VERSION 5.8 ;
BUSBITCHARS "[]" ;
DIVIDERCHAR "/" ;
UNITS
    DATABASE MICRONS 1000 ;
END UNITS

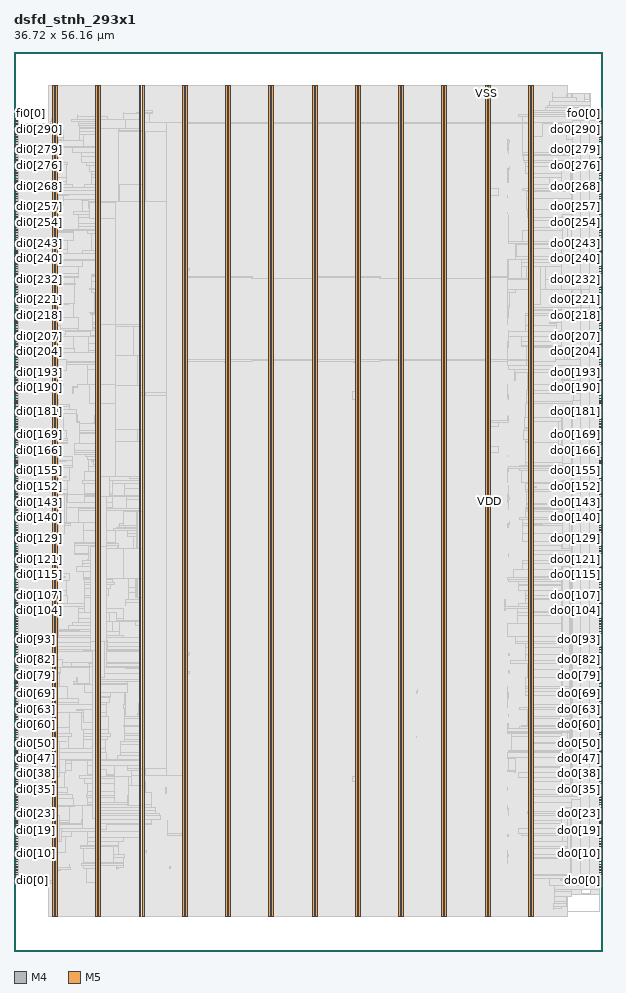
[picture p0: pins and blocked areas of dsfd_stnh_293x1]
MACRO dsfd_stnh_293x1
  FOREIGN dsfd_stnh_293x1 0 0 ;
  CLASS BLOCK ;
  SIZE 36.72 BY 56.16 ;
  PIN di0[0]
    DIRECTION INPUT ;
    USE SIGNAL ;
    PORT
      LAYER M4 ;
        RECT  0 4.416 0.192 4.44 ;
    END
  END di0[0]
  PIN di0[100]
    DIRECTION INPUT ;
    USE SIGNAL ;
    PORT
      LAYER M4 ;
        RECT  0 20.592 0.192 20.616 ;
    END
  END di0[100]
  PIN di0[101]
    DIRECTION INPUT ;
    USE SIGNAL ;
    PORT
      LAYER M4 ;
        RECT  0 20.736 0.192 20.76 ;
    END
  END di0[101]
  PIN di0[102]
    DIRECTION INPUT ;
    USE SIGNAL ;
    PORT
      LAYER M4 ;
        RECT  0 20.88 0.192 20.904 ;
    END
  END di0[102]
  PIN di0[103]
    DIRECTION INPUT ;
    USE SIGNAL ;
    PORT
      LAYER M4 ;
        RECT  0 21.072 0.192 21.096 ;
    END
  END di0[103]
  PIN di0[104]
    DIRECTION INPUT ;
    USE SIGNAL ;
    PORT
      LAYER M4 ;
        RECT  0 21.216 0.192 21.24 ;
    END
  END di0[104]
  PIN di0[105]
    DIRECTION INPUT ;
    USE SIGNAL ;
    PORT
      LAYER M4 ;
        RECT  0 21.408 0.192 21.432 ;
    END
  END di0[105]
  PIN di0[106]
    DIRECTION INPUT ;
    USE SIGNAL ;
    PORT
      LAYER M4 ;
        RECT  0 21.552 0.192 21.576 ;
    END
  END di0[106]
  PIN di0[107]
    DIRECTION INPUT ;
    USE SIGNAL ;
    PORT
      LAYER M4 ;
        RECT  0 21.696 0.192 21.72 ;
    END
  END di0[107]
  PIN di0[108]
    DIRECTION INPUT ;
    USE SIGNAL ;
    PORT
      LAYER M4 ;
        RECT  0 21.888 0.192 21.912 ;
    END
  END di0[108]
  PIN di0[109]
    DIRECTION INPUT ;
    USE SIGNAL ;
    PORT
      LAYER M4 ;
        RECT  0 22.032 0.192 22.056 ;
    END
  END di0[109]
  PIN di0[10]
    DIRECTION INPUT ;
    USE SIGNAL ;
    PORT
      LAYER M4 ;
        RECT  0 6.048 0.192 6.072 ;
    END
  END di0[10]
  PIN di0[110]
    DIRECTION INPUT ;
    USE SIGNAL ;
    PORT
      LAYER M4 ;
        RECT  0 22.176 0.192 22.2 ;
    END
  END di0[110]
  PIN di0[111]
    DIRECTION INPUT ;
    USE SIGNAL ;
    PORT
      LAYER M4 ;
        RECT  0 22.368 0.192 22.392 ;
    END
  END di0[111]
  PIN di0[112]
    DIRECTION INPUT ;
    USE SIGNAL ;
    PORT
      LAYER M4 ;
        RECT  0 22.512 0.192 22.536 ;
    END
  END di0[112]
  PIN di0[113]
    DIRECTION INPUT ;
    USE SIGNAL ;
    PORT
      LAYER M4 ;
        RECT  0 22.656 0.192 22.68 ;
    END
  END di0[113]
  PIN di0[114]
    DIRECTION INPUT ;
    USE SIGNAL ;
    PORT
      LAYER M4 ;
        RECT  0 22.848 0.192 22.872 ;
    END
  END di0[114]
  PIN di0[115]
    DIRECTION INPUT ;
    USE SIGNAL ;
    PORT
      LAYER M4 ;
        RECT  0 22.992 0.192 23.016 ;
    END
  END di0[115]
  PIN di0[116]
    DIRECTION INPUT ;
    USE SIGNAL ;
    PORT
      LAYER M4 ;
        RECT  0 23.184 0.192 23.208 ;
    END
  END di0[116]
  PIN di0[117]
    DIRECTION INPUT ;
    USE SIGNAL ;
    PORT
      LAYER M4 ;
        RECT  0 23.328 0.192 23.352 ;
    END
  END di0[117]
  PIN di0[118]
    DIRECTION INPUT ;
    USE SIGNAL ;
    PORT
      LAYER M4 ;
        RECT  0 23.472 0.192 23.496 ;
    END
  END di0[118]
  PIN di0[119]
    DIRECTION INPUT ;
    USE SIGNAL ;
    PORT
      LAYER M4 ;
        RECT  0 23.664 0.192 23.688 ;
    END
  END di0[119]
  PIN di0[11]
    DIRECTION INPUT ;
    USE SIGNAL ;
    PORT
      LAYER M4 ;
        RECT  0 6.192 0.192 6.216 ;
    END
  END di0[11]
  PIN di0[120]
    DIRECTION INPUT ;
    USE SIGNAL ;
    PORT
      LAYER M4 ;
        RECT  0 23.808 0.192 23.832 ;
    END
  END di0[120]
  PIN di0[121]
    DIRECTION INPUT ;
    USE SIGNAL ;
    PORT
      LAYER M4 ;
        RECT  0 23.952 0.192 23.976 ;
    END
  END di0[121]
  PIN di0[122]
    DIRECTION INPUT ;
    USE SIGNAL ;
    PORT
      LAYER M4 ;
        RECT  0 24.144 0.192 24.168 ;
    END
  END di0[122]
  PIN di0[123]
    DIRECTION INPUT ;
    USE SIGNAL ;
    PORT
      LAYER M4 ;
        RECT  0 24.288 0.192 24.312 ;
    END
  END di0[123]
  PIN di0[124]
    DIRECTION INPUT ;
    USE SIGNAL ;
    PORT
      LAYER M4 ;
        RECT  0 24.432 0.192 24.456 ;
    END
  END di0[124]
  PIN di0[125]
    DIRECTION INPUT ;
    USE SIGNAL ;
    PORT
      LAYER M4 ;
        RECT  0 24.624 0.192 24.648 ;
    END
  END di0[125]
  PIN di0[126]
    DIRECTION INPUT ;
    USE SIGNAL ;
    PORT
      LAYER M4 ;
        RECT  0 24.768 0.192 24.792 ;
    END
  END di0[126]
  PIN di0[127]
    DIRECTION INPUT ;
    USE SIGNAL ;
    PORT
      LAYER M4 ;
        RECT  0 24.96 0.192 24.984 ;
    END
  END di0[127]
  PIN di0[128]
    DIRECTION INPUT ;
    USE SIGNAL ;
    PORT
      LAYER M4 ;
        RECT  0 25.104 0.192 25.128 ;
    END
  END di0[128]
  PIN di0[129]
    DIRECTION INPUT ;
    USE SIGNAL ;
    PORT
      LAYER M4 ;
        RECT  0 25.248 0.192 25.272 ;
    END
  END di0[129]
  PIN di0[12]
    DIRECTION INPUT ;
    USE SIGNAL ;
    PORT
      LAYER M4 ;
        RECT  0 6.336 0.192 6.36 ;
    END
  END di0[12]
  PIN di0[130]
    DIRECTION INPUT ;
    USE SIGNAL ;
    PORT
      LAYER M4 ;
        RECT  0 25.44 0.192 25.464 ;
    END
  END di0[130]
  PIN di0[131]
    DIRECTION INPUT ;
    USE SIGNAL ;
    PORT
      LAYER M4 ;
        RECT  0 25.584 0.192 25.608 ;
    END
  END di0[131]
  PIN di0[132]
    DIRECTION INPUT ;
    USE SIGNAL ;
    PORT
      LAYER M4 ;
        RECT  0 25.728 0.192 25.752 ;
    END
  END di0[132]
  PIN di0[133]
    DIRECTION INPUT ;
    USE SIGNAL ;
    PORT
      LAYER M4 ;
        RECT  0 25.92 0.192 25.944 ;
    END
  END di0[133]
  PIN di0[134]
    DIRECTION INPUT ;
    USE SIGNAL ;
    PORT
      LAYER M4 ;
        RECT  0 26.064 0.192 26.088 ;
    END
  END di0[134]
  PIN di0[135]
    DIRECTION INPUT ;
    USE SIGNAL ;
    PORT
      LAYER M4 ;
        RECT  0 26.256 0.192 26.28 ;
    END
  END di0[135]
  PIN di0[136]
    DIRECTION INPUT ;
    USE SIGNAL ;
    PORT
      LAYER M4 ;
        RECT  0 26.4 0.192 26.424 ;
    END
  END di0[136]
  PIN di0[137]
    DIRECTION INPUT ;
    USE SIGNAL ;
    PORT
      LAYER M4 ;
        RECT  0 26.544 0.192 26.568 ;
    END
  END di0[137]
  PIN di0[138]
    DIRECTION INPUT ;
    USE SIGNAL ;
    PORT
      LAYER M4 ;
        RECT  0 26.736 0.192 26.76 ;
    END
  END di0[138]
  PIN di0[139]
    DIRECTION INPUT ;
    USE SIGNAL ;
    PORT
      LAYER M4 ;
        RECT  0 26.88 0.192 26.904 ;
    END
  END di0[139]
  PIN di0[13]
    DIRECTION INPUT ;
    USE SIGNAL ;
    PORT
      LAYER M4 ;
        RECT  0 6.528 0.192 6.552 ;
    END
  END di0[13]
  PIN di0[140]
    DIRECTION INPUT ;
    USE SIGNAL ;
    PORT
      LAYER M4 ;
        RECT  0 27.024 0.192 27.048 ;
    END
  END di0[140]
  PIN di0[141]
    DIRECTION INPUT ;
    USE SIGNAL ;
    PORT
      LAYER M4 ;
        RECT  0 27.216 0.192 27.24 ;
    END
  END di0[141]
  PIN di0[142]
    DIRECTION INPUT ;
    USE SIGNAL ;
    PORT
      LAYER M4 ;
        RECT  0 27.36 0.192 27.384 ;
    END
  END di0[142]
  PIN di0[143]
    DIRECTION INPUT ;
    USE SIGNAL ;
    PORT
      LAYER M4 ;
        RECT  0 27.504 0.192 27.528 ;
    END
  END di0[143]
  PIN di0[144]
    DIRECTION INPUT ;
    USE SIGNAL ;
    PORT
      LAYER M4 ;
        RECT  0 27.696 0.192 27.72 ;
    END
  END di0[144]
  PIN di0[145]
    DIRECTION INPUT ;
    USE SIGNAL ;
    PORT
      LAYER M4 ;
        RECT  0 27.84 0.192 27.864 ;
    END
  END di0[145]
  PIN di0[146]
    DIRECTION INPUT ;
    USE SIGNAL ;
    PORT
      LAYER M4 ;
        RECT  0 28.032 0.192 28.056 ;
    END
  END di0[146]
  PIN di0[147]
    DIRECTION INPUT ;
    USE SIGNAL ;
    PORT
      LAYER M4 ;
        RECT  0 28.176 0.192 28.2 ;
    END
  END di0[147]
  PIN di0[148]
    DIRECTION INPUT ;
    USE SIGNAL ;
    PORT
      LAYER M4 ;
        RECT  0 28.32 0.192 28.344 ;
    END
  END di0[148]
  PIN di0[149]
    DIRECTION INPUT ;
    USE SIGNAL ;
    PORT
      LAYER M4 ;
        RECT  0 28.512 0.192 28.536 ;
    END
  END di0[149]
  PIN di0[14]
    DIRECTION INPUT ;
    USE SIGNAL ;
    PORT
      LAYER M4 ;
        RECT  0 6.672 0.192 6.696 ;
    END
  END di0[14]
  PIN di0[150]
    DIRECTION INPUT ;
    USE SIGNAL ;
    PORT
      LAYER M4 ;
        RECT  0 28.656 0.192 28.68 ;
    END
  END di0[150]
  PIN di0[151]
    DIRECTION INPUT ;
    USE SIGNAL ;
    PORT
      LAYER M4 ;
        RECT  0 28.8 0.192 28.824 ;
    END
  END di0[151]
  PIN di0[152]
    DIRECTION INPUT ;
    USE SIGNAL ;
    PORT
      LAYER M4 ;
        RECT  0 28.992 0.192 29.016 ;
    END
  END di0[152]
  PIN di0[153]
    DIRECTION INPUT ;
    USE SIGNAL ;
    PORT
      LAYER M4 ;
        RECT  0 29.136 0.192 29.16 ;
    END
  END di0[153]
  PIN di0[154]
    DIRECTION INPUT ;
    USE SIGNAL ;
    PORT
      LAYER M4 ;
        RECT  0 29.328 0.192 29.352 ;
    END
  END di0[154]
  PIN di0[155]
    DIRECTION INPUT ;
    USE SIGNAL ;
    PORT
      LAYER M4 ;
        RECT  0 29.472 0.192 29.496 ;
    END
  END di0[155]
  PIN di0[156]
    DIRECTION INPUT ;
    USE SIGNAL ;
    PORT
      LAYER M4 ;
        RECT  0 29.616 0.192 29.64 ;
    END
  END di0[156]
  PIN di0[157]
    DIRECTION INPUT ;
    USE SIGNAL ;
    PORT
      LAYER M4 ;
        RECT  0 29.808 0.192 29.832 ;
    END
  END di0[157]
  PIN di0[158]
    DIRECTION INPUT ;
    USE SIGNAL ;
    PORT
      LAYER M4 ;
        RECT  0 29.952 0.192 29.976 ;
    END
  END di0[158]
  PIN di0[159]
    DIRECTION INPUT ;
    USE SIGNAL ;
    PORT
      LAYER M4 ;
        RECT  0 30.096 0.192 30.12 ;
    END
  END di0[159]
  PIN di0[15]
    DIRECTION INPUT ;
    USE SIGNAL ;
    PORT
      LAYER M4 ;
        RECT  0 6.816 0.192 6.84 ;
    END
  END di0[15]
  PIN di0[160]
    DIRECTION INPUT ;
    USE SIGNAL ;
    PORT
      LAYER M4 ;
        RECT  0 30.288 0.192 30.312 ;
    END
  END di0[160]
  PIN di0[161]
    DIRECTION INPUT ;
    USE SIGNAL ;
    PORT
      LAYER M4 ;
        RECT  0 30.432 0.192 30.456 ;
    END
  END di0[161]
  PIN di0[162]
    DIRECTION INPUT ;
    USE SIGNAL ;
    PORT
      LAYER M4 ;
        RECT  0 30.576 0.192 30.6 ;
    END
  END di0[162]
  PIN di0[163]
    DIRECTION INPUT ;
    USE SIGNAL ;
    PORT
      LAYER M4 ;
        RECT  0 30.768 0.192 30.792 ;
    END
  END di0[163]
  PIN di0[164]
    DIRECTION INPUT ;
    USE SIGNAL ;
    PORT
      LAYER M4 ;
        RECT  0 30.912 0.192 30.936 ;
    END
  END di0[164]
  PIN di0[165]
    DIRECTION INPUT ;
    USE SIGNAL ;
    PORT
      LAYER M4 ;
        RECT  0 31.104 0.192 31.128 ;
    END
  END di0[165]
  PIN di0[166]
    DIRECTION INPUT ;
    USE SIGNAL ;
    PORT
      LAYER M4 ;
        RECT  0 31.248 0.192 31.272 ;
    END
  END di0[166]
  PIN di0[167]
    DIRECTION INPUT ;
    USE SIGNAL ;
    PORT
      LAYER M4 ;
        RECT  0 31.392 0.192 31.416 ;
    END
  END di0[167]
  PIN di0[168]
    DIRECTION INPUT ;
    USE SIGNAL ;
    PORT
      LAYER M4 ;
        RECT  0 31.584 0.192 31.608 ;
    END
  END di0[168]
  PIN di0[169]
    DIRECTION INPUT ;
    USE SIGNAL ;
    PORT
      LAYER M4 ;
        RECT  0 31.728 0.192 31.752 ;
    END
  END di0[169]
  PIN di0[16]
    DIRECTION INPUT ;
    USE SIGNAL ;
    PORT
      LAYER M4 ;
        RECT  0 7.008 0.192 7.032 ;
    END
  END di0[16]
  PIN di0[170]
    DIRECTION INPUT ;
    USE SIGNAL ;
    PORT
      LAYER M4 ;
        RECT  0 31.872 0.192 31.896 ;
    END
  END di0[170]
  PIN di0[171]
    DIRECTION INPUT ;
    USE SIGNAL ;
    PORT
      LAYER M4 ;
        RECT  0 32.064 0.192 32.088 ;
    END
  END di0[171]
  PIN di0[172]
    DIRECTION INPUT ;
    USE SIGNAL ;
    PORT
      LAYER M4 ;
        RECT  0 32.208 0.192 32.232 ;
    END
  END di0[172]
  PIN di0[173]
    DIRECTION INPUT ;
    USE SIGNAL ;
    PORT
      LAYER M4 ;
        RECT  0 32.352 0.192 32.376 ;
    END
  END di0[173]
  PIN di0[174]
    DIRECTION INPUT ;
    USE SIGNAL ;
    PORT
      LAYER M4 ;
        RECT  0 32.544 0.192 32.568 ;
    END
  END di0[174]
  PIN di0[175]
    DIRECTION INPUT ;
    USE SIGNAL ;
    PORT
      LAYER M4 ;
        RECT  0 32.688 0.192 32.712 ;
    END
  END di0[175]
  PIN di0[176]
    DIRECTION INPUT ;
    USE SIGNAL ;
    PORT
      LAYER M4 ;
        RECT  0 32.88 0.192 32.904 ;
    END
  END di0[176]
  PIN di0[177]
    DIRECTION INPUT ;
    USE SIGNAL ;
    PORT
      LAYER M4 ;
        RECT  0 33.024 0.192 33.048 ;
    END
  END di0[177]
  PIN di0[178]
    DIRECTION INPUT ;
    USE SIGNAL ;
    PORT
      LAYER M4 ;
        RECT  0 33.168 0.192 33.192 ;
    END
  END di0[178]
  PIN di0[179]
    DIRECTION INPUT ;
    USE SIGNAL ;
    PORT
      LAYER M4 ;
        RECT  0 33.36 0.192 33.384 ;
    END
  END di0[179]
  PIN di0[17]
    DIRECTION INPUT ;
    USE SIGNAL ;
    PORT
      LAYER M4 ;
        RECT  0 7.152 0.192 7.176 ;
    END
  END di0[17]
  PIN di0[180]
    DIRECTION INPUT ;
    USE SIGNAL ;
    PORT
      LAYER M4 ;
        RECT  0 33.504 0.192 33.528 ;
    END
  END di0[180]
  PIN di0[181]
    DIRECTION INPUT ;
    USE SIGNAL ;
    PORT
      LAYER M4 ;
        RECT  0 33.648 0.192 33.672 ;
    END
  END di0[181]
  PIN di0[182]
    DIRECTION INPUT ;
    USE SIGNAL ;
    PORT
      LAYER M4 ;
        RECT  0 33.84 0.192 33.864 ;
    END
  END di0[182]
  PIN di0[183]
    DIRECTION INPUT ;
    USE SIGNAL ;
    PORT
      LAYER M4 ;
        RECT  0 33.984 0.192 34.008 ;
    END
  END di0[183]
  PIN di0[184]
    DIRECTION INPUT ;
    USE SIGNAL ;
    PORT
      LAYER M4 ;
        RECT  0 34.176 0.192 34.2 ;
    END
  END di0[184]
  PIN di0[185]
    DIRECTION INPUT ;
    USE SIGNAL ;
    PORT
      LAYER M4 ;
        RECT  0 34.32 0.192 34.344 ;
    END
  END di0[185]
  PIN di0[186]
    DIRECTION INPUT ;
    USE SIGNAL ;
    PORT
      LAYER M4 ;
        RECT  0 34.464 0.192 34.488 ;
    END
  END di0[186]
  PIN di0[187]
    DIRECTION INPUT ;
    USE SIGNAL ;
    PORT
      LAYER M4 ;
        RECT  0 34.656 0.192 34.68 ;
    END
  END di0[187]
  PIN di0[188]
    DIRECTION INPUT ;
    USE SIGNAL ;
    PORT
      LAYER M4 ;
        RECT  0 34.8 0.192 34.824 ;
    END
  END di0[188]
  PIN di0[189]
    DIRECTION INPUT ;
    USE SIGNAL ;
    PORT
      LAYER M4 ;
        RECT  0 34.944 0.192 34.968 ;
    END
  END di0[189]
  PIN di0[18]
    DIRECTION INPUT ;
    USE SIGNAL ;
    PORT
      LAYER M4 ;
        RECT  0 7.344 0.192 7.368 ;
    END
  END di0[18]
  PIN di0[190]
    DIRECTION INPUT ;
    USE SIGNAL ;
    PORT
      LAYER M4 ;
        RECT  0 35.136 0.192 35.16 ;
    END
  END di0[190]
  PIN di0[191]
    DIRECTION INPUT ;
    USE SIGNAL ;
    PORT
      LAYER M4 ;
        RECT  0 35.28 0.192 35.304 ;
    END
  END di0[191]
  PIN di0[192]
    DIRECTION INPUT ;
    USE SIGNAL ;
    PORT
      LAYER M4 ;
        RECT  0 35.424 0.192 35.448 ;
    END
  END di0[192]
  PIN di0[193]
    DIRECTION INPUT ;
    USE SIGNAL ;
    PORT
      LAYER M4 ;
        RECT  0 35.616 0.192 35.64 ;
    END
  END di0[193]
  PIN di0[194]
    DIRECTION INPUT ;
    USE SIGNAL ;
    PORT
      LAYER M4 ;
        RECT  0 35.76 0.192 35.784 ;
    END
  END di0[194]
  PIN di0[195]
    DIRECTION INPUT ;
    USE SIGNAL ;
    PORT
      LAYER M4 ;
        RECT  0 35.952 0.192 35.976 ;
    END
  END di0[195]
  PIN di0[196]
    DIRECTION INPUT ;
    USE SIGNAL ;
    PORT
      LAYER M4 ;
        RECT  0 36.096 0.192 36.12 ;
    END
  END di0[196]
  PIN di0[197]
    DIRECTION INPUT ;
    USE SIGNAL ;
    PORT
      LAYER M4 ;
        RECT  0 36.24 0.192 36.264 ;
    END
  END di0[197]
  PIN di0[198]
    DIRECTION INPUT ;
    USE SIGNAL ;
    PORT
      LAYER M4 ;
        RECT  0 36.432 0.192 36.456 ;
    END
  END di0[198]
  PIN di0[199]
    DIRECTION INPUT ;
    USE SIGNAL ;
    PORT
      LAYER M4 ;
        RECT  0 36.576 0.192 36.6 ;
    END
  END di0[199]
  PIN di0[19]
    DIRECTION INPUT ;
    USE SIGNAL ;
    PORT
      LAYER M4 ;
        RECT  0 7.488 0.192 7.512 ;
    END
  END di0[19]
  PIN di0[1]
    DIRECTION INPUT ;
    USE SIGNAL ;
    PORT
      LAYER M4 ;
        RECT  0 4.56 0.192 4.584 ;
    END
  END di0[1]
  PIN di0[200]
    DIRECTION INPUT ;
    USE SIGNAL ;
    PORT
      LAYER M4 ;
        RECT  0 36.72 0.192 36.744 ;
    END
  END di0[200]
  PIN di0[201]
    DIRECTION INPUT ;
    USE SIGNAL ;
    PORT
      LAYER M4 ;
        RECT  0 36.912 0.192 36.936 ;
    END
  END di0[201]
  PIN di0[202]
    DIRECTION INPUT ;
    USE SIGNAL ;
    PORT
      LAYER M4 ;
        RECT  0 37.056 0.192 37.08 ;
    END
  END di0[202]
  PIN di0[203]
    DIRECTION INPUT ;
    USE SIGNAL ;
    PORT
      LAYER M4 ;
        RECT  0 37.248 0.192 37.272 ;
    END
  END di0[203]
  PIN di0[204]
    DIRECTION INPUT ;
    USE SIGNAL ;
    PORT
      LAYER M4 ;
        RECT  0 37.392 0.192 37.416 ;
    END
  END di0[204]
  PIN di0[205]
    DIRECTION INPUT ;
    USE SIGNAL ;
    PORT
      LAYER M4 ;
        RECT  0 37.536 0.192 37.56 ;
    END
  END di0[205]
  PIN di0[206]
    DIRECTION INPUT ;
    USE SIGNAL ;
    PORT
      LAYER M4 ;
        RECT  0 37.728 0.192 37.752 ;
    END
  END di0[206]
  PIN di0[207]
    DIRECTION INPUT ;
    USE SIGNAL ;
    PORT
      LAYER M4 ;
        RECT  0 37.872 0.192 37.896 ;
    END
  END di0[207]
  PIN di0[208]
    DIRECTION INPUT ;
    USE SIGNAL ;
    PORT
      LAYER M4 ;
        RECT  0 38.016 0.192 38.04 ;
    END
  END di0[208]
  PIN di0[209]
    DIRECTION INPUT ;
    USE SIGNAL ;
    PORT
      LAYER M4 ;
        RECT  0 38.208 0.192 38.232 ;
    END
  END di0[209]
  PIN di0[20]
    DIRECTION INPUT ;
    USE SIGNAL ;
    PORT
      LAYER M4 ;
        RECT  0 7.632 0.192 7.656 ;
    END
  END di0[20]
  PIN di0[210]
    DIRECTION INPUT ;
    USE SIGNAL ;
    PORT
      LAYER M4 ;
        RECT  0 38.352 0.192 38.376 ;
    END
  END di0[210]
  PIN di0[211]
    DIRECTION INPUT ;
    USE SIGNAL ;
    PORT
      LAYER M4 ;
        RECT  0 38.496 0.192 38.52 ;
    END
  END di0[211]
  PIN di0[212]
    DIRECTION INPUT ;
    USE SIGNAL ;
    PORT
      LAYER M4 ;
        RECT  0 38.688 0.192 38.712 ;
    END
  END di0[212]
  PIN di0[213]
    DIRECTION INPUT ;
    USE SIGNAL ;
    PORT
      LAYER M4 ;
        RECT  0 38.832 0.192 38.856 ;
    END
  END di0[213]
  PIN di0[214]
    DIRECTION INPUT ;
    USE SIGNAL ;
    PORT
      LAYER M4 ;
        RECT  0 39.024 0.192 39.048 ;
    END
  END di0[214]
  PIN di0[215]
    DIRECTION INPUT ;
    USE SIGNAL ;
    PORT
      LAYER M4 ;
        RECT  0 39.168 0.192 39.192 ;
    END
  END di0[215]
  PIN di0[216]
    DIRECTION INPUT ;
    USE SIGNAL ;
    PORT
      LAYER M4 ;
        RECT  0 39.312 0.192 39.336 ;
    END
  END di0[216]
  PIN di0[217]
    DIRECTION INPUT ;
    USE SIGNAL ;
    PORT
      LAYER M4 ;
        RECT  0 39.504 0.192 39.528 ;
    END
  END di0[217]
  PIN di0[218]
    DIRECTION INPUT ;
    USE SIGNAL ;
    PORT
      LAYER M4 ;
        RECT  0 39.648 0.192 39.672 ;
    END
  END di0[218]
  PIN di0[219]
    DIRECTION INPUT ;
    USE SIGNAL ;
    PORT
      LAYER M4 ;
        RECT  0 39.792 0.192 39.816 ;
    END
  END di0[219]
  PIN di0[21]
    DIRECTION INPUT ;
    USE SIGNAL ;
    PORT
      LAYER M4 ;
        RECT  0 7.824 0.192 7.848 ;
    END
  END di0[21]
  PIN di0[220]
    DIRECTION INPUT ;
    USE SIGNAL ;
    PORT
      LAYER M4 ;
        RECT  0 39.984 0.192 40.008 ;
    END
  END di0[220]
  PIN di0[221]
    DIRECTION INPUT ;
    USE SIGNAL ;
    PORT
      LAYER M4 ;
        RECT  0 40.128 0.192 40.152 ;
    END
  END di0[221]
  PIN di0[222]
    DIRECTION INPUT ;
    USE SIGNAL ;
    PORT
      LAYER M4 ;
        RECT  0 40.272 0.192 40.296 ;
    END
  END di0[222]
  PIN di0[223]
    DIRECTION INPUT ;
    USE SIGNAL ;
    PORT
      LAYER M4 ;
        RECT  0 40.464 0.192 40.488 ;
    END
  END di0[223]
  PIN di0[224]
    DIRECTION INPUT ;
    USE SIGNAL ;
    PORT
      LAYER M4 ;
        RECT  0 40.608 0.192 40.632 ;
    END
  END di0[224]
  PIN di0[225]
    DIRECTION INPUT ;
    USE SIGNAL ;
    PORT
      LAYER M4 ;
        RECT  0 40.8 0.192 40.824 ;
    END
  END di0[225]
  PIN di0[226]
    DIRECTION INPUT ;
    USE SIGNAL ;
    PORT
      LAYER M4 ;
        RECT  0 40.944 0.192 40.968 ;
    END
  END di0[226]
  PIN di0[227]
    DIRECTION INPUT ;
    USE SIGNAL ;
    PORT
      LAYER M4 ;
        RECT  0 41.088 0.192 41.112 ;
    END
  END di0[227]
  PIN di0[228]
    DIRECTION INPUT ;
    USE SIGNAL ;
    PORT
      LAYER M4 ;
        RECT  0 41.28 0.192 41.304 ;
    END
  END di0[228]
  PIN di0[229]
    DIRECTION INPUT ;
    USE SIGNAL ;
    PORT
      LAYER M4 ;
        RECT  0 41.424 0.192 41.448 ;
    END
  END di0[229]
  PIN di0[22]
    DIRECTION INPUT ;
    USE SIGNAL ;
    PORT
      LAYER M4 ;
        RECT  0 7.968 0.192 7.992 ;
    END
  END di0[22]
  PIN di0[230]
    DIRECTION INPUT ;
    USE SIGNAL ;
    PORT
      LAYER M4 ;
        RECT  0 41.568 0.192 41.592 ;
    END
  END di0[230]
  PIN di0[231]
    DIRECTION INPUT ;
    USE SIGNAL ;
    PORT
      LAYER M4 ;
        RECT  0 41.76 0.192 41.784 ;
    END
  END di0[231]
  PIN di0[232]
    DIRECTION INPUT ;
    USE SIGNAL ;
    PORT
      LAYER M4 ;
        RECT  0 41.904 0.192 41.928 ;
    END
  END di0[232]
  PIN di0[233]
    DIRECTION INPUT ;
    USE SIGNAL ;
    PORT
      LAYER M4 ;
        RECT  0 42.096 0.192 42.12 ;
    END
  END di0[233]
  PIN di0[234]
    DIRECTION INPUT ;
    USE SIGNAL ;
    PORT
      LAYER M4 ;
        RECT  0 42.24 0.192 42.264 ;
    END
  END di0[234]
  PIN di0[235]
    DIRECTION INPUT ;
    USE SIGNAL ;
    PORT
      LAYER M4 ;
        RECT  0 42.384 0.192 42.408 ;
    END
  END di0[235]
  PIN di0[236]
    DIRECTION INPUT ;
    USE SIGNAL ;
    PORT
      LAYER M4 ;
        RECT  0 42.576 0.192 42.6 ;
    END
  END di0[236]
  PIN di0[237]
    DIRECTION INPUT ;
    USE SIGNAL ;
    PORT
      LAYER M4 ;
        RECT  0 42.72 0.192 42.744 ;
    END
  END di0[237]
  PIN di0[238]
    DIRECTION INPUT ;
    USE SIGNAL ;
    PORT
      LAYER M4 ;
        RECT  0 42.864 0.192 42.888 ;
    END
  END di0[238]
  PIN di0[239]
    DIRECTION INPUT ;
    USE SIGNAL ;
    PORT
      LAYER M4 ;
        RECT  0 43.056 0.192 43.08 ;
    END
  END di0[239]
  PIN di0[23]
    DIRECTION INPUT ;
    USE SIGNAL ;
    PORT
      LAYER M4 ;
        RECT  0 8.112 0.192 8.136 ;
    END
  END di0[23]
  PIN di0[240]
    DIRECTION INPUT ;
    USE SIGNAL ;
    PORT
      LAYER M4 ;
        RECT  0 43.2 0.192 43.224 ;
    END
  END di0[240]
  PIN di0[241]
    DIRECTION INPUT ;
    USE SIGNAL ;
    PORT
      LAYER M4 ;
        RECT  0 43.344 0.192 43.368 ;
    END
  END di0[241]
  PIN di0[242]
    DIRECTION INPUT ;
    USE SIGNAL ;
    PORT
      LAYER M4 ;
        RECT  0 43.536 0.192 43.56 ;
    END
  END di0[242]
  PIN di0[243]
    DIRECTION INPUT ;
    USE SIGNAL ;
    PORT
      LAYER M4 ;
        RECT  0 43.68 0.192 43.704 ;
    END
  END di0[243]
  PIN di0[244]
    DIRECTION INPUT ;
    USE SIGNAL ;
    PORT
      LAYER M4 ;
        RECT  0 43.872 0.192 43.896 ;
    END
  END di0[244]
  PIN di0[245]
    DIRECTION INPUT ;
    USE SIGNAL ;
    PORT
      LAYER M4 ;
        RECT  0 44.016 0.192 44.04 ;
    END
  END di0[245]
  PIN di0[246]
    DIRECTION INPUT ;
    USE SIGNAL ;
    PORT
      LAYER M4 ;
        RECT  0 44.16 0.192 44.184 ;
    END
  END di0[246]
  PIN di0[247]
    DIRECTION INPUT ;
    USE SIGNAL ;
    PORT
      LAYER M4 ;
        RECT  0 44.352 0.192 44.376 ;
    END
  END di0[247]
  PIN di0[248]
    DIRECTION INPUT ;
    USE SIGNAL ;
    PORT
      LAYER M4 ;
        RECT  0 44.496 0.192 44.52 ;
    END
  END di0[248]
  PIN di0[249]
    DIRECTION INPUT ;
    USE SIGNAL ;
    PORT
      LAYER M4 ;
        RECT  0 44.64 0.192 44.664 ;
    END
  END di0[249]
  PIN di0[24]
    DIRECTION INPUT ;
    USE SIGNAL ;
    PORT
      LAYER M4 ;
        RECT  0 8.304 0.192 8.328 ;
    END
  END di0[24]
  PIN di0[250]
    DIRECTION INPUT ;
    USE SIGNAL ;
    PORT
      LAYER M4 ;
        RECT  0 44.832 0.192 44.856 ;
    END
  END di0[250]
  PIN di0[251]
    DIRECTION INPUT ;
    USE SIGNAL ;
    PORT
      LAYER M4 ;
        RECT  0 44.976 0.192 45 ;
    END
  END di0[251]
  PIN di0[252]
    DIRECTION INPUT ;
    USE SIGNAL ;
    PORT
      LAYER M4 ;
        RECT  0 45.168 0.192 45.192 ;
    END
  END di0[252]
  PIN di0[253]
    DIRECTION INPUT ;
    USE SIGNAL ;
    PORT
      LAYER M4 ;
        RECT  0 45.312 0.192 45.336 ;
    END
  END di0[253]
  PIN di0[254]
    DIRECTION INPUT ;
    USE SIGNAL ;
    PORT
      LAYER M4 ;
        RECT  0 45.456 0.192 45.48 ;
    END
  END di0[254]
  PIN di0[255]
    DIRECTION INPUT ;
    USE SIGNAL ;
    PORT
      LAYER M4 ;
        RECT  0 45.648 0.192 45.672 ;
    END
  END di0[255]
  PIN di0[256]
    DIRECTION INPUT ;
    USE SIGNAL ;
    PORT
      LAYER M4 ;
        RECT  0 45.792 0.192 45.816 ;
    END
  END di0[256]
  PIN di0[257]
    DIRECTION INPUT ;
    USE SIGNAL ;
    PORT
      LAYER M4 ;
        RECT  0 45.936 0.192 45.96 ;
    END
  END di0[257]
  PIN di0[258]
    DIRECTION INPUT ;
    USE SIGNAL ;
    PORT
      LAYER M4 ;
        RECT  0 46.128 0.192 46.152 ;
    END
  END di0[258]
  PIN di0[259]
    DIRECTION INPUT ;
    USE SIGNAL ;
    PORT
      LAYER M4 ;
        RECT  0 46.272 0.192 46.296 ;
    END
  END di0[259]
  PIN di0[25]
    DIRECTION INPUT ;
    USE SIGNAL ;
    PORT
      LAYER M4 ;
        RECT  0 8.448 0.192 8.472 ;
    END
  END di0[25]
  PIN di0[260]
    DIRECTION INPUT ;
    USE SIGNAL ;
    PORT
      LAYER M4 ;
        RECT  0 46.416 0.192 46.44 ;
    END
  END di0[260]
  PIN di0[261]
    DIRECTION INPUT ;
    USE SIGNAL ;
    PORT
      LAYER M4 ;
        RECT  0 46.608 0.192 46.632 ;
    END
  END di0[261]
  PIN di0[262]
    DIRECTION INPUT ;
    USE SIGNAL ;
    PORT
      LAYER M4 ;
        RECT  0 46.752 0.192 46.776 ;
    END
  END di0[262]
  PIN di0[263]
    DIRECTION INPUT ;
    USE SIGNAL ;
    PORT
      LAYER M4 ;
        RECT  0 46.944 0.192 46.968 ;
    END
  END di0[263]
  PIN di0[264]
    DIRECTION INPUT ;
    USE SIGNAL ;
    PORT
      LAYER M4 ;
        RECT  0 47.088 0.192 47.112 ;
    END
  END di0[264]
  PIN di0[265]
    DIRECTION INPUT ;
    USE SIGNAL ;
    PORT
      LAYER M4 ;
        RECT  0 47.232 0.192 47.256 ;
    END
  END di0[265]
  PIN di0[266]
    DIRECTION INPUT ;
    USE SIGNAL ;
    PORT
      LAYER M4 ;
        RECT  0 47.424 0.192 47.448 ;
    END
  END di0[266]
  PIN di0[267]
    DIRECTION INPUT ;
    USE SIGNAL ;
    PORT
      LAYER M4 ;
        RECT  0 47.568 0.192 47.592 ;
    END
  END di0[267]
  PIN di0[268]
    DIRECTION INPUT ;
    USE SIGNAL ;
    PORT
      LAYER M4 ;
        RECT  0 47.712 0.192 47.736 ;
    END
  END di0[268]
  PIN di0[269]
    DIRECTION INPUT ;
    USE SIGNAL ;
    PORT
      LAYER M4 ;
        RECT  0 47.904 0.192 47.928 ;
    END
  END di0[269]
  PIN di0[26]
    DIRECTION INPUT ;
    USE SIGNAL ;
    PORT
      LAYER M4 ;
        RECT  0 8.592 0.192 8.616 ;
    END
  END di0[26]
  PIN di0[270]
    DIRECTION INPUT ;
    USE SIGNAL ;
    PORT
      LAYER M4 ;
        RECT  0 48.048 0.192 48.072 ;
    END
  END di0[270]
  PIN di0[271]
    DIRECTION INPUT ;
    USE SIGNAL ;
    PORT
      LAYER M4 ;
        RECT  0 48.192 0.192 48.216 ;
    END
  END di0[271]
  PIN di0[272]
    DIRECTION INPUT ;
    USE SIGNAL ;
    PORT
      LAYER M4 ;
        RECT  0 48.384 0.192 48.408 ;
    END
  END di0[272]
  PIN di0[273]
    DIRECTION INPUT ;
    USE SIGNAL ;
    PORT
      LAYER M4 ;
        RECT  0 48.528 0.192 48.552 ;
    END
  END di0[273]
  PIN di0[274]
    DIRECTION INPUT ;
    USE SIGNAL ;
    PORT
      LAYER M4 ;
        RECT  0 48.72 0.192 48.744 ;
    END
  END di0[274]
  PIN di0[275]
    DIRECTION INPUT ;
    USE SIGNAL ;
    PORT
      LAYER M4 ;
        RECT  0 48.864 0.192 48.888 ;
    END
  END di0[275]
  PIN di0[276]
    DIRECTION INPUT ;
    USE SIGNAL ;
    PORT
      LAYER M4 ;
        RECT  0 49.008 0.192 49.032 ;
    END
  END di0[276]
  PIN di0[277]
    DIRECTION INPUT ;
    USE SIGNAL ;
    PORT
      LAYER M4 ;
        RECT  0 49.2 0.192 49.224 ;
    END
  END di0[277]
  PIN di0[278]
    DIRECTION INPUT ;
    USE SIGNAL ;
    PORT
      LAYER M4 ;
        RECT  0 49.344 0.192 49.368 ;
    END
  END di0[278]
  PIN di0[279]
    DIRECTION INPUT ;
    USE SIGNAL ;
    PORT
      LAYER M4 ;
        RECT  0 49.488 0.192 49.512 ;
    END
  END di0[279]
  PIN di0[27]
    DIRECTION INPUT ;
    USE SIGNAL ;
    PORT
      LAYER M4 ;
        RECT  0 8.784 0.192 8.808 ;
    END
  END di0[27]
  PIN di0[280]
    DIRECTION INPUT ;
    USE SIGNAL ;
    PORT
      LAYER M4 ;
        RECT  0 49.68 0.192 49.704 ;
    END
  END di0[280]
  PIN di0[281]
    DIRECTION INPUT ;
    USE SIGNAL ;
    PORT
      LAYER M4 ;
        RECT  0 49.824 0.192 49.848 ;
    END
  END di0[281]
  PIN di0[282]
    DIRECTION INPUT ;
    USE SIGNAL ;
    PORT
      LAYER M4 ;
        RECT  0 50.016 0.192 50.04 ;
    END
  END di0[282]
  PIN di0[283]
    DIRECTION INPUT ;
    USE SIGNAL ;
    PORT
      LAYER M4 ;
        RECT  0 50.16 0.192 50.184 ;
    END
  END di0[283]
  PIN di0[284]
    DIRECTION INPUT ;
    USE SIGNAL ;
    PORT
      LAYER M4 ;
        RECT  0 50.304 0.192 50.328 ;
    END
  END di0[284]
  PIN di0[285]
    DIRECTION INPUT ;
    USE SIGNAL ;
    PORT
      LAYER M4 ;
        RECT  0 50.496 0.192 50.52 ;
    END
  END di0[285]
  PIN di0[286]
    DIRECTION INPUT ;
    USE SIGNAL ;
    PORT
      LAYER M4 ;
        RECT  0 50.64 0.192 50.664 ;
    END
  END di0[286]
  PIN di0[287]
    DIRECTION INPUT ;
    USE SIGNAL ;
    PORT
      LAYER M4 ;
        RECT  0 50.784 0.192 50.808 ;
    END
  END di0[287]
  PIN di0[288]
    DIRECTION INPUT ;
    USE SIGNAL ;
    PORT
      LAYER M4 ;
        RECT  0 50.976 0.192 51 ;
    END
  END di0[288]
  PIN di0[289]
    DIRECTION INPUT ;
    USE SIGNAL ;
    PORT
      LAYER M4 ;
        RECT  0 51.12 0.192 51.144 ;
    END
  END di0[289]
  PIN di0[28]
    DIRECTION INPUT ;
    USE SIGNAL ;
    PORT
      LAYER M4 ;
        RECT  0 8.928 0.192 8.952 ;
    END
  END di0[28]
  PIN di0[290]
    DIRECTION INPUT ;
    USE SIGNAL ;
    PORT
      LAYER M4 ;
        RECT  0 51.264 0.192 51.288 ;
    END
  END di0[290]
  PIN di0[291]
    DIRECTION INPUT ;
    USE SIGNAL ;
    PORT
      LAYER M4 ;
        RECT  0 51.456 0.192 51.48 ;
    END
  END di0[291]
  PIN di0[292]
    DIRECTION INPUT ;
    USE SIGNAL ;
    PORT
      LAYER M4 ;
        RECT  0 51.6 0.192 51.624 ;
    END
  END di0[292]
  PIN di0[29]
    DIRECTION INPUT ;
    USE SIGNAL ;
    PORT
      LAYER M4 ;
        RECT  0 9.12 0.192 9.144 ;
    END
  END di0[29]
  PIN di0[2]
    DIRECTION INPUT ;
    USE SIGNAL ;
    PORT
      LAYER M4 ;
        RECT  0 4.752 0.192 4.776 ;
    END
  END di0[2]
  PIN di0[30]
    DIRECTION INPUT ;
    USE SIGNAL ;
    PORT
      LAYER M4 ;
        RECT  0 9.264 0.192 9.288 ;
    END
  END di0[30]
  PIN di0[31]
    DIRECTION INPUT ;
    USE SIGNAL ;
    PORT
      LAYER M4 ;
        RECT  0 9.408 0.192 9.432 ;
    END
  END di0[31]
  PIN di0[32]
    DIRECTION INPUT ;
    USE SIGNAL ;
    PORT
      LAYER M4 ;
        RECT  0 9.6 0.192 9.624 ;
    END
  END di0[32]
  PIN di0[33]
    DIRECTION INPUT ;
    USE SIGNAL ;
    PORT
      LAYER M4 ;
        RECT  0 9.744 0.192 9.768 ;
    END
  END di0[33]
  PIN di0[34]
    DIRECTION INPUT ;
    USE SIGNAL ;
    PORT
      LAYER M4 ;
        RECT  0 9.888 0.192 9.912 ;
    END
  END di0[34]
  PIN di0[35]
    DIRECTION INPUT ;
    USE SIGNAL ;
    PORT
      LAYER M4 ;
        RECT  0 10.08 0.192 10.104 ;
    END
  END di0[35]
  PIN di0[36]
    DIRECTION INPUT ;
    USE SIGNAL ;
    PORT
      LAYER M4 ;
        RECT  0 10.224 0.192 10.248 ;
    END
  END di0[36]
  PIN di0[37]
    DIRECTION INPUT ;
    USE SIGNAL ;
    PORT
      LAYER M4 ;
        RECT  0 10.416 0.192 10.44 ;
    END
  END di0[37]
  PIN di0[38]
    DIRECTION INPUT ;
    USE SIGNAL ;
    PORT
      LAYER M4 ;
        RECT  0 10.56 0.192 10.584 ;
    END
  END di0[38]
  PIN di0[39]
    DIRECTION INPUT ;
    USE SIGNAL ;
    PORT
      LAYER M4 ;
        RECT  0 10.704 0.192 10.728 ;
    END
  END di0[39]
  PIN di0[3]
    DIRECTION INPUT ;
    USE SIGNAL ;
    PORT
      LAYER M4 ;
        RECT  0 4.896 0.192 4.92 ;
    END
  END di0[3]
  PIN di0[40]
    DIRECTION INPUT ;
    USE SIGNAL ;
    PORT
      LAYER M4 ;
        RECT  0 10.896 0.192 10.92 ;
    END
  END di0[40]
  PIN di0[41]
    DIRECTION INPUT ;
    USE SIGNAL ;
    PORT
      LAYER M4 ;
        RECT  0 11.04 0.192 11.064 ;
    END
  END di0[41]
  PIN di0[42]
    DIRECTION INPUT ;
    USE SIGNAL ;
    PORT
      LAYER M4 ;
        RECT  0 11.184 0.192 11.208 ;
    END
  END di0[42]
  PIN di0[43]
    DIRECTION INPUT ;
    USE SIGNAL ;
    PORT
      LAYER M4 ;
        RECT  0 11.376 0.192 11.4 ;
    END
  END di0[43]
  PIN di0[44]
    DIRECTION INPUT ;
    USE SIGNAL ;
    PORT
      LAYER M4 ;
        RECT  0 11.52 0.192 11.544 ;
    END
  END di0[44]
  PIN di0[45]
    DIRECTION INPUT ;
    USE SIGNAL ;
    PORT
      LAYER M4 ;
        RECT  0 11.664 0.192 11.688 ;
    END
  END di0[45]
  PIN di0[46]
    DIRECTION INPUT ;
    USE SIGNAL ;
    PORT
      LAYER M4 ;
        RECT  0 11.856 0.192 11.88 ;
    END
  END di0[46]
  PIN di0[47]
    DIRECTION INPUT ;
    USE SIGNAL ;
    PORT
      LAYER M4 ;
        RECT  0 12 0.192 12.024 ;
    END
  END di0[47]
  PIN di0[48]
    DIRECTION INPUT ;
    USE SIGNAL ;
    PORT
      LAYER M4 ;
        RECT  0 12.192 0.192 12.216 ;
    END
  END di0[48]
  PIN di0[49]
    DIRECTION INPUT ;
    USE SIGNAL ;
    PORT
      LAYER M4 ;
        RECT  0 12.336 0.192 12.36 ;
    END
  END di0[49]
  PIN di0[4]
    DIRECTION INPUT ;
    USE SIGNAL ;
    PORT
      LAYER M4 ;
        RECT  0 5.04 0.192 5.064 ;
    END
  END di0[4]
  PIN di0[50]
    DIRECTION INPUT ;
    USE SIGNAL ;
    PORT
      LAYER M4 ;
        RECT  0 12.48 0.192 12.504 ;
    END
  END di0[50]
  PIN di0[51]
    DIRECTION INPUT ;
    USE SIGNAL ;
    PORT
      LAYER M4 ;
        RECT  0 12.672 0.192 12.696 ;
    END
  END di0[51]
  PIN di0[52]
    DIRECTION INPUT ;
    USE SIGNAL ;
    PORT
      LAYER M4 ;
        RECT  0 12.816 0.192 12.84 ;
    END
  END di0[52]
  PIN di0[53]
    DIRECTION INPUT ;
    USE SIGNAL ;
    PORT
      LAYER M4 ;
        RECT  0 12.96 0.192 12.984 ;
    END
  END di0[53]
  PIN di0[54]
    DIRECTION INPUT ;
    USE SIGNAL ;
    PORT
      LAYER M4 ;
        RECT  0 13.152 0.192 13.176 ;
    END
  END di0[54]
  PIN di0[55]
    DIRECTION INPUT ;
    USE SIGNAL ;
    PORT
      LAYER M4 ;
        RECT  0 13.296 0.192 13.32 ;
    END
  END di0[55]
  PIN di0[56]
    DIRECTION INPUT ;
    USE SIGNAL ;
    PORT
      LAYER M4 ;
        RECT  0 13.488 0.192 13.512 ;
    END
  END di0[56]
  PIN di0[57]
    DIRECTION INPUT ;
    USE SIGNAL ;
    PORT
      LAYER M4 ;
        RECT  0 13.632 0.192 13.656 ;
    END
  END di0[57]
  PIN di0[58]
    DIRECTION INPUT ;
    USE SIGNAL ;
    PORT
      LAYER M4 ;
        RECT  0 13.776 0.192 13.8 ;
    END
  END di0[58]
  PIN di0[59]
    DIRECTION INPUT ;
    USE SIGNAL ;
    PORT
      LAYER M4 ;
        RECT  0 13.968 0.192 13.992 ;
    END
  END di0[59]
  PIN di0[5]
    DIRECTION INPUT ;
    USE SIGNAL ;
    PORT
      LAYER M4 ;
        RECT  0 5.232 0.192 5.256 ;
    END
  END di0[5]
  PIN di0[60]
    DIRECTION INPUT ;
    USE SIGNAL ;
    PORT
      LAYER M4 ;
        RECT  0 14.112 0.192 14.136 ;
    END
  END di0[60]
  PIN di0[61]
    DIRECTION INPUT ;
    USE SIGNAL ;
    PORT
      LAYER M4 ;
        RECT  0 14.256 0.192 14.28 ;
    END
  END di0[61]
  PIN di0[62]
    DIRECTION INPUT ;
    USE SIGNAL ;
    PORT
      LAYER M4 ;
        RECT  0 14.448 0.192 14.472 ;
    END
  END di0[62]
  PIN di0[63]
    DIRECTION INPUT ;
    USE SIGNAL ;
    PORT
      LAYER M4 ;
        RECT  0 14.592 0.192 14.616 ;
    END
  END di0[63]
  PIN di0[64]
    DIRECTION INPUT ;
    USE SIGNAL ;
    PORT
      LAYER M4 ;
        RECT  0 14.736 0.192 14.76 ;
    END
  END di0[64]
  PIN di0[65]
    DIRECTION INPUT ;
    USE SIGNAL ;
    PORT
      LAYER M4 ;
        RECT  0 14.928 0.192 14.952 ;
    END
  END di0[65]
  PIN di0[66]
    DIRECTION INPUT ;
    USE SIGNAL ;
    PORT
      LAYER M4 ;
        RECT  0 15.072 0.192 15.096 ;
    END
  END di0[66]
  PIN di0[67]
    DIRECTION INPUT ;
    USE SIGNAL ;
    PORT
      LAYER M4 ;
        RECT  0 15.264 0.192 15.288 ;
    END
  END di0[67]
  PIN di0[68]
    DIRECTION INPUT ;
    USE SIGNAL ;
    PORT
      LAYER M4 ;
        RECT  0 15.408 0.192 15.432 ;
    END
  END di0[68]
  PIN di0[69]
    DIRECTION INPUT ;
    USE SIGNAL ;
    PORT
      LAYER M4 ;
        RECT  0 15.552 0.192 15.576 ;
    END
  END di0[69]
  PIN di0[6]
    DIRECTION INPUT ;
    USE SIGNAL ;
    PORT
      LAYER M4 ;
        RECT  0 5.376 0.192 5.4 ;
    END
  END di0[6]
  PIN di0[70]
    DIRECTION INPUT ;
    USE SIGNAL ;
    PORT
      LAYER M4 ;
        RECT  0 15.744 0.192 15.768 ;
    END
  END di0[70]
  PIN di0[71]
    DIRECTION INPUT ;
    USE SIGNAL ;
    PORT
      LAYER M4 ;
        RECT  0 15.888 0.192 15.912 ;
    END
  END di0[71]
  PIN di0[72]
    DIRECTION INPUT ;
    USE SIGNAL ;
    PORT
      LAYER M4 ;
        RECT  0 16.032 0.192 16.056 ;
    END
  END di0[72]
  PIN di0[73]
    DIRECTION INPUT ;
    USE SIGNAL ;
    PORT
      LAYER M4 ;
        RECT  0 16.224 0.192 16.248 ;
    END
  END di0[73]
  PIN di0[74]
    DIRECTION INPUT ;
    USE SIGNAL ;
    PORT
      LAYER M4 ;
        RECT  0 16.368 0.192 16.392 ;
    END
  END di0[74]
  PIN di0[75]
    DIRECTION INPUT ;
    USE SIGNAL ;
    PORT
      LAYER M4 ;
        RECT  0 16.512 0.192 16.536 ;
    END
  END di0[75]
  PIN di0[76]
    DIRECTION INPUT ;
    USE SIGNAL ;
    PORT
      LAYER M4 ;
        RECT  0 16.704 0.192 16.728 ;
    END
  END di0[76]
  PIN di0[77]
    DIRECTION INPUT ;
    USE SIGNAL ;
    PORT
      LAYER M4 ;
        RECT  0 16.848 0.192 16.872 ;
    END
  END di0[77]
  PIN di0[78]
    DIRECTION INPUT ;
    USE SIGNAL ;
    PORT
      LAYER M4 ;
        RECT  0 17.04 0.192 17.064 ;
    END
  END di0[78]
  PIN di0[79]
    DIRECTION INPUT ;
    USE SIGNAL ;
    PORT
      LAYER M4 ;
        RECT  0 17.184 0.192 17.208 ;
    END
  END di0[79]
  PIN di0[7]
    DIRECTION INPUT ;
    USE SIGNAL ;
    PORT
      LAYER M4 ;
        RECT  0 5.568 0.192 5.592 ;
    END
  END di0[7]
  PIN di0[80]
    DIRECTION INPUT ;
    USE SIGNAL ;
    PORT
      LAYER M4 ;
        RECT  0 17.328 0.192 17.352 ;
    END
  END di0[80]
  PIN di0[81]
    DIRECTION INPUT ;
    USE SIGNAL ;
    PORT
      LAYER M4 ;
        RECT  0 17.52 0.192 17.544 ;
    END
  END di0[81]
  PIN di0[82]
    DIRECTION INPUT ;
    USE SIGNAL ;
    PORT
      LAYER M4 ;
        RECT  0 17.664 0.192 17.688 ;
    END
  END di0[82]
  PIN di0[83]
    DIRECTION INPUT ;
    USE SIGNAL ;
    PORT
      LAYER M4 ;
        RECT  0 17.808 0.192 17.832 ;
    END
  END di0[83]
  PIN di0[84]
    DIRECTION INPUT ;
    USE SIGNAL ;
    PORT
      LAYER M4 ;
        RECT  0 18 0.192 18.024 ;
    END
  END di0[84]
  PIN di0[85]
    DIRECTION INPUT ;
    USE SIGNAL ;
    PORT
      LAYER M4 ;
        RECT  0 18.144 0.192 18.168 ;
    END
  END di0[85]
  PIN di0[86]
    DIRECTION INPUT ;
    USE SIGNAL ;
    PORT
      LAYER M4 ;
        RECT  0 18.336 0.192 18.36 ;
    END
  END di0[86]
  PIN di0[87]
    DIRECTION INPUT ;
    USE SIGNAL ;
    PORT
      LAYER M4 ;
        RECT  0 18.48 0.192 18.504 ;
    END
  END di0[87]
  PIN di0[88]
    DIRECTION INPUT ;
    USE SIGNAL ;
    PORT
      LAYER M4 ;
        RECT  0 18.624 0.192 18.648 ;
    END
  END di0[88]
  PIN di0[89]
    DIRECTION INPUT ;
    USE SIGNAL ;
    PORT
      LAYER M4 ;
        RECT  0 18.816 0.192 18.84 ;
    END
  END di0[89]
  PIN di0[8]
    DIRECTION INPUT ;
    USE SIGNAL ;
    PORT
      LAYER M4 ;
        RECT  0 5.712 0.192 5.736 ;
    END
  END di0[8]
  PIN di0[90]
    DIRECTION INPUT ;
    USE SIGNAL ;
    PORT
      LAYER M4 ;
        RECT  0 18.96 0.192 18.984 ;
    END
  END di0[90]
  PIN di0[91]
    DIRECTION INPUT ;
    USE SIGNAL ;
    PORT
      LAYER M4 ;
        RECT  0 19.104 0.192 19.128 ;
    END
  END di0[91]
  PIN di0[92]
    DIRECTION INPUT ;
    USE SIGNAL ;
    PORT
      LAYER M4 ;
        RECT  0 19.296 0.192 19.32 ;
    END
  END di0[92]
  PIN di0[93]
    DIRECTION INPUT ;
    USE SIGNAL ;
    PORT
      LAYER M4 ;
        RECT  0 19.44 0.192 19.464 ;
    END
  END di0[93]
  PIN di0[94]
    DIRECTION INPUT ;
    USE SIGNAL ;
    PORT
      LAYER M4 ;
        RECT  0 19.584 0.192 19.608 ;
    END
  END di0[94]
  PIN di0[95]
    DIRECTION INPUT ;
    USE SIGNAL ;
    PORT
      LAYER M4 ;
        RECT  0 19.776 0.192 19.8 ;
    END
  END di0[95]
  PIN di0[96]
    DIRECTION INPUT ;
    USE SIGNAL ;
    PORT
      LAYER M4 ;
        RECT  0 19.92 0.192 19.944 ;
    END
  END di0[96]
  PIN di0[97]
    DIRECTION INPUT ;
    USE SIGNAL ;
    PORT
      LAYER M4 ;
        RECT  0 20.112 0.192 20.136 ;
    END
  END di0[97]
  PIN di0[98]
    DIRECTION INPUT ;
    USE SIGNAL ;
    PORT
      LAYER M4 ;
        RECT  0 20.256 0.192 20.28 ;
    END
  END di0[98]
  PIN di0[99]
    DIRECTION INPUT ;
    USE SIGNAL ;
    PORT
      LAYER M4 ;
        RECT  0 20.4 0.192 20.424 ;
    END
  END di0[99]
  PIN di0[9]
    DIRECTION INPUT ;
    USE SIGNAL ;
    PORT
      LAYER M4 ;
        RECT  0 5.856 0.192 5.88 ;
    END
  END di0[9]
  PIN do0[0]
    DIRECTION OUTPUT ;
    USE SIGNAL ;
    PORT
      LAYER M4 ;
        RECT  36.528 4.416 36.72 4.44 ;
    END
  END do0[0]
  PIN do0[100]
    DIRECTION OUTPUT ;
    USE SIGNAL ;
    PORT
      LAYER M4 ;
        RECT  36.528 20.592 36.72 20.616 ;
    END
  END do0[100]
  PIN do0[101]
    DIRECTION OUTPUT ;
    USE SIGNAL ;
    PORT
      LAYER M4 ;
        RECT  36.528 20.736 36.72 20.76 ;
    END
  END do0[101]
  PIN do0[102]
    DIRECTION OUTPUT ;
    USE SIGNAL ;
    PORT
      LAYER M4 ;
        RECT  36.528 20.88 36.72 20.904 ;
    END
  END do0[102]
  PIN do0[103]
    DIRECTION OUTPUT ;
    USE SIGNAL ;
    PORT
      LAYER M4 ;
        RECT  36.528 21.072 36.72 21.096 ;
    END
  END do0[103]
  PIN do0[104]
    DIRECTION OUTPUT ;
    USE SIGNAL ;
    PORT
      LAYER M4 ;
        RECT  36.528 21.216 36.72 21.24 ;
    END
  END do0[104]
  PIN do0[105]
    DIRECTION OUTPUT ;
    USE SIGNAL ;
    PORT
      LAYER M4 ;
        RECT  36.528 21.408 36.72 21.432 ;
    END
  END do0[105]
  PIN do0[106]
    DIRECTION OUTPUT ;
    USE SIGNAL ;
    PORT
      LAYER M4 ;
        RECT  36.528 21.552 36.72 21.576 ;
    END
  END do0[106]
  PIN do0[107]
    DIRECTION OUTPUT ;
    USE SIGNAL ;
    PORT
      LAYER M4 ;
        RECT  36.528 21.696 36.72 21.72 ;
    END
  END do0[107]
  PIN do0[108]
    DIRECTION OUTPUT ;
    USE SIGNAL ;
    PORT
      LAYER M4 ;
        RECT  36.528 21.888 36.72 21.912 ;
    END
  END do0[108]
  PIN do0[109]
    DIRECTION OUTPUT ;
    USE SIGNAL ;
    PORT
      LAYER M4 ;
        RECT  36.528 22.032 36.72 22.056 ;
    END
  END do0[109]
  PIN do0[10]
    DIRECTION OUTPUT ;
    USE SIGNAL ;
    PORT
      LAYER M4 ;
        RECT  36.528 6.048 36.72 6.072 ;
    END
  END do0[10]
  PIN do0[110]
    DIRECTION OUTPUT ;
    USE SIGNAL ;
    PORT
      LAYER M4 ;
        RECT  36.528 22.176 36.72 22.2 ;
    END
  END do0[110]
  PIN do0[111]
    DIRECTION OUTPUT ;
    USE SIGNAL ;
    PORT
      LAYER M4 ;
        RECT  36.528 22.368 36.72 22.392 ;
    END
  END do0[111]
  PIN do0[112]
    DIRECTION OUTPUT ;
    USE SIGNAL ;
    PORT
      LAYER M4 ;
        RECT  36.528 22.512 36.72 22.536 ;
    END
  END do0[112]
  PIN do0[113]
    DIRECTION OUTPUT ;
    USE SIGNAL ;
    PORT
      LAYER M4 ;
        RECT  36.528 22.656 36.72 22.68 ;
    END
  END do0[113]
  PIN do0[114]
    DIRECTION OUTPUT ;
    USE SIGNAL ;
    PORT
      LAYER M4 ;
        RECT  36.528 22.848 36.72 22.872 ;
    END
  END do0[114]
  PIN do0[115]
    DIRECTION OUTPUT ;
    USE SIGNAL ;
    PORT
      LAYER M4 ;
        RECT  36.528 22.992 36.72 23.016 ;
    END
  END do0[115]
  PIN do0[116]
    DIRECTION OUTPUT ;
    USE SIGNAL ;
    PORT
      LAYER M4 ;
        RECT  36.528 23.184 36.72 23.208 ;
    END
  END do0[116]
  PIN do0[117]
    DIRECTION OUTPUT ;
    USE SIGNAL ;
    PORT
      LAYER M4 ;
        RECT  36.528 23.328 36.72 23.352 ;
    END
  END do0[117]
  PIN do0[118]
    DIRECTION OUTPUT ;
    USE SIGNAL ;
    PORT
      LAYER M4 ;
        RECT  36.528 23.472 36.72 23.496 ;
    END
  END do0[118]
  PIN do0[119]
    DIRECTION OUTPUT ;
    USE SIGNAL ;
    PORT
      LAYER M4 ;
        RECT  36.528 23.664 36.72 23.688 ;
    END
  END do0[119]
  PIN do0[11]
    DIRECTION OUTPUT ;
    USE SIGNAL ;
    PORT
      LAYER M4 ;
        RECT  36.528 6.192 36.72 6.216 ;
    END
  END do0[11]
  PIN do0[120]
    DIRECTION OUTPUT ;
    USE SIGNAL ;
    PORT
      LAYER M4 ;
        RECT  36.528 23.808 36.72 23.832 ;
    END
  END do0[120]
  PIN do0[121]
    DIRECTION OUTPUT ;
    USE SIGNAL ;
    PORT
      LAYER M4 ;
        RECT  36.528 23.952 36.72 23.976 ;
    END
  END do0[121]
  PIN do0[122]
    DIRECTION OUTPUT ;
    USE SIGNAL ;
    PORT
      LAYER M4 ;
        RECT  36.528 24.144 36.72 24.168 ;
    END
  END do0[122]
  PIN do0[123]
    DIRECTION OUTPUT ;
    USE SIGNAL ;
    PORT
      LAYER M4 ;
        RECT  36.528 24.288 36.72 24.312 ;
    END
  END do0[123]
  PIN do0[124]
    DIRECTION OUTPUT ;
    USE SIGNAL ;
    PORT
      LAYER M4 ;
        RECT  36.528 24.432 36.72 24.456 ;
    END
  END do0[124]
  PIN do0[125]
    DIRECTION OUTPUT ;
    USE SIGNAL ;
    PORT
      LAYER M4 ;
        RECT  36.528 24.624 36.72 24.648 ;
    END
  END do0[125]
  PIN do0[126]
    DIRECTION OUTPUT ;
    USE SIGNAL ;
    PORT
      LAYER M4 ;
        RECT  36.528 24.768 36.72 24.792 ;
    END
  END do0[126]
  PIN do0[127]
    DIRECTION OUTPUT ;
    USE SIGNAL ;
    PORT
      LAYER M4 ;
        RECT  36.528 24.96 36.72 24.984 ;
    END
  END do0[127]
  PIN do0[128]
    DIRECTION OUTPUT ;
    USE SIGNAL ;
    PORT
      LAYER M4 ;
        RECT  36.528 25.104 36.72 25.128 ;
    END
  END do0[128]
  PIN do0[129]
    DIRECTION OUTPUT ;
    USE SIGNAL ;
    PORT
      LAYER M4 ;
        RECT  36.528 25.248 36.72 25.272 ;
    END
  END do0[129]
  PIN do0[12]
    DIRECTION OUTPUT ;
    USE SIGNAL ;
    PORT
      LAYER M4 ;
        RECT  36.528 6.336 36.72 6.36 ;
    END
  END do0[12]
  PIN do0[130]
    DIRECTION OUTPUT ;
    USE SIGNAL ;
    PORT
      LAYER M4 ;
        RECT  36.528 25.44 36.72 25.464 ;
    END
  END do0[130]
  PIN do0[131]
    DIRECTION OUTPUT ;
    USE SIGNAL ;
    PORT
      LAYER M4 ;
        RECT  36.528 25.584 36.72 25.608 ;
    END
  END do0[131]
  PIN do0[132]
    DIRECTION OUTPUT ;
    USE SIGNAL ;
    PORT
      LAYER M4 ;
        RECT  36.528 25.728 36.72 25.752 ;
    END
  END do0[132]
  PIN do0[133]
    DIRECTION OUTPUT ;
    USE SIGNAL ;
    PORT
      LAYER M4 ;
        RECT  36.528 25.92 36.72 25.944 ;
    END
  END do0[133]
  PIN do0[134]
    DIRECTION OUTPUT ;
    USE SIGNAL ;
    PORT
      LAYER M4 ;
        RECT  36.528 26.064 36.72 26.088 ;
    END
  END do0[134]
  PIN do0[135]
    DIRECTION OUTPUT ;
    USE SIGNAL ;
    PORT
      LAYER M4 ;
        RECT  36.528 26.256 36.72 26.28 ;
    END
  END do0[135]
  PIN do0[136]
    DIRECTION OUTPUT ;
    USE SIGNAL ;
    PORT
      LAYER M4 ;
        RECT  36.528 26.4 36.72 26.424 ;
    END
  END do0[136]
  PIN do0[137]
    DIRECTION OUTPUT ;
    USE SIGNAL ;
    PORT
      LAYER M4 ;
        RECT  36.528 26.544 36.72 26.568 ;
    END
  END do0[137]
  PIN do0[138]
    DIRECTION OUTPUT ;
    USE SIGNAL ;
    PORT
      LAYER M4 ;
        RECT  36.528 26.736 36.72 26.76 ;
    END
  END do0[138]
  PIN do0[139]
    DIRECTION OUTPUT ;
    USE SIGNAL ;
    PORT
      LAYER M4 ;
        RECT  36.528 26.88 36.72 26.904 ;
    END
  END do0[139]
  PIN do0[13]
    DIRECTION OUTPUT ;
    USE SIGNAL ;
    PORT
      LAYER M4 ;
        RECT  36.528 6.528 36.72 6.552 ;
    END
  END do0[13]
  PIN do0[140]
    DIRECTION OUTPUT ;
    USE SIGNAL ;
    PORT
      LAYER M4 ;
        RECT  36.528 27.024 36.72 27.048 ;
    END
  END do0[140]
  PIN do0[141]
    DIRECTION OUTPUT ;
    USE SIGNAL ;
    PORT
      LAYER M4 ;
        RECT  36.528 27.216 36.72 27.24 ;
    END
  END do0[141]
  PIN do0[142]
    DIRECTION OUTPUT ;
    USE SIGNAL ;
    PORT
      LAYER M4 ;
        RECT  36.528 27.36 36.72 27.384 ;
    END
  END do0[142]
  PIN do0[143]
    DIRECTION OUTPUT ;
    USE SIGNAL ;
    PORT
      LAYER M4 ;
        RECT  36.528 27.504 36.72 27.528 ;
    END
  END do0[143]
  PIN do0[144]
    DIRECTION OUTPUT ;
    USE SIGNAL ;
    PORT
      LAYER M4 ;
        RECT  36.528 27.696 36.72 27.72 ;
    END
  END do0[144]
  PIN do0[145]
    DIRECTION OUTPUT ;
    USE SIGNAL ;
    PORT
      LAYER M4 ;
        RECT  36.528 27.84 36.72 27.864 ;
    END
  END do0[145]
  PIN do0[146]
    DIRECTION OUTPUT ;
    USE SIGNAL ;
    PORT
      LAYER M4 ;
        RECT  36.528 28.032 36.72 28.056 ;
    END
  END do0[146]
  PIN do0[147]
    DIRECTION OUTPUT ;
    USE SIGNAL ;
    PORT
      LAYER M4 ;
        RECT  36.528 28.176 36.72 28.2 ;
    END
  END do0[147]
  PIN do0[148]
    DIRECTION OUTPUT ;
    USE SIGNAL ;
    PORT
      LAYER M4 ;
        RECT  36.528 28.32 36.72 28.344 ;
    END
  END do0[148]
  PIN do0[149]
    DIRECTION OUTPUT ;
    USE SIGNAL ;
    PORT
      LAYER M4 ;
        RECT  36.528 28.512 36.72 28.536 ;
    END
  END do0[149]
  PIN do0[14]
    DIRECTION OUTPUT ;
    USE SIGNAL ;
    PORT
      LAYER M4 ;
        RECT  36.528 6.672 36.72 6.696 ;
    END
  END do0[14]
  PIN do0[150]
    DIRECTION OUTPUT ;
    USE SIGNAL ;
    PORT
      LAYER M4 ;
        RECT  36.528 28.656 36.72 28.68 ;
    END
  END do0[150]
  PIN do0[151]
    DIRECTION OUTPUT ;
    USE SIGNAL ;
    PORT
      LAYER M4 ;
        RECT  36.528 28.8 36.72 28.824 ;
    END
  END do0[151]
  PIN do0[152]
    DIRECTION OUTPUT ;
    USE SIGNAL ;
    PORT
      LAYER M4 ;
        RECT  36.528 28.992 36.72 29.016 ;
    END
  END do0[152]
  PIN do0[153]
    DIRECTION OUTPUT ;
    USE SIGNAL ;
    PORT
      LAYER M4 ;
        RECT  36.528 29.136 36.72 29.16 ;
    END
  END do0[153]
  PIN do0[154]
    DIRECTION OUTPUT ;
    USE SIGNAL ;
    PORT
      LAYER M4 ;
        RECT  36.528 29.328 36.72 29.352 ;
    END
  END do0[154]
  PIN do0[155]
    DIRECTION OUTPUT ;
    USE SIGNAL ;
    PORT
      LAYER M4 ;
        RECT  36.528 29.472 36.72 29.496 ;
    END
  END do0[155]
  PIN do0[156]
    DIRECTION OUTPUT ;
    USE SIGNAL ;
    PORT
      LAYER M4 ;
        RECT  36.528 29.616 36.72 29.64 ;
    END
  END do0[156]
  PIN do0[157]
    DIRECTION OUTPUT ;
    USE SIGNAL ;
    PORT
      LAYER M4 ;
        RECT  36.528 29.808 36.72 29.832 ;
    END
  END do0[157]
  PIN do0[158]
    DIRECTION OUTPUT ;
    USE SIGNAL ;
    PORT
      LAYER M4 ;
        RECT  36.528 29.952 36.72 29.976 ;
    END
  END do0[158]
  PIN do0[159]
    DIRECTION OUTPUT ;
    USE SIGNAL ;
    PORT
      LAYER M4 ;
        RECT  36.528 30.096 36.72 30.12 ;
    END
  END do0[159]
  PIN do0[15]
    DIRECTION OUTPUT ;
    USE SIGNAL ;
    PORT
      LAYER M4 ;
        RECT  36.528 6.816 36.72 6.84 ;
    END
  END do0[15]
  PIN do0[160]
    DIRECTION OUTPUT ;
    USE SIGNAL ;
    PORT
      LAYER M4 ;
        RECT  36.528 30.288 36.72 30.312 ;
    END
  END do0[160]
  PIN do0[161]
    DIRECTION OUTPUT ;
    USE SIGNAL ;
    PORT
      LAYER M4 ;
        RECT  36.528 30.432 36.72 30.456 ;
    END
  END do0[161]
  PIN do0[162]
    DIRECTION OUTPUT ;
    USE SIGNAL ;
    PORT
      LAYER M4 ;
        RECT  36.528 30.576 36.72 30.6 ;
    END
  END do0[162]
  PIN do0[163]
    DIRECTION OUTPUT ;
    USE SIGNAL ;
    PORT
      LAYER M4 ;
        RECT  36.528 30.768 36.72 30.792 ;
    END
  END do0[163]
  PIN do0[164]
    DIRECTION OUTPUT ;
    USE SIGNAL ;
    PORT
      LAYER M4 ;
        RECT  36.528 30.912 36.72 30.936 ;
    END
  END do0[164]
  PIN do0[165]
    DIRECTION OUTPUT ;
    USE SIGNAL ;
    PORT
      LAYER M4 ;
        RECT  36.528 31.104 36.72 31.128 ;
    END
  END do0[165]
  PIN do0[166]
    DIRECTION OUTPUT ;
    USE SIGNAL ;
    PORT
      LAYER M4 ;
        RECT  36.528 31.248 36.72 31.272 ;
    END
  END do0[166]
  PIN do0[167]
    DIRECTION OUTPUT ;
    USE SIGNAL ;
    PORT
      LAYER M4 ;
        RECT  36.528 31.392 36.72 31.416 ;
    END
  END do0[167]
  PIN do0[168]
    DIRECTION OUTPUT ;
    USE SIGNAL ;
    PORT
      LAYER M4 ;
        RECT  36.528 31.584 36.72 31.608 ;
    END
  END do0[168]
  PIN do0[169]
    DIRECTION OUTPUT ;
    USE SIGNAL ;
    PORT
      LAYER M4 ;
        RECT  36.528 31.728 36.72 31.752 ;
    END
  END do0[169]
  PIN do0[16]
    DIRECTION OUTPUT ;
    USE SIGNAL ;
    PORT
      LAYER M4 ;
        RECT  36.528 7.008 36.72 7.032 ;
    END
  END do0[16]
  PIN do0[170]
    DIRECTION OUTPUT ;
    USE SIGNAL ;
    PORT
      LAYER M4 ;
        RECT  36.528 31.872 36.72 31.896 ;
    END
  END do0[170]
  PIN do0[171]
    DIRECTION OUTPUT ;
    USE SIGNAL ;
    PORT
      LAYER M4 ;
        RECT  36.528 32.064 36.72 32.088 ;
    END
  END do0[171]
  PIN do0[172]
    DIRECTION OUTPUT ;
    USE SIGNAL ;
    PORT
      LAYER M4 ;
        RECT  36.528 32.208 36.72 32.232 ;
    END
  END do0[172]
  PIN do0[173]
    DIRECTION OUTPUT ;
    USE SIGNAL ;
    PORT
      LAYER M4 ;
        RECT  36.528 32.352 36.72 32.376 ;
    END
  END do0[173]
  PIN do0[174]
    DIRECTION OUTPUT ;
    USE SIGNAL ;
    PORT
      LAYER M4 ;
        RECT  36.528 32.544 36.72 32.568 ;
    END
  END do0[174]
  PIN do0[175]
    DIRECTION OUTPUT ;
    USE SIGNAL ;
    PORT
      LAYER M4 ;
        RECT  36.528 32.688 36.72 32.712 ;
    END
  END do0[175]
  PIN do0[176]
    DIRECTION OUTPUT ;
    USE SIGNAL ;
    PORT
      LAYER M4 ;
        RECT  36.528 32.88 36.72 32.904 ;
    END
  END do0[176]
  PIN do0[177]
    DIRECTION OUTPUT ;
    USE SIGNAL ;
    PORT
      LAYER M4 ;
        RECT  36.528 33.024 36.72 33.048 ;
    END
  END do0[177]
  PIN do0[178]
    DIRECTION OUTPUT ;
    USE SIGNAL ;
    PORT
      LAYER M4 ;
        RECT  36.528 33.168 36.72 33.192 ;
    END
  END do0[178]
  PIN do0[179]
    DIRECTION OUTPUT ;
    USE SIGNAL ;
    PORT
      LAYER M4 ;
        RECT  36.528 33.36 36.72 33.384 ;
    END
  END do0[179]
  PIN do0[17]
    DIRECTION OUTPUT ;
    USE SIGNAL ;
    PORT
      LAYER M4 ;
        RECT  36.528 7.152 36.72 7.176 ;
    END
  END do0[17]
  PIN do0[180]
    DIRECTION OUTPUT ;
    USE SIGNAL ;
    PORT
      LAYER M4 ;
        RECT  36.528 33.504 36.72 33.528 ;
    END
  END do0[180]
  PIN do0[181]
    DIRECTION OUTPUT ;
    USE SIGNAL ;
    PORT
      LAYER M4 ;
        RECT  36.528 33.648 36.72 33.672 ;
    END
  END do0[181]
  PIN do0[182]
    DIRECTION OUTPUT ;
    USE SIGNAL ;
    PORT
      LAYER M4 ;
        RECT  36.528 33.84 36.72 33.864 ;
    END
  END do0[182]
  PIN do0[183]
    DIRECTION OUTPUT ;
    USE SIGNAL ;
    PORT
      LAYER M4 ;
        RECT  36.528 33.984 36.72 34.008 ;
    END
  END do0[183]
  PIN do0[184]
    DIRECTION OUTPUT ;
    USE SIGNAL ;
    PORT
      LAYER M4 ;
        RECT  36.528 34.176 36.72 34.2 ;
    END
  END do0[184]
  PIN do0[185]
    DIRECTION OUTPUT ;
    USE SIGNAL ;
    PORT
      LAYER M4 ;
        RECT  36.528 34.32 36.72 34.344 ;
    END
  END do0[185]
  PIN do0[186]
    DIRECTION OUTPUT ;
    USE SIGNAL ;
    PORT
      LAYER M4 ;
        RECT  36.528 34.464 36.72 34.488 ;
    END
  END do0[186]
  PIN do0[187]
    DIRECTION OUTPUT ;
    USE SIGNAL ;
    PORT
      LAYER M4 ;
        RECT  36.528 34.656 36.72 34.68 ;
    END
  END do0[187]
  PIN do0[188]
    DIRECTION OUTPUT ;
    USE SIGNAL ;
    PORT
      LAYER M4 ;
        RECT  36.528 34.8 36.72 34.824 ;
    END
  END do0[188]
  PIN do0[189]
    DIRECTION OUTPUT ;
    USE SIGNAL ;
    PORT
      LAYER M4 ;
        RECT  36.528 34.944 36.72 34.968 ;
    END
  END do0[189]
  PIN do0[18]
    DIRECTION OUTPUT ;
    USE SIGNAL ;
    PORT
      LAYER M4 ;
        RECT  36.528 7.344 36.72 7.368 ;
    END
  END do0[18]
  PIN do0[190]
    DIRECTION OUTPUT ;
    USE SIGNAL ;
    PORT
      LAYER M4 ;
        RECT  36.528 35.136 36.72 35.16 ;
    END
  END do0[190]
  PIN do0[191]
    DIRECTION OUTPUT ;
    USE SIGNAL ;
    PORT
      LAYER M4 ;
        RECT  36.528 35.28 36.72 35.304 ;
    END
  END do0[191]
  PIN do0[192]
    DIRECTION OUTPUT ;
    USE SIGNAL ;
    PORT
      LAYER M4 ;
        RECT  36.528 35.424 36.72 35.448 ;
    END
  END do0[192]
  PIN do0[193]
    DIRECTION OUTPUT ;
    USE SIGNAL ;
    PORT
      LAYER M4 ;
        RECT  36.528 35.616 36.72 35.64 ;
    END
  END do0[193]
  PIN do0[194]
    DIRECTION OUTPUT ;
    USE SIGNAL ;
    PORT
      LAYER M4 ;
        RECT  36.528 35.76 36.72 35.784 ;
    END
  END do0[194]
  PIN do0[195]
    DIRECTION OUTPUT ;
    USE SIGNAL ;
    PORT
      LAYER M4 ;
        RECT  36.528 35.952 36.72 35.976 ;
    END
  END do0[195]
  PIN do0[196]
    DIRECTION OUTPUT ;
    USE SIGNAL ;
    PORT
      LAYER M4 ;
        RECT  36.528 36.096 36.72 36.12 ;
    END
  END do0[196]
  PIN do0[197]
    DIRECTION OUTPUT ;
    USE SIGNAL ;
    PORT
      LAYER M4 ;
        RECT  36.528 36.24 36.72 36.264 ;
    END
  END do0[197]
  PIN do0[198]
    DIRECTION OUTPUT ;
    USE SIGNAL ;
    PORT
      LAYER M4 ;
        RECT  36.528 36.432 36.72 36.456 ;
    END
  END do0[198]
  PIN do0[199]
    DIRECTION OUTPUT ;
    USE SIGNAL ;
    PORT
      LAYER M4 ;
        RECT  36.528 36.576 36.72 36.6 ;
    END
  END do0[199]
  PIN do0[19]
    DIRECTION OUTPUT ;
    USE SIGNAL ;
    PORT
      LAYER M4 ;
        RECT  36.528 7.488 36.72 7.512 ;
    END
  END do0[19]
  PIN do0[1]
    DIRECTION OUTPUT ;
    USE SIGNAL ;
    PORT
      LAYER M4 ;
        RECT  36.528 4.56 36.72 4.584 ;
    END
  END do0[1]
  PIN do0[200]
    DIRECTION OUTPUT ;
    USE SIGNAL ;
    PORT
      LAYER M4 ;
        RECT  36.528 36.72 36.72 36.744 ;
    END
  END do0[200]
  PIN do0[201]
    DIRECTION OUTPUT ;
    USE SIGNAL ;
    PORT
      LAYER M4 ;
        RECT  36.528 36.912 36.72 36.936 ;
    END
  END do0[201]
  PIN do0[202]
    DIRECTION OUTPUT ;
    USE SIGNAL ;
    PORT
      LAYER M4 ;
        RECT  36.528 37.056 36.72 37.08 ;
    END
  END do0[202]
  PIN do0[203]
    DIRECTION OUTPUT ;
    USE SIGNAL ;
    PORT
      LAYER M4 ;
        RECT  36.528 37.248 36.72 37.272 ;
    END
  END do0[203]
  PIN do0[204]
    DIRECTION OUTPUT ;
    USE SIGNAL ;
    PORT
      LAYER M4 ;
        RECT  36.528 37.392 36.72 37.416 ;
    END
  END do0[204]
  PIN do0[205]
    DIRECTION OUTPUT ;
    USE SIGNAL ;
    PORT
      LAYER M4 ;
        RECT  36.528 37.536 36.72 37.56 ;
    END
  END do0[205]
  PIN do0[206]
    DIRECTION OUTPUT ;
    USE SIGNAL ;
    PORT
      LAYER M4 ;
        RECT  36.528 37.728 36.72 37.752 ;
    END
  END do0[206]
  PIN do0[207]
    DIRECTION OUTPUT ;
    USE SIGNAL ;
    PORT
      LAYER M4 ;
        RECT  36.528 37.872 36.72 37.896 ;
    END
  END do0[207]
  PIN do0[208]
    DIRECTION OUTPUT ;
    USE SIGNAL ;
    PORT
      LAYER M4 ;
        RECT  36.528 38.016 36.72 38.04 ;
    END
  END do0[208]
  PIN do0[209]
    DIRECTION OUTPUT ;
    USE SIGNAL ;
    PORT
      LAYER M4 ;
        RECT  36.528 38.208 36.72 38.232 ;
    END
  END do0[209]
  PIN do0[20]
    DIRECTION OUTPUT ;
    USE SIGNAL ;
    PORT
      LAYER M4 ;
        RECT  36.528 7.632 36.72 7.656 ;
    END
  END do0[20]
  PIN do0[210]
    DIRECTION OUTPUT ;
    USE SIGNAL ;
    PORT
      LAYER M4 ;
        RECT  36.528 38.352 36.72 38.376 ;
    END
  END do0[210]
  PIN do0[211]
    DIRECTION OUTPUT ;
    USE SIGNAL ;
    PORT
      LAYER M4 ;
        RECT  36.528 38.496 36.72 38.52 ;
    END
  END do0[211]
  PIN do0[212]
    DIRECTION OUTPUT ;
    USE SIGNAL ;
    PORT
      LAYER M4 ;
        RECT  36.528 38.688 36.72 38.712 ;
    END
  END do0[212]
  PIN do0[213]
    DIRECTION OUTPUT ;
    USE SIGNAL ;
    PORT
      LAYER M4 ;
        RECT  36.528 38.832 36.72 38.856 ;
    END
  END do0[213]
  PIN do0[214]
    DIRECTION OUTPUT ;
    USE SIGNAL ;
    PORT
      LAYER M4 ;
        RECT  36.528 39.024 36.72 39.048 ;
    END
  END do0[214]
  PIN do0[215]
    DIRECTION OUTPUT ;
    USE SIGNAL ;
    PORT
      LAYER M4 ;
        RECT  36.528 39.168 36.72 39.192 ;
    END
  END do0[215]
  PIN do0[216]
    DIRECTION OUTPUT ;
    USE SIGNAL ;
    PORT
      LAYER M4 ;
        RECT  36.528 39.312 36.72 39.336 ;
    END
  END do0[216]
  PIN do0[217]
    DIRECTION OUTPUT ;
    USE SIGNAL ;
    PORT
      LAYER M4 ;
        RECT  36.528 39.504 36.72 39.528 ;
    END
  END do0[217]
  PIN do0[218]
    DIRECTION OUTPUT ;
    USE SIGNAL ;
    PORT
      LAYER M4 ;
        RECT  36.528 39.648 36.72 39.672 ;
    END
  END do0[218]
  PIN do0[219]
    DIRECTION OUTPUT ;
    USE SIGNAL ;
    PORT
      LAYER M4 ;
        RECT  36.528 39.792 36.72 39.816 ;
    END
  END do0[219]
  PIN do0[21]
    DIRECTION OUTPUT ;
    USE SIGNAL ;
    PORT
      LAYER M4 ;
        RECT  36.528 7.824 36.72 7.848 ;
    END
  END do0[21]
  PIN do0[220]
    DIRECTION OUTPUT ;
    USE SIGNAL ;
    PORT
      LAYER M4 ;
        RECT  36.528 39.984 36.72 40.008 ;
    END
  END do0[220]
  PIN do0[221]
    DIRECTION OUTPUT ;
    USE SIGNAL ;
    PORT
      LAYER M4 ;
        RECT  36.528 40.128 36.72 40.152 ;
    END
  END do0[221]
  PIN do0[222]
    DIRECTION OUTPUT ;
    USE SIGNAL ;
    PORT
      LAYER M4 ;
        RECT  36.528 40.272 36.72 40.296 ;
    END
  END do0[222]
  PIN do0[223]
    DIRECTION OUTPUT ;
    USE SIGNAL ;
    PORT
      LAYER M4 ;
        RECT  36.528 40.464 36.72 40.488 ;
    END
  END do0[223]
  PIN do0[224]
    DIRECTION OUTPUT ;
    USE SIGNAL ;
    PORT
      LAYER M4 ;
        RECT  36.528 40.608 36.72 40.632 ;
    END
  END do0[224]
  PIN do0[225]
    DIRECTION OUTPUT ;
    USE SIGNAL ;
    PORT
      LAYER M4 ;
        RECT  36.528 40.8 36.72 40.824 ;
    END
  END do0[225]
  PIN do0[226]
    DIRECTION OUTPUT ;
    USE SIGNAL ;
    PORT
      LAYER M4 ;
        RECT  36.528 40.944 36.72 40.968 ;
    END
  END do0[226]
  PIN do0[227]
    DIRECTION OUTPUT ;
    USE SIGNAL ;
    PORT
      LAYER M4 ;
        RECT  36.528 41.088 36.72 41.112 ;
    END
  END do0[227]
  PIN do0[228]
    DIRECTION OUTPUT ;
    USE SIGNAL ;
    PORT
      LAYER M4 ;
        RECT  36.528 41.28 36.72 41.304 ;
    END
  END do0[228]
  PIN do0[229]
    DIRECTION OUTPUT ;
    USE SIGNAL ;
    PORT
      LAYER M4 ;
        RECT  36.528 41.424 36.72 41.448 ;
    END
  END do0[229]
  PIN do0[22]
    DIRECTION OUTPUT ;
    USE SIGNAL ;
    PORT
      LAYER M4 ;
        RECT  36.528 7.968 36.72 7.992 ;
    END
  END do0[22]
  PIN do0[230]
    DIRECTION OUTPUT ;
    USE SIGNAL ;
    PORT
      LAYER M4 ;
        RECT  36.528 41.568 36.72 41.592 ;
    END
  END do0[230]
  PIN do0[231]
    DIRECTION OUTPUT ;
    USE SIGNAL ;
    PORT
      LAYER M4 ;
        RECT  36.528 41.76 36.72 41.784 ;
    END
  END do0[231]
  PIN do0[232]
    DIRECTION OUTPUT ;
    USE SIGNAL ;
    PORT
      LAYER M4 ;
        RECT  36.528 41.904 36.72 41.928 ;
    END
  END do0[232]
  PIN do0[233]
    DIRECTION OUTPUT ;
    USE SIGNAL ;
    PORT
      LAYER M4 ;
        RECT  36.528 42.096 36.72 42.12 ;
    END
  END do0[233]
  PIN do0[234]
    DIRECTION OUTPUT ;
    USE SIGNAL ;
    PORT
      LAYER M4 ;
        RECT  36.528 42.24 36.72 42.264 ;
    END
  END do0[234]
  PIN do0[235]
    DIRECTION OUTPUT ;
    USE SIGNAL ;
    PORT
      LAYER M4 ;
        RECT  36.528 42.384 36.72 42.408 ;
    END
  END do0[235]
  PIN do0[236]
    DIRECTION OUTPUT ;
    USE SIGNAL ;
    PORT
      LAYER M4 ;
        RECT  36.528 42.576 36.72 42.6 ;
    END
  END do0[236]
  PIN do0[237]
    DIRECTION OUTPUT ;
    USE SIGNAL ;
    PORT
      LAYER M4 ;
        RECT  36.528 42.72 36.72 42.744 ;
    END
  END do0[237]
  PIN do0[238]
    DIRECTION OUTPUT ;
    USE SIGNAL ;
    PORT
      LAYER M4 ;
        RECT  36.528 42.864 36.72 42.888 ;
    END
  END do0[238]
  PIN do0[239]
    DIRECTION OUTPUT ;
    USE SIGNAL ;
    PORT
      LAYER M4 ;
        RECT  36.528 43.056 36.72 43.08 ;
    END
  END do0[239]
  PIN do0[23]
    DIRECTION OUTPUT ;
    USE SIGNAL ;
    PORT
      LAYER M4 ;
        RECT  36.528 8.112 36.72 8.136 ;
    END
  END do0[23]
  PIN do0[240]
    DIRECTION OUTPUT ;
    USE SIGNAL ;
    PORT
      LAYER M4 ;
        RECT  36.528 43.2 36.72 43.224 ;
    END
  END do0[240]
  PIN do0[241]
    DIRECTION OUTPUT ;
    USE SIGNAL ;
    PORT
      LAYER M4 ;
        RECT  36.528 43.344 36.72 43.368 ;
    END
  END do0[241]
  PIN do0[242]
    DIRECTION OUTPUT ;
    USE SIGNAL ;
    PORT
      LAYER M4 ;
        RECT  36.528 43.536 36.72 43.56 ;
    END
  END do0[242]
  PIN do0[243]
    DIRECTION OUTPUT ;
    USE SIGNAL ;
    PORT
      LAYER M4 ;
        RECT  36.528 43.68 36.72 43.704 ;
    END
  END do0[243]
  PIN do0[244]
    DIRECTION OUTPUT ;
    USE SIGNAL ;
    PORT
      LAYER M4 ;
        RECT  36.528 43.872 36.72 43.896 ;
    END
  END do0[244]
  PIN do0[245]
    DIRECTION OUTPUT ;
    USE SIGNAL ;
    PORT
      LAYER M4 ;
        RECT  36.528 44.016 36.72 44.04 ;
    END
  END do0[245]
  PIN do0[246]
    DIRECTION OUTPUT ;
    USE SIGNAL ;
    PORT
      LAYER M4 ;
        RECT  36.528 44.16 36.72 44.184 ;
    END
  END do0[246]
  PIN do0[247]
    DIRECTION OUTPUT ;
    USE SIGNAL ;
    PORT
      LAYER M4 ;
        RECT  36.528 44.352 36.72 44.376 ;
    END
  END do0[247]
  PIN do0[248]
    DIRECTION OUTPUT ;
    USE SIGNAL ;
    PORT
      LAYER M4 ;
        RECT  36.528 44.496 36.72 44.52 ;
    END
  END do0[248]
  PIN do0[249]
    DIRECTION OUTPUT ;
    USE SIGNAL ;
    PORT
      LAYER M4 ;
        RECT  36.528 44.64 36.72 44.664 ;
    END
  END do0[249]
  PIN do0[24]
    DIRECTION OUTPUT ;
    USE SIGNAL ;
    PORT
      LAYER M4 ;
        RECT  36.528 8.304 36.72 8.328 ;
    END
  END do0[24]
  PIN do0[250]
    DIRECTION OUTPUT ;
    USE SIGNAL ;
    PORT
      LAYER M4 ;
        RECT  36.528 44.832 36.72 44.856 ;
    END
  END do0[250]
  PIN do0[251]
    DIRECTION OUTPUT ;
    USE SIGNAL ;
    PORT
      LAYER M4 ;
        RECT  36.528 44.976 36.72 45 ;
    END
  END do0[251]
  PIN do0[252]
    DIRECTION OUTPUT ;
    USE SIGNAL ;
    PORT
      LAYER M4 ;
        RECT  36.528 45.168 36.72 45.192 ;
    END
  END do0[252]
  PIN do0[253]
    DIRECTION OUTPUT ;
    USE SIGNAL ;
    PORT
      LAYER M4 ;
        RECT  36.528 45.312 36.72 45.336 ;
    END
  END do0[253]
  PIN do0[254]
    DIRECTION OUTPUT ;
    USE SIGNAL ;
    PORT
      LAYER M4 ;
        RECT  36.528 45.456 36.72 45.48 ;
    END
  END do0[254]
  PIN do0[255]
    DIRECTION OUTPUT ;
    USE SIGNAL ;
    PORT
      LAYER M4 ;
        RECT  36.528 45.648 36.72 45.672 ;
    END
  END do0[255]
  PIN do0[256]
    DIRECTION OUTPUT ;
    USE SIGNAL ;
    PORT
      LAYER M4 ;
        RECT  36.528 45.792 36.72 45.816 ;
    END
  END do0[256]
  PIN do0[257]
    DIRECTION OUTPUT ;
    USE SIGNAL ;
    PORT
      LAYER M4 ;
        RECT  36.528 45.936 36.72 45.96 ;
    END
  END do0[257]
  PIN do0[258]
    DIRECTION OUTPUT ;
    USE SIGNAL ;
    PORT
      LAYER M4 ;
        RECT  36.528 46.128 36.72 46.152 ;
    END
  END do0[258]
  PIN do0[259]
    DIRECTION OUTPUT ;
    USE SIGNAL ;
    PORT
      LAYER M4 ;
        RECT  36.528 46.272 36.72 46.296 ;
    END
  END do0[259]
  PIN do0[25]
    DIRECTION OUTPUT ;
    USE SIGNAL ;
    PORT
      LAYER M4 ;
        RECT  36.528 8.448 36.72 8.472 ;
    END
  END do0[25]
  PIN do0[260]
    DIRECTION OUTPUT ;
    USE SIGNAL ;
    PORT
      LAYER M4 ;
        RECT  36.528 46.416 36.72 46.44 ;
    END
  END do0[260]
  PIN do0[261]
    DIRECTION OUTPUT ;
    USE SIGNAL ;
    PORT
      LAYER M4 ;
        RECT  36.528 46.608 36.72 46.632 ;
    END
  END do0[261]
  PIN do0[262]
    DIRECTION OUTPUT ;
    USE SIGNAL ;
    PORT
      LAYER M4 ;
        RECT  36.528 46.752 36.72 46.776 ;
    END
  END do0[262]
  PIN do0[263]
    DIRECTION OUTPUT ;
    USE SIGNAL ;
    PORT
      LAYER M4 ;
        RECT  36.528 46.944 36.72 46.968 ;
    END
  END do0[263]
  PIN do0[264]
    DIRECTION OUTPUT ;
    USE SIGNAL ;
    PORT
      LAYER M4 ;
        RECT  36.528 47.088 36.72 47.112 ;
    END
  END do0[264]
  PIN do0[265]
    DIRECTION OUTPUT ;
    USE SIGNAL ;
    PORT
      LAYER M4 ;
        RECT  36.528 47.232 36.72 47.256 ;
    END
  END do0[265]
  PIN do0[266]
    DIRECTION OUTPUT ;
    USE SIGNAL ;
    PORT
      LAYER M4 ;
        RECT  36.528 47.424 36.72 47.448 ;
    END
  END do0[266]
  PIN do0[267]
    DIRECTION OUTPUT ;
    USE SIGNAL ;
    PORT
      LAYER M4 ;
        RECT  36.528 47.568 36.72 47.592 ;
    END
  END do0[267]
  PIN do0[268]
    DIRECTION OUTPUT ;
    USE SIGNAL ;
    PORT
      LAYER M4 ;
        RECT  36.528 47.712 36.72 47.736 ;
    END
  END do0[268]
  PIN do0[269]
    DIRECTION OUTPUT ;
    USE SIGNAL ;
    PORT
      LAYER M4 ;
        RECT  36.528 47.904 36.72 47.928 ;
    END
  END do0[269]
  PIN do0[26]
    DIRECTION OUTPUT ;
    USE SIGNAL ;
    PORT
      LAYER M4 ;
        RECT  36.528 8.592 36.72 8.616 ;
    END
  END do0[26]
  PIN do0[270]
    DIRECTION OUTPUT ;
    USE SIGNAL ;
    PORT
      LAYER M4 ;
        RECT  36.528 48.048 36.72 48.072 ;
    END
  END do0[270]
  PIN do0[271]
    DIRECTION OUTPUT ;
    USE SIGNAL ;
    PORT
      LAYER M4 ;
        RECT  36.528 48.192 36.72 48.216 ;
    END
  END do0[271]
  PIN do0[272]
    DIRECTION OUTPUT ;
    USE SIGNAL ;
    PORT
      LAYER M4 ;
        RECT  36.528 48.384 36.72 48.408 ;
    END
  END do0[272]
  PIN do0[273]
    DIRECTION OUTPUT ;
    USE SIGNAL ;
    PORT
      LAYER M4 ;
        RECT  36.528 48.528 36.72 48.552 ;
    END
  END do0[273]
  PIN do0[274]
    DIRECTION OUTPUT ;
    USE SIGNAL ;
    PORT
      LAYER M4 ;
        RECT  36.528 48.72 36.72 48.744 ;
    END
  END do0[274]
  PIN do0[275]
    DIRECTION OUTPUT ;
    USE SIGNAL ;
    PORT
      LAYER M4 ;
        RECT  36.528 48.864 36.72 48.888 ;
    END
  END do0[275]
  PIN do0[276]
    DIRECTION OUTPUT ;
    USE SIGNAL ;
    PORT
      LAYER M4 ;
        RECT  36.528 49.008 36.72 49.032 ;
    END
  END do0[276]
  PIN do0[277]
    DIRECTION OUTPUT ;
    USE SIGNAL ;
    PORT
      LAYER M4 ;
        RECT  36.528 49.2 36.72 49.224 ;
    END
  END do0[277]
  PIN do0[278]
    DIRECTION OUTPUT ;
    USE SIGNAL ;
    PORT
      LAYER M4 ;
        RECT  36.528 49.344 36.72 49.368 ;
    END
  END do0[278]
  PIN do0[279]
    DIRECTION OUTPUT ;
    USE SIGNAL ;
    PORT
      LAYER M4 ;
        RECT  36.528 49.488 36.72 49.512 ;
    END
  END do0[279]
  PIN do0[27]
    DIRECTION OUTPUT ;
    USE SIGNAL ;
    PORT
      LAYER M4 ;
        RECT  36.528 8.784 36.72 8.808 ;
    END
  END do0[27]
  PIN do0[280]
    DIRECTION OUTPUT ;
    USE SIGNAL ;
    PORT
      LAYER M4 ;
        RECT  36.528 49.68 36.72 49.704 ;
    END
  END do0[280]
  PIN do0[281]
    DIRECTION OUTPUT ;
    USE SIGNAL ;
    PORT
      LAYER M4 ;
        RECT  36.528 49.824 36.72 49.848 ;
    END
  END do0[281]
  PIN do0[282]
    DIRECTION OUTPUT ;
    USE SIGNAL ;
    PORT
      LAYER M4 ;
        RECT  36.528 50.016 36.72 50.04 ;
    END
  END do0[282]
  PIN do0[283]
    DIRECTION OUTPUT ;
    USE SIGNAL ;
    PORT
      LAYER M4 ;
        RECT  36.528 50.16 36.72 50.184 ;
    END
  END do0[283]
  PIN do0[284]
    DIRECTION OUTPUT ;
    USE SIGNAL ;
    PORT
      LAYER M4 ;
        RECT  36.528 50.304 36.72 50.328 ;
    END
  END do0[284]
  PIN do0[285]
    DIRECTION OUTPUT ;
    USE SIGNAL ;
    PORT
      LAYER M4 ;
        RECT  36.528 50.496 36.72 50.52 ;
    END
  END do0[285]
  PIN do0[286]
    DIRECTION OUTPUT ;
    USE SIGNAL ;
    PORT
      LAYER M4 ;
        RECT  36.528 50.64 36.72 50.664 ;
    END
  END do0[286]
  PIN do0[287]
    DIRECTION OUTPUT ;
    USE SIGNAL ;
    PORT
      LAYER M4 ;
        RECT  36.528 50.784 36.72 50.808 ;
    END
  END do0[287]
  PIN do0[288]
    DIRECTION OUTPUT ;
    USE SIGNAL ;
    PORT
      LAYER M4 ;
        RECT  36.528 50.976 36.72 51 ;
    END
  END do0[288]
  PIN do0[289]
    DIRECTION OUTPUT ;
    USE SIGNAL ;
    PORT
      LAYER M4 ;
        RECT  36.528 51.12 36.72 51.144 ;
    END
  END do0[289]
  PIN do0[28]
    DIRECTION OUTPUT ;
    USE SIGNAL ;
    PORT
      LAYER M4 ;
        RECT  36.528 8.928 36.72 8.952 ;
    END
  END do0[28]
  PIN do0[290]
    DIRECTION OUTPUT ;
    USE SIGNAL ;
    PORT
      LAYER M4 ;
        RECT  36.528 51.264 36.72 51.288 ;
    END
  END do0[290]
  PIN do0[291]
    DIRECTION OUTPUT ;
    USE SIGNAL ;
    PORT
      LAYER M4 ;
        RECT  36.528 51.456 36.72 51.48 ;
    END
  END do0[291]
  PIN do0[292]
    DIRECTION OUTPUT ;
    USE SIGNAL ;
    PORT
      LAYER M4 ;
        RECT  36.528 51.6 36.72 51.624 ;
    END
  END do0[292]
  PIN do0[29]
    DIRECTION OUTPUT ;
    USE SIGNAL ;
    PORT
      LAYER M4 ;
        RECT  36.528 9.12 36.72 9.144 ;
    END
  END do0[29]
  PIN do0[2]
    DIRECTION OUTPUT ;
    USE SIGNAL ;
    PORT
      LAYER M4 ;
        RECT  36.528 4.752 36.72 4.776 ;
    END
  END do0[2]
  PIN do0[30]
    DIRECTION OUTPUT ;
    USE SIGNAL ;
    PORT
      LAYER M4 ;
        RECT  36.528 9.264 36.72 9.288 ;
    END
  END do0[30]
  PIN do0[31]
    DIRECTION OUTPUT ;
    USE SIGNAL ;
    PORT
      LAYER M4 ;
        RECT  36.528 9.408 36.72 9.432 ;
    END
  END do0[31]
  PIN do0[32]
    DIRECTION OUTPUT ;
    USE SIGNAL ;
    PORT
      LAYER M4 ;
        RECT  36.528 9.6 36.72 9.624 ;
    END
  END do0[32]
  PIN do0[33]
    DIRECTION OUTPUT ;
    USE SIGNAL ;
    PORT
      LAYER M4 ;
        RECT  36.528 9.744 36.72 9.768 ;
    END
  END do0[33]
  PIN do0[34]
    DIRECTION OUTPUT ;
    USE SIGNAL ;
    PORT
      LAYER M4 ;
        RECT  36.528 9.888 36.72 9.912 ;
    END
  END do0[34]
  PIN do0[35]
    DIRECTION OUTPUT ;
    USE SIGNAL ;
    PORT
      LAYER M4 ;
        RECT  36.528 10.08 36.72 10.104 ;
    END
  END do0[35]
  PIN do0[36]
    DIRECTION OUTPUT ;
    USE SIGNAL ;
    PORT
      LAYER M4 ;
        RECT  36.528 10.224 36.72 10.248 ;
    END
  END do0[36]
  PIN do0[37]
    DIRECTION OUTPUT ;
    USE SIGNAL ;
    PORT
      LAYER M4 ;
        RECT  36.528 10.416 36.72 10.44 ;
    END
  END do0[37]
  PIN do0[38]
    DIRECTION OUTPUT ;
    USE SIGNAL ;
    PORT
      LAYER M4 ;
        RECT  36.528 10.56 36.72 10.584 ;
    END
  END do0[38]
  PIN do0[39]
    DIRECTION OUTPUT ;
    USE SIGNAL ;
    PORT
      LAYER M4 ;
        RECT  36.528 10.704 36.72 10.728 ;
    END
  END do0[39]
  PIN do0[3]
    DIRECTION OUTPUT ;
    USE SIGNAL ;
    PORT
      LAYER M4 ;
        RECT  36.528 4.896 36.72 4.92 ;
    END
  END do0[3]
  PIN do0[40]
    DIRECTION OUTPUT ;
    USE SIGNAL ;
    PORT
      LAYER M4 ;
        RECT  36.528 10.896 36.72 10.92 ;
    END
  END do0[40]
  PIN do0[41]
    DIRECTION OUTPUT ;
    USE SIGNAL ;
    PORT
      LAYER M4 ;
        RECT  36.528 11.04 36.72 11.064 ;
    END
  END do0[41]
  PIN do0[42]
    DIRECTION OUTPUT ;
    USE SIGNAL ;
    PORT
      LAYER M4 ;
        RECT  36.528 11.184 36.72 11.208 ;
    END
  END do0[42]
  PIN do0[43]
    DIRECTION OUTPUT ;
    USE SIGNAL ;
    PORT
      LAYER M4 ;
        RECT  36.528 11.376 36.72 11.4 ;
    END
  END do0[43]
  PIN do0[44]
    DIRECTION OUTPUT ;
    USE SIGNAL ;
    PORT
      LAYER M4 ;
        RECT  36.528 11.52 36.72 11.544 ;
    END
  END do0[44]
  PIN do0[45]
    DIRECTION OUTPUT ;
    USE SIGNAL ;
    PORT
      LAYER M4 ;
        RECT  36.528 11.664 36.72 11.688 ;
    END
  END do0[45]
  PIN do0[46]
    DIRECTION OUTPUT ;
    USE SIGNAL ;
    PORT
      LAYER M4 ;
        RECT  36.528 11.856 36.72 11.88 ;
    END
  END do0[46]
  PIN do0[47]
    DIRECTION OUTPUT ;
    USE SIGNAL ;
    PORT
      LAYER M4 ;
        RECT  36.528 12 36.72 12.024 ;
    END
  END do0[47]
  PIN do0[48]
    DIRECTION OUTPUT ;
    USE SIGNAL ;
    PORT
      LAYER M4 ;
        RECT  36.528 12.192 36.72 12.216 ;
    END
  END do0[48]
  PIN do0[49]
    DIRECTION OUTPUT ;
    USE SIGNAL ;
    PORT
      LAYER M4 ;
        RECT  36.528 12.336 36.72 12.36 ;
    END
  END do0[49]
  PIN do0[4]
    DIRECTION OUTPUT ;
    USE SIGNAL ;
    PORT
      LAYER M4 ;
        RECT  36.528 5.04 36.72 5.064 ;
    END
  END do0[4]
  PIN do0[50]
    DIRECTION OUTPUT ;
    USE SIGNAL ;
    PORT
      LAYER M4 ;
        RECT  36.528 12.48 36.72 12.504 ;
    END
  END do0[50]
  PIN do0[51]
    DIRECTION OUTPUT ;
    USE SIGNAL ;
    PORT
      LAYER M4 ;
        RECT  36.528 12.672 36.72 12.696 ;
    END
  END do0[51]
  PIN do0[52]
    DIRECTION OUTPUT ;
    USE SIGNAL ;
    PORT
      LAYER M4 ;
        RECT  36.528 12.816 36.72 12.84 ;
    END
  END do0[52]
  PIN do0[53]
    DIRECTION OUTPUT ;
    USE SIGNAL ;
    PORT
      LAYER M4 ;
        RECT  36.528 12.96 36.72 12.984 ;
    END
  END do0[53]
  PIN do0[54]
    DIRECTION OUTPUT ;
    USE SIGNAL ;
    PORT
      LAYER M4 ;
        RECT  36.528 13.152 36.72 13.176 ;
    END
  END do0[54]
  PIN do0[55]
    DIRECTION OUTPUT ;
    USE SIGNAL ;
    PORT
      LAYER M4 ;
        RECT  36.528 13.296 36.72 13.32 ;
    END
  END do0[55]
  PIN do0[56]
    DIRECTION OUTPUT ;
    USE SIGNAL ;
    PORT
      LAYER M4 ;
        RECT  36.528 13.488 36.72 13.512 ;
    END
  END do0[56]
  PIN do0[57]
    DIRECTION OUTPUT ;
    USE SIGNAL ;
    PORT
      LAYER M4 ;
        RECT  36.528 13.632 36.72 13.656 ;
    END
  END do0[57]
  PIN do0[58]
    DIRECTION OUTPUT ;
    USE SIGNAL ;
    PORT
      LAYER M4 ;
        RECT  36.528 13.776 36.72 13.8 ;
    END
  END do0[58]
  PIN do0[59]
    DIRECTION OUTPUT ;
    USE SIGNAL ;
    PORT
      LAYER M4 ;
        RECT  36.528 13.968 36.72 13.992 ;
    END
  END do0[59]
  PIN do0[5]
    DIRECTION OUTPUT ;
    USE SIGNAL ;
    PORT
      LAYER M4 ;
        RECT  36.528 5.232 36.72 5.256 ;
    END
  END do0[5]
  PIN do0[60]
    DIRECTION OUTPUT ;
    USE SIGNAL ;
    PORT
      LAYER M4 ;
        RECT  36.528 14.112 36.72 14.136 ;
    END
  END do0[60]
  PIN do0[61]
    DIRECTION OUTPUT ;
    USE SIGNAL ;
    PORT
      LAYER M4 ;
        RECT  36.528 14.256 36.72 14.28 ;
    END
  END do0[61]
  PIN do0[62]
    DIRECTION OUTPUT ;
    USE SIGNAL ;
    PORT
      LAYER M4 ;
        RECT  36.528 14.448 36.72 14.472 ;
    END
  END do0[62]
  PIN do0[63]
    DIRECTION OUTPUT ;
    USE SIGNAL ;
    PORT
      LAYER M4 ;
        RECT  36.528 14.592 36.72 14.616 ;
    END
  END do0[63]
  PIN do0[64]
    DIRECTION OUTPUT ;
    USE SIGNAL ;
    PORT
      LAYER M4 ;
        RECT  36.528 14.736 36.72 14.76 ;
    END
  END do0[64]
  PIN do0[65]
    DIRECTION OUTPUT ;
    USE SIGNAL ;
    PORT
      LAYER M4 ;
        RECT  36.528 14.928 36.72 14.952 ;
    END
  END do0[65]
  PIN do0[66]
    DIRECTION OUTPUT ;
    USE SIGNAL ;
    PORT
      LAYER M4 ;
        RECT  36.528 15.072 36.72 15.096 ;
    END
  END do0[66]
  PIN do0[67]
    DIRECTION OUTPUT ;
    USE SIGNAL ;
    PORT
      LAYER M4 ;
        RECT  36.528 15.264 36.72 15.288 ;
    END
  END do0[67]
  PIN do0[68]
    DIRECTION OUTPUT ;
    USE SIGNAL ;
    PORT
      LAYER M4 ;
        RECT  36.528 15.408 36.72 15.432 ;
    END
  END do0[68]
  PIN do0[69]
    DIRECTION OUTPUT ;
    USE SIGNAL ;
    PORT
      LAYER M4 ;
        RECT  36.528 15.552 36.72 15.576 ;
    END
  END do0[69]
  PIN do0[6]
    DIRECTION OUTPUT ;
    USE SIGNAL ;
    PORT
      LAYER M4 ;
        RECT  36.528 5.376 36.72 5.4 ;
    END
  END do0[6]
  PIN do0[70]
    DIRECTION OUTPUT ;
    USE SIGNAL ;
    PORT
      LAYER M4 ;
        RECT  36.528 15.744 36.72 15.768 ;
    END
  END do0[70]
  PIN do0[71]
    DIRECTION OUTPUT ;
    USE SIGNAL ;
    PORT
      LAYER M4 ;
        RECT  36.528 15.888 36.72 15.912 ;
    END
  END do0[71]
  PIN do0[72]
    DIRECTION OUTPUT ;
    USE SIGNAL ;
    PORT
      LAYER M4 ;
        RECT  36.528 16.032 36.72 16.056 ;
    END
  END do0[72]
  PIN do0[73]
    DIRECTION OUTPUT ;
    USE SIGNAL ;
    PORT
      LAYER M4 ;
        RECT  36.528 16.224 36.72 16.248 ;
    END
  END do0[73]
  PIN do0[74]
    DIRECTION OUTPUT ;
    USE SIGNAL ;
    PORT
      LAYER M4 ;
        RECT  36.528 16.368 36.72 16.392 ;
    END
  END do0[74]
  PIN do0[75]
    DIRECTION OUTPUT ;
    USE SIGNAL ;
    PORT
      LAYER M4 ;
        RECT  36.528 16.512 36.72 16.536 ;
    END
  END do0[75]
  PIN do0[76]
    DIRECTION OUTPUT ;
    USE SIGNAL ;
    PORT
      LAYER M4 ;
        RECT  36.528 16.704 36.72 16.728 ;
    END
  END do0[76]
  PIN do0[77]
    DIRECTION OUTPUT ;
    USE SIGNAL ;
    PORT
      LAYER M4 ;
        RECT  36.528 16.848 36.72 16.872 ;
    END
  END do0[77]
  PIN do0[78]
    DIRECTION OUTPUT ;
    USE SIGNAL ;
    PORT
      LAYER M4 ;
        RECT  36.528 17.04 36.72 17.064 ;
    END
  END do0[78]
  PIN do0[79]
    DIRECTION OUTPUT ;
    USE SIGNAL ;
    PORT
      LAYER M4 ;
        RECT  36.528 17.184 36.72 17.208 ;
    END
  END do0[79]
  PIN do0[7]
    DIRECTION OUTPUT ;
    USE SIGNAL ;
    PORT
      LAYER M4 ;
        RECT  36.528 5.568 36.72 5.592 ;
    END
  END do0[7]
  PIN do0[80]
    DIRECTION OUTPUT ;
    USE SIGNAL ;
    PORT
      LAYER M4 ;
        RECT  36.528 17.328 36.72 17.352 ;
    END
  END do0[80]
  PIN do0[81]
    DIRECTION OUTPUT ;
    USE SIGNAL ;
    PORT
      LAYER M4 ;
        RECT  36.528 17.52 36.72 17.544 ;
    END
  END do0[81]
  PIN do0[82]
    DIRECTION OUTPUT ;
    USE SIGNAL ;
    PORT
      LAYER M4 ;
        RECT  36.528 17.664 36.72 17.688 ;
    END
  END do0[82]
  PIN do0[83]
    DIRECTION OUTPUT ;
    USE SIGNAL ;
    PORT
      LAYER M4 ;
        RECT  36.528 17.808 36.72 17.832 ;
    END
  END do0[83]
  PIN do0[84]
    DIRECTION OUTPUT ;
    USE SIGNAL ;
    PORT
      LAYER M4 ;
        RECT  36.528 18 36.72 18.024 ;
    END
  END do0[84]
  PIN do0[85]
    DIRECTION OUTPUT ;
    USE SIGNAL ;
    PORT
      LAYER M4 ;
        RECT  36.528 18.144 36.72 18.168 ;
    END
  END do0[85]
  PIN do0[86]
    DIRECTION OUTPUT ;
    USE SIGNAL ;
    PORT
      LAYER M4 ;
        RECT  36.528 18.336 36.72 18.36 ;
    END
  END do0[86]
  PIN do0[87]
    DIRECTION OUTPUT ;
    USE SIGNAL ;
    PORT
      LAYER M4 ;
        RECT  36.528 18.48 36.72 18.504 ;
    END
  END do0[87]
  PIN do0[88]
    DIRECTION OUTPUT ;
    USE SIGNAL ;
    PORT
      LAYER M4 ;
        RECT  36.528 18.624 36.72 18.648 ;
    END
  END do0[88]
  PIN do0[89]
    DIRECTION OUTPUT ;
    USE SIGNAL ;
    PORT
      LAYER M4 ;
        RECT  36.528 18.816 36.72 18.84 ;
    END
  END do0[89]
  PIN do0[8]
    DIRECTION OUTPUT ;
    USE SIGNAL ;
    PORT
      LAYER M4 ;
        RECT  36.528 5.712 36.72 5.736 ;
    END
  END do0[8]
  PIN do0[90]
    DIRECTION OUTPUT ;
    USE SIGNAL ;
    PORT
      LAYER M4 ;
        RECT  36.528 18.96 36.72 18.984 ;
    END
  END do0[90]
  PIN do0[91]
    DIRECTION OUTPUT ;
    USE SIGNAL ;
    PORT
      LAYER M4 ;
        RECT  36.528 19.104 36.72 19.128 ;
    END
  END do0[91]
  PIN do0[92]
    DIRECTION OUTPUT ;
    USE SIGNAL ;
    PORT
      LAYER M4 ;
        RECT  36.528 19.296 36.72 19.32 ;
    END
  END do0[92]
  PIN do0[93]
    DIRECTION OUTPUT ;
    USE SIGNAL ;
    PORT
      LAYER M4 ;
        RECT  36.528 19.44 36.72 19.464 ;
    END
  END do0[93]
  PIN do0[94]
    DIRECTION OUTPUT ;
    USE SIGNAL ;
    PORT
      LAYER M4 ;
        RECT  36.528 19.584 36.72 19.608 ;
    END
  END do0[94]
  PIN do0[95]
    DIRECTION OUTPUT ;
    USE SIGNAL ;
    PORT
      LAYER M4 ;
        RECT  36.528 19.776 36.72 19.8 ;
    END
  END do0[95]
  PIN do0[96]
    DIRECTION OUTPUT ;
    USE SIGNAL ;
    PORT
      LAYER M4 ;
        RECT  36.528 19.92 36.72 19.944 ;
    END
  END do0[96]
  PIN do0[97]
    DIRECTION OUTPUT ;
    USE SIGNAL ;
    PORT
      LAYER M4 ;
        RECT  36.528 20.112 36.72 20.136 ;
    END
  END do0[97]
  PIN do0[98]
    DIRECTION OUTPUT ;
    USE SIGNAL ;
    PORT
      LAYER M4 ;
        RECT  36.528 20.256 36.72 20.28 ;
    END
  END do0[98]
  PIN do0[99]
    DIRECTION OUTPUT ;
    USE SIGNAL ;
    PORT
      LAYER M4 ;
        RECT  36.528 20.4 36.72 20.424 ;
    END
  END do0[99]
  PIN do0[9]
    DIRECTION OUTPUT ;
    USE SIGNAL ;
    PORT
      LAYER M4 ;
        RECT  36.528 5.856 36.72 5.88 ;
    END
  END do0[9]
  PIN fi0[0]
    DIRECTION INPUT ;
    USE SIGNAL ;
    PORT
      LAYER M4 ;
        RECT  0 51.792 0.192 51.816 ;
    END
  END fi0[0]
  PIN fo0[0]
    DIRECTION OUTPUT ;
    USE SIGNAL ;
    PORT
      LAYER M4 ;
        RECT  36.528 51.792 36.72 51.816 ;
    END
  END fo0[0]
  PIN VDD
    DIRECTION INOUT ;
    USE POWER ;
    PORT
      LAYER M5 ;
        RECT  32.292 2.151 32.412 54.009 ;
        RECT  29.592 2.151 29.712 54.009 ;
        RECT  26.892 2.151 27.012 54.009 ;
        RECT  24.192 2.151 24.312 54.009 ;
        RECT  21.492 2.151 21.612 54.009 ;
        RECT  18.792 2.151 18.912 54.009 ;
        RECT  16.092 2.151 16.212 54.009 ;
        RECT  13.392 2.151 13.512 54.009 ;
        RECT  10.692 2.151 10.812 54.009 ;
        RECT  7.992 2.151 8.112 54.009 ;
        RECT  5.292 2.151 5.412 54.009 ;
        RECT  2.592 2.151 2.712 54.009 ;
    END
  END VDD
  PIN VSS
    DIRECTION INOUT ;
    USE GROUND ;
    PORT
      LAYER M5 ;
        RECT  32.1 2.137 32.22 54.023 ;
        RECT  29.4 2.137 29.52 54.023 ;
        RECT  26.7 2.137 26.82 54.023 ;
        RECT  24 2.137 24.12 54.023 ;
        RECT  21.3 2.137 21.42 54.023 ;
        RECT  18.6 2.137 18.72 54.023 ;
        RECT  15.9 2.137 16.02 54.023 ;
        RECT  13.2 2.137 13.32 54.023 ;
        RECT  10.5 2.137 10.62 54.023 ;
        RECT  7.8 2.137 7.92 54.023 ;
        RECT  5.1 2.137 5.22 54.023 ;
        RECT  2.4 2.137 2.52 54.023 ;
    END
  END VSS
  # OT_OBS_CLOSED layer=M5 d_um=1.536 added=18
  OBS
    LAYER RVTN ;
     RECT  2.16 2.16 34.56 2.295 ;
     RECT  2.16 2.565 34.56 2.835 ;
     RECT  2.16 3.105 34.56 3.375 ;
     RECT  2.16 3.645 34.56 3.915 ;
     RECT  2.16 4.185 34.56 4.455 ;
     RECT  2.16 4.725 34.56 4.995 ;
     RECT  2.16 5.265 34.56 5.535 ;
     RECT  2.16 5.805 34.56 6.075 ;
     RECT  2.16 6.345 34.56 6.615 ;
     RECT  2.16 6.885 34.56 7.155 ;
     RECT  2.16 7.425 34.56 7.695 ;
     RECT  2.16 7.965 34.56 8.235 ;
     RECT  2.16 8.505 34.56 8.775 ;
     RECT  2.16 9.045 34.56 9.315 ;
     RECT  2.16 9.585 34.56 9.855 ;
     RECT  2.16 10.125 34.56 10.395 ;
     RECT  2.16 10.665 34.56 10.935 ;
     RECT  2.16 11.205 34.56 11.475 ;
     RECT  2.16 11.745 34.56 12.015 ;
     RECT  2.16 12.285 34.56 12.555 ;
     RECT  2.16 12.825 34.56 13.095 ;
     RECT  2.16 13.365 34.56 13.635 ;
     RECT  2.16 13.905 34.56 14.175 ;
     RECT  2.16 14.445 34.56 14.715 ;
     RECT  2.16 14.985 34.56 15.255 ;
     RECT  2.16 15.525 34.56 15.795 ;
     RECT  2.16 16.065 34.56 16.335 ;
     RECT  2.16 16.605 34.56 16.875 ;
     RECT  2.16 17.145 34.56 17.415 ;
     RECT  2.16 17.685 34.56 17.955 ;
     RECT  2.16 18.225 34.56 18.495 ;
     RECT  2.16 18.765 34.56 19.035 ;
     RECT  2.16 19.305 34.56 19.575 ;
     RECT  2.16 19.845 34.56 20.115 ;
     RECT  2.16 20.385 34.56 20.655 ;
     RECT  2.16 20.925 34.56 21.195 ;
     RECT  2.16 21.465 34.56 21.735 ;
     RECT  2.16 22.005 34.56 22.275 ;
     RECT  2.16 22.545 34.56 22.815 ;
     RECT  2.16 23.085 34.56 23.355 ;
     RECT  2.16 23.625 34.56 23.895 ;
     RECT  2.16 24.165 34.56 24.435 ;
     RECT  2.16 24.705 34.56 24.975 ;
     RECT  2.16 25.245 34.56 25.515 ;
     RECT  2.16 25.785 34.56 26.055 ;
     RECT  2.16 26.325 34.56 26.595 ;
     RECT  2.16 26.865 34.56 27.135 ;
     RECT  2.16 27.405 34.56 27.675 ;
     RECT  2.16 27.945 34.56 28.215 ;
     RECT  2.16 28.485 34.56 28.755 ;
     RECT  2.16 29.025 34.56 29.295 ;
     RECT  2.16 29.565 34.56 29.835 ;
     RECT  2.16 30.105 34.56 30.375 ;
     RECT  2.16 30.645 34.56 30.915 ;
     RECT  2.16 31.185 34.56 31.455 ;
     RECT  2.16 31.725 34.56 31.995 ;
     RECT  2.16 32.265 34.56 32.535 ;
     RECT  2.16 32.805 34.56 33.075 ;
     RECT  2.16 33.345 34.56 33.615 ;
     RECT  2.16 33.885 34.56 34.155 ;
     RECT  2.16 34.425 34.56 34.695 ;
     RECT  2.16 34.965 34.56 35.235 ;
     RECT  2.16 35.505 34.56 35.775 ;
     RECT  2.16 36.045 34.56 36.315 ;
     RECT  2.16 36.585 34.56 36.855 ;
     RECT  2.16 37.125 34.56 37.395 ;
     RECT  2.16 37.665 34.56 37.935 ;
     RECT  2.16 38.205 34.56 38.475 ;
     RECT  2.16 38.745 34.56 39.015 ;
     RECT  2.16 39.285 34.56 39.555 ;
     RECT  2.16 39.825 34.56 40.095 ;
     RECT  2.16 40.365 34.56 40.635 ;
     RECT  2.16 40.905 34.56 41.175 ;
     RECT  2.16 41.445 34.56 41.715 ;
     RECT  2.16 41.985 34.56 42.255 ;
     RECT  2.16 42.525 34.56 42.795 ;
     RECT  2.16 43.065 34.56 43.335 ;
     RECT  2.16 43.605 34.56 43.875 ;
     RECT  2.16 44.145 34.56 44.415 ;
     RECT  2.16 44.685 34.56 44.955 ;
     RECT  2.16 45.225 34.56 45.495 ;
     RECT  2.16 45.765 34.56 46.035 ;
     RECT  2.16 46.305 34.56 46.575 ;
     RECT  2.16 46.845 34.56 47.115 ;
     RECT  2.16 47.385 34.56 47.655 ;
     RECT  2.16 47.925 34.56 48.195 ;
     RECT  2.16 48.465 34.56 48.735 ;
     RECT  2.16 49.005 34.56 49.275 ;
     RECT  2.16 49.545 34.56 49.815 ;
     RECT  2.16 50.085 34.56 50.355 ;
     RECT  2.16 50.625 34.56 50.895 ;
     RECT  2.16 51.165 34.56 51.435 ;
     RECT  2.16 51.705 34.56 51.975 ;
     RECT  2.16 52.245 34.56 52.515 ;
     RECT  2.16 52.785 34.56 53.055 ;
     RECT  2.16 53.325 34.56 53.595 ;
     RECT  2.16 53.865 34.56 54 ;
    LAYER RVTP ;
     RECT  2.16 2.295 34.56 2.565 ;
     RECT  2.16 2.835 34.56 3.105 ;
     RECT  2.16 3.375 34.56 3.645 ;
     RECT  2.16 3.915 34.56 4.185 ;
     RECT  2.16 4.455 34.56 4.725 ;
     RECT  2.16 4.995 34.56 5.265 ;
     RECT  2.16 5.535 34.56 5.805 ;
     RECT  2.16 6.075 34.56 6.345 ;
     RECT  2.16 6.615 34.56 6.885 ;
     RECT  2.16 7.155 34.56 7.425 ;
     RECT  2.16 7.695 34.56 7.965 ;
     RECT  2.16 8.235 34.56 8.505 ;
     RECT  2.16 8.775 34.56 9.045 ;
     RECT  2.16 9.315 34.56 9.585 ;
     RECT  2.16 9.855 34.56 10.125 ;
     RECT  2.16 10.395 34.56 10.665 ;
     RECT  2.16 10.935 34.56 11.205 ;
     RECT  2.16 11.475 34.56 11.745 ;
     RECT  2.16 12.015 34.56 12.285 ;
     RECT  2.16 12.555 34.56 12.825 ;
     RECT  2.16 13.095 34.56 13.365 ;
     RECT  2.16 13.635 34.56 13.905 ;
     RECT  2.16 14.175 34.56 14.445 ;
     RECT  2.16 14.715 34.56 14.985 ;
     RECT  2.16 15.255 34.56 15.525 ;
     RECT  2.16 15.795 34.56 16.065 ;
     RECT  2.16 16.335 34.56 16.605 ;
     RECT  2.16 16.875 34.56 17.145 ;
     RECT  2.16 17.415 34.56 17.685 ;
     RECT  2.16 17.955 34.56 18.225 ;
     RECT  2.16 18.495 34.56 18.765 ;
     RECT  2.16 19.035 34.56 19.305 ;
     RECT  2.16 19.575 34.56 19.845 ;
     RECT  2.16 20.115 34.56 20.385 ;
     RECT  2.16 20.655 34.56 20.925 ;
     RECT  2.16 21.195 34.56 21.465 ;
     RECT  2.16 21.735 34.56 22.005 ;
     RECT  2.16 22.275 34.56 22.545 ;
     RECT  2.16 22.815 34.56 23.085 ;
     RECT  2.16 23.355 34.56 23.625 ;
     RECT  2.16 23.895 34.56 24.165 ;
     RECT  2.16 24.435 34.56 24.705 ;
     RECT  2.16 24.975 34.56 25.245 ;
     RECT  2.16 25.515 34.56 25.785 ;
     RECT  2.16 26.055 34.56 26.325 ;
     RECT  2.16 26.595 34.56 26.865 ;
     RECT  2.16 27.135 34.56 27.405 ;
     RECT  2.16 27.675 34.56 27.945 ;
     RECT  2.16 28.215 34.56 28.485 ;
     RECT  2.16 28.755 34.56 29.025 ;
     RECT  2.16 29.295 34.56 29.565 ;
     RECT  2.16 29.835 34.56 30.105 ;
     RECT  2.16 30.375 34.56 30.645 ;
     RECT  2.16 30.915 34.56 31.185 ;
     RECT  2.16 31.455 34.56 31.725 ;
     RECT  2.16 31.995 34.56 32.265 ;
     RECT  2.16 32.535 34.56 32.805 ;
     RECT  2.16 33.075 34.56 33.345 ;
     RECT  2.16 33.615 34.56 33.885 ;
     RECT  2.16 34.155 34.56 34.425 ;
     RECT  2.16 34.695 34.56 34.965 ;
     RECT  2.16 35.235 34.56 35.505 ;
     RECT  2.16 35.775 34.56 36.045 ;
     RECT  2.16 36.315 34.56 36.585 ;
     RECT  2.16 36.855 34.56 37.125 ;
     RECT  2.16 37.395 34.56 37.665 ;
     RECT  2.16 37.935 34.56 38.205 ;
     RECT  2.16 38.475 34.56 38.745 ;
     RECT  2.16 39.015 34.56 39.285 ;
     RECT  2.16 39.555 34.56 39.825 ;
     RECT  2.16 40.095 34.56 40.365 ;
     RECT  2.16 40.635 34.56 40.905 ;
     RECT  2.16 41.175 34.56 41.445 ;
     RECT  2.16 41.715 34.56 41.985 ;
     RECT  2.16 42.255 34.56 42.525 ;
     RECT  2.16 42.795 34.56 43.065 ;
     RECT  2.16 43.335 34.56 43.605 ;
     RECT  2.16 43.875 34.56 44.145 ;
     RECT  2.16 44.415 34.56 44.685 ;
     RECT  2.16 44.955 34.56 45.225 ;
     RECT  2.16 45.495 34.56 45.765 ;
     RECT  2.16 46.035 34.56 46.305 ;
     RECT  2.16 46.575 34.56 46.845 ;
     RECT  2.16 47.115 34.56 47.385 ;
     RECT  2.16 47.655 34.56 47.925 ;
     RECT  2.16 48.195 34.56 48.465 ;
     RECT  2.16 48.735 34.56 49.005 ;
     RECT  2.16 49.275 34.56 49.545 ;
     RECT  2.16 49.815 34.56 50.085 ;
     RECT  2.16 50.355 34.56 50.625 ;
     RECT  2.16 50.895 34.56 51.165 ;
     RECT  2.16 51.435 34.56 51.705 ;
     RECT  2.16 51.975 34.56 52.245 ;
     RECT  2.16 52.515 34.56 52.785 ;
     RECT  2.16 53.055 34.56 53.325 ;
     RECT  2.16 53.595 34.56 53.865 ;
    LAYER M1 ;
     RECT  2.16 2.151 34.56 54.009 ;
    LAYER M2 ;
     RECT  0.319 11.952 2.16 11.97 ;
     RECT  0.211 27.342 2.16 27.36 ;
     RECT  2.16 2.151 34.56 54.009 ;
     RECT  34.56 6.624 34.691 38.304 ;
     RECT  34.56 3.384 34.763 5.094 ;
     RECT  34.691 6.624 34.763 33.138 ;
     RECT  34.763 6.624 34.799 8.496 ;
     RECT  34.763 15.066 34.799 33.138 ;
     RECT  34.56 43.614 34.799 53.514 ;
     RECT  34.799 6.894 34.835 8.334 ;
     RECT  34.799 15.066 34.835 23.418 ;
     RECT  34.56 39.096 34.835 42.714 ;
     RECT  34.799 46.656 34.835 50.886 ;
     RECT  34.799 52.254 34.835 53.514 ;
     RECT  34.763 9.324 34.871 14.274 ;
     RECT  34.835 49.824 34.871 50.886 ;
     RECT  34.871 49.896 34.907 50.886 ;
     RECT  34.835 22.356 35.339 23.418 ;
     RECT  34.835 6.894 35.375 8.154 ;
     RECT  34.871 9.324 35.375 12.078 ;
     RECT  34.871 12.834 35.375 14.274 ;
     RECT  34.799 24.21 35.375 33.138 ;
     RECT  34.691 33.966 35.375 38.304 ;
     RECT  34.835 39.096 35.375 42.318 ;
     RECT  34.907 49.896 35.375 50.724 ;
     RECT  34.763 3.546 35.411 5.094 ;
     RECT  35.375 9.324 35.411 9.342 ;
     RECT  35.375 12.834 35.411 14.004 ;
     RECT  35.375 24.246 35.411 26.658 ;
     RECT  35.375 27.414 35.411 33.138 ;
     RECT  35.375 39.636 35.411 42.318 ;
     RECT  34.835 46.656 35.411 49.032 ;
     RECT  35.411 4.464 35.447 5.094 ;
     RECT  35.375 6.894 35.447 6.912 ;
     RECT  35.411 27.99 35.447 33.138 ;
     RECT  34.835 52.326 35.627 53.514 ;
     RECT  35.447 4.896 35.951 5.094 ;
     RECT  35.375 8.136 35.951 8.154 ;
     RECT  35.375 10.098 35.951 12.078 ;
     RECT  35.411 12.87 35.951 14.004 ;
     RECT  34.835 15.066 35.951 21.564 ;
     RECT  35.339 22.356 35.951 22.374 ;
     RECT  35.411 24.246 35.951 25.614 ;
     RECT  35.411 26.64 35.951 26.658 ;
     RECT  35.447 27.99 35.951 29.322 ;
     RECT  35.447 30.186 35.951 33.138 ;
     RECT  35.375 33.966 35.951 37.764 ;
     RECT  35.411 40.068 35.951 42.318 ;
     RECT  34.799 43.614 35.951 45.756 ;
     RECT  35.411 46.656 35.951 48.222 ;
     RECT  35.411 49.014 35.951 49.032 ;
     RECT  35.375 50.436 35.951 50.724 ;
     RECT  35.627 53.136 35.951 53.514 ;
     RECT  35.411 3.546 35.987 3.564 ;
     RECT  35.951 10.098 35.987 10.998 ;
     RECT  35.951 13.536 35.987 13.554 ;
     RECT  35.951 15.066 35.987 16.398 ;
     RECT  35.951 19.656 35.987 19.674 ;
     RECT  35.951 20.736 35.987 21.492 ;
     RECT  35.339 23.13 35.987 23.418 ;
     RECT  35.951 24.984 35.987 25.002 ;
     RECT  35.951 27.99 35.987 28.818 ;
     RECT  35.951 30.186 35.987 30.708 ;
     RECT  35.951 31.77 35.987 31.788 ;
     RECT  35.951 32.58 35.987 32.796 ;
     RECT  35.951 33.966 35.987 34.218 ;
     RECT  35.951 35.01 35.987 35.028 ;
     RECT  35.951 36.126 35.987 36.144 ;
     RECT  35.951 36.936 35.987 37.692 ;
     RECT  35.951 40.878 35.987 42.318 ;
     RECT  35.951 53.136 35.987 53.154 ;
     RECT  35.951 5.076 36.023 5.094 ;
     RECT  35.987 10.368 36.023 10.386 ;
     RECT  35.987 15.804 36.023 16.128 ;
     RECT  35.987 21.168 36.023 21.492 ;
     RECT  35.987 23.13 36.023 23.148 ;
     RECT  35.987 32.778 36.023 32.796 ;
     RECT  35.987 33.966 36.023 33.984 ;
     RECT  35.987 37.476 36.023 37.494 ;
     RECT  35.987 41.184 36.023 41.859 ;
     RECT  35.951 44.19 36.023 45.522 ;
     RECT  35.951 46.656 36.023 47.214 ;
     RECT  36.023 21.168 36.059 21.186 ;
     RECT  36.023 41.841 36.059 41.859 ;
     RECT  36.023 46.656 36.095 46.674 ;
     RECT  35.627 52.326 36.491 52.344 ;
     RECT  34.56 2.466 36.563 2.484 ;
    LAYER M3 ;
     RECT  2.415 2.143 2.505 2.413 ;
     RECT  5.115 2.143 5.205 2.413 ;
     RECT  7.815 2.143 7.905 2.413 ;
     RECT  10.515 2.143 10.605 2.413 ;
     RECT  13.215 2.143 13.305 2.413 ;
     RECT  15.915 2.143 16.005 2.413 ;
     RECT  18.615 2.143 18.705 2.413 ;
     RECT  21.315 2.143 21.405 2.413 ;
     RECT  24.015 2.143 24.105 2.413 ;
     RECT  26.715 2.143 26.805 2.413 ;
     RECT  29.415 2.143 29.505 2.413 ;
     RECT  32.115 2.143 32.205 2.413 ;
     RECT  33.66 2.569 33.678 2.641 ;
     RECT  33.66 2.641 34.182 2.803 ;
     RECT  33.66 2.803 34.47 2.939 ;
     RECT  33.732 2.939 34.47 3.109 ;
     RECT  33.732 3.109 34.506 3.379 ;
     RECT  36.54 2.461 36.558 3.541 ;
     RECT  33.732 3.379 34.758 3.685 ;
     RECT  33.696 3.685 34.758 3.811 ;
     RECT  35.964 3.541 36.558 3.811 ;
     RECT  33.696 3.811 36.558 4.081 ;
     RECT  2.415 2.413 2.697 4.225 ;
     RECT  5.115 2.413 5.397 4.261 ;
     RECT  32.115 2.413 32.397 4.495 ;
     RECT  33.444 4.081 36.558 4.495 ;
     RECT  32.115 4.495 36.558 4.685 ;
     RECT  32.115 4.685 36.486 4.781 ;
     RECT  2.304 4.225 2.697 4.891 ;
     RECT  2.268 4.891 2.697 5.035 ;
     RECT  2.268 5.035 2.862 5.063 ;
     RECT  2.304 5.063 2.862 5.071 ;
     RECT  4.536 4.261 5.397 5.161 ;
     RECT  6.408 5.071 6.426 5.161 ;
     RECT  2.304 5.071 3.546 5.189 ;
     RECT  2.304 5.189 3.474 5.225 ;
     RECT  6.408 5.161 6.534 5.233 ;
     RECT  9.72 5.161 9.738 5.261 ;
     RECT  4.356 5.161 5.397 5.305 ;
     RECT  6.408 5.233 6.822 5.305 ;
     RECT  3.456 5.225 3.474 5.369 ;
     RECT  4.212 5.305 6.822 5.459 ;
     RECT  4.356 5.459 6.822 5.501 ;
     RECT  6.228 5.501 6.822 5.503 ;
     RECT  32.115 4.781 36.018 5.741 ;
     RECT  6.228 5.503 6.858 5.845 ;
     RECT  32.115 5.741 34.506 5.845 ;
     RECT  30.78 5.467 30.798 5.881 ;
     RECT  35.352 5.741 36.018 5.885 ;
     RECT  6.228 5.845 6.894 5.999 ;
     RECT  30.78 5.881 30.87 6.035 ;
     RECT  32.076 5.845 34.506 6.035 ;
     RECT  2.304 5.225 2.697 6.151 ;
     RECT  7.815 2.413 8.097 6.151 ;
     RECT  7.815 6.151 8.298 6.269 ;
     RECT  30.78 6.035 30.798 6.269 ;
     RECT  4.356 5.501 5.397 6.385 ;
     RECT  32.112 6.035 34.506 6.413 ;
     RECT  4.14 6.385 5.397 6.511 ;
     RECT  6.228 5.999 6.498 6.511 ;
     RECT  32.115 6.413 34.506 6.523 ;
     RECT  35.352 5.885 35.37 6.523 ;
     RECT  4.14 6.511 6.498 6.575 ;
     RECT  4.572 6.575 6.498 6.817 ;
     RECT  32.115 6.523 35.37 6.845 ;
     RECT  35.352 6.845 35.37 6.889 ;
     RECT  4.572 6.817 6.858 7.087 ;
     RECT  7.815 6.269 8.097 7.087 ;
     RECT  2.304 6.151 3.222 7.159 ;
     RECT  30.852 7.123 30.87 7.159 ;
     RECT  35.352 6.889 35.442 7.181 ;
     RECT  32.115 6.845 34.254 7.195 ;
     RECT  10.515 2.413 10.797 7.231 ;
     RECT  30.78 7.159 30.87 7.259 ;
     RECT  9.576 7.231 10.797 7.349 ;
     RECT  31.68 7.195 34.254 7.357 ;
     RECT  2.304 7.159 3.582 7.429 ;
     RECT  4.572 7.087 8.097 7.429 ;
     RECT  10.515 7.349 10.797 7.501 ;
     RECT  31.5 7.357 34.254 7.619 ;
     RECT  10.515 7.501 10.818 7.763 ;
     RECT  2.304 7.429 8.097 7.897 ;
     RECT  2.304 7.897 8.586 7.961 ;
     RECT  32.115 7.619 34.254 7.963 ;
     RECT  35.352 7.181 35.37 7.963 ;
     RECT  2.304 7.961 3.438 8.041 ;
     RECT  32.115 7.963 35.37 8.131 ;
     RECT  2.268 8.041 3.438 8.141 ;
     RECT  32.115 8.131 35.946 8.141 ;
     RECT  9.576 7.349 9.594 8.159 ;
     RECT  4.212 7.961 8.586 8.203 ;
     RECT  4.212 8.203 9.126 8.231 ;
     RECT  4.284 8.231 9.126 8.438 ;
     RECT  32.115 8.141 34.83 8.477 ;
     RECT  32.115 8.477 34.794 8.581 ;
     RECT  4.284 8.438 9.09 8.609 ;
     RECT  35.928 8.141 35.946 8.621 ;
     RECT  32.04 8.581 34.794 8.735 ;
     RECT  4.284 8.609 8.838 8.771 ;
     RECT  30.852 8.437 30.87 8.851 ;
     RECT  30.78 8.851 30.87 8.879 ;
     RECT  4.572 8.771 8.838 8.969 ;
     RECT  2.304 8.141 3.438 9.013 ;
     RECT  30.78 8.879 30.798 9.077 ;
     RECT  2.304 9.013 3.798 9.101 ;
     RECT  4.572 8.969 8.55 9.113 ;
     RECT  4.572 9.113 7.074 9.239 ;
     RECT  32.115 8.735 34.794 9.259 ;
     RECT  2.304 9.101 3.69 9.509 ;
     RECT  0.216 9.403 0.234 9.533 ;
     RECT  4.572 9.239 6.282 9.589 ;
     RECT  32.115 9.259 35.406 9.617 ;
     RECT  4.536 9.589 6.282 9.689 ;
     RECT  7.056 9.239 7.074 9.689 ;
     RECT  35.352 9.617 35.406 9.689 ;
     RECT  2.304 9.509 3.654 9.739 ;
     RECT  2.268 9.739 3.654 9.779 ;
     RECT  32.115 9.617 34.326 9.787 ;
     RECT  35.892 9.739 35.946 9.883 ;
     RECT  2.268 9.779 3.366 9.887 ;
     RECT  7.815 9.113 8.55 9.887 ;
     RECT  4.572 9.689 6.282 9.959 ;
     RECT  32.112 9.787 34.326 10.049 ;
     RECT  9.468 9.823 9.486 10.193 ;
     RECT  35.892 9.883 35.982 10.219 ;
     RECT  2.304 9.887 3.366 10.229 ;
     RECT  30.78 10.021 30.798 10.229 ;
     RECT  7.815 9.887 8.226 10.267 ;
     RECT  35.892 10.219 36.018 10.391 ;
     RECT  4.572 9.959 6.246 10.471 ;
     RECT  35.892 10.391 35.982 10.555 ;
     RECT  21.315 2.413 21.597 10.561 ;
     RECT  7.344 10.267 8.226 10.589 ;
     RECT  32.112 10.049 34.29 10.589 ;
     RECT  4.428 10.471 6.246 10.741 ;
     RECT  32.112 10.589 34.254 10.831 ;
     RECT  21.096 10.561 21.597 10.859 ;
     RECT  4.068 10.741 6.246 10.931 ;
     RECT  35.856 10.555 35.982 11.003 ;
     RECT  4.572 10.931 6.246 11.011 ;
     RECT  9.468 10.975 9.486 11.021 ;
     RECT  31.464 10.831 34.254 11.129 ;
     RECT  2.304 10.229 3.15 11.131 ;
     RECT  31.248 11.137 31.266 11.173 ;
     RECT  30.78 11.173 31.266 11.273 ;
     RECT  2.304 11.131 3.186 11.281 ;
     RECT  7.344 10.589 8.097 11.281 ;
     RECT  35.856 11.003 35.946 11.365 ;
     RECT  7.056 11.281 8.097 11.371 ;
     RECT  32.115 11.129 34.254 11.479 ;
     RECT  32.115 11.479 34.29 11.515 ;
     RECT  35.352 11.365 35.946 11.515 ;
     RECT  4.572 11.011 6.282 11.551 ;
     RECT  7.056 11.371 8.154 11.551 ;
     RECT  2.304 11.281 3.618 11.705 ;
     RECT  2.415 11.705 3.618 11.911 ;
     RECT  4.572 11.551 8.154 11.911 ;
     RECT  9.36 11.749 9.378 11.939 ;
     RECT  0.252 11.035 0.27 11.947 ;
     RECT  2.415 11.911 8.154 11.975 ;
     RECT  0.252 11.947 0.342 11.981 ;
     RECT  30.852 11.273 31.266 12.019 ;
     RECT  0.324 11.981 0.342 12.029 ;
     RECT  30.78 12.019 31.266 12.055 ;
     RECT  32.115 11.515 35.946 12.055 ;
     RECT  6.48 11.975 8.154 12.209 ;
     RECT  6.66 12.209 8.154 12.361 ;
     RECT  2.415 11.975 5.742 12.389 ;
     RECT  30.78 12.055 35.946 12.389 ;
     RECT  30.852 12.389 34.29 12.479 ;
     RECT  30.852 12.479 34.146 12.515 ;
     RECT  2.415 12.389 5.706 12.659 ;
     RECT  9.504 12.487 9.522 12.659 ;
     RECT  2.415 12.659 3.402 12.667 ;
     RECT  6.66 12.361 8.262 12.865 ;
     RECT  0.216 12.955 0.234 13.085 ;
     RECT  6.66 12.865 8.298 13.085 ;
     RECT  4.32 12.659 5.706 13.171 ;
     RECT  6.876 13.085 8.298 13.171 ;
     RECT  35.352 12.389 35.946 13.325 ;
     RECT  4.32 13.171 5.814 13.369 ;
     RECT  25.128 13.297 25.146 13.397 ;
     RECT  2.304 12.667 3.402 13.405 ;
     RECT  4.32 13.369 5.886 13.405 ;
     RECT  31.032 12.515 34.146 13.405 ;
     RECT  6.876 13.171 8.334 13.441 ;
     RECT  9.54 13.063 9.558 13.441 ;
     RECT  35.928 13.325 35.946 13.531 ;
     RECT  2.304 13.405 3.582 13.559 ;
     RECT  4.32 13.405 6.03 13.559 ;
     RECT  6.876 13.441 9.558 13.559 ;
     RECT  31.032 13.405 34.182 13.567 ;
     RECT  30.852 13.567 34.182 13.603 ;
     RECT  30.816 13.603 34.182 13.627 ;
     RECT  30.816 13.627 34.758 13.667 ;
     RECT  9.72 13.567 9.738 13.739 ;
     RECT  4.32 13.559 5.922 13.801 ;
     RECT  30.816 13.667 34.254 13.901 ;
     RECT  2.304 13.559 3.438 13.963 ;
     RECT  6.876 13.559 8.622 13.981 ;
     RECT  31.572 13.901 34.254 14.009 ;
     RECT  6.84 13.981 8.622 14.099 ;
     RECT  31.68 14.009 34.254 14.099 ;
     RECT  30.816 13.901 30.834 14.207 ;
     RECT  35.928 13.531 35.982 14.245 ;
     RECT  35.352 14.245 35.982 14.285 ;
     RECT  6.912 14.099 8.622 14.485 ;
     RECT  32.04 14.099 34.254 14.521 ;
     RECT  32.04 14.521 34.866 14.621 ;
     RECT  4.212 13.801 5.922 14.639 ;
     RECT  6.912 14.485 8.73 14.639 ;
     RECT  6.912 14.639 6.966 14.675 ;
     RECT  10.515 7.763 10.797 14.683 ;
     RECT  30.852 14.647 30.87 14.747 ;
     RECT  10.515 14.683 10.854 14.783 ;
     RECT  7.704 14.639 8.298 14.819 ;
     RECT  2.268 13.963 3.438 14.881 ;
     RECT  4.212 14.639 5.778 14.881 ;
     RECT  9.072 14.881 9.09 15.053 ;
     RECT  32.04 14.621 34.11 15.061 ;
     RECT  35.928 14.285 35.982 15.067 ;
     RECT  6.912 14.675 6.93 15.151 ;
     RECT  31.572 15.061 34.11 15.215 ;
     RECT  34.848 14.621 34.866 15.259 ;
     RECT  35.928 15.067 36.018 15.259 ;
     RECT  2.268 14.881 5.778 15.359 ;
     RECT  6.84 15.151 6.93 15.359 ;
     RECT  34.848 15.259 36.018 15.359 ;
     RECT  32.115 15.215 34.11 15.403 ;
     RECT  34.848 15.359 34.866 15.403 ;
     RECT  7.776 14.819 8.298 15.449 ;
     RECT  2.268 15.359 4.05 15.485 ;
     RECT  7.815 15.449 8.298 15.521 ;
     RECT  5.004 15.359 5.778 15.529 ;
     RECT  2.304 15.485 4.05 15.755 ;
     RECT  30.78 15.223 30.798 15.763 ;
     RECT  5.004 15.529 5.958 15.799 ;
     RECT  6.912 15.359 6.93 15.961 ;
     RECT  32.115 15.403 34.866 15.961 ;
     RECT  5.004 15.799 6.03 16.105 ;
     RECT  6.912 15.961 6.966 16.105 ;
     RECT  30.78 15.763 30.87 16.133 ;
     RECT  35.928 15.359 36.018 16.133 ;
     RECT  4.428 16.105 6.03 16.141 ;
     RECT  6.912 16.105 7.074 16.141 ;
     RECT  10.515 14.783 10.797 16.141 ;
     RECT  25.092 16.069 25.11 16.141 ;
     RECT  25.092 16.141 25.182 16.169 ;
     RECT  31.932 15.961 34.866 16.219 ;
     RECT  35.928 16.133 35.982 16.219 ;
     RECT  9.432 16.141 9.45 16.295 ;
     RECT  25.164 16.169 25.182 16.295 ;
     RECT  0.252 16.219 0.27 16.349 ;
     RECT  10.515 16.141 10.854 16.367 ;
     RECT  31.932 16.219 35.982 16.375 ;
     RECT  31.896 16.375 35.982 16.403 ;
     RECT  2.304 15.755 3.366 16.529 ;
     RECT  30.78 16.133 30.798 16.529 ;
     RECT  31.896 16.403 35.946 16.529 ;
     RECT  4.428 16.141 7.074 16.645 ;
     RECT  2.304 16.529 2.862 16.681 ;
     RECT  3.708 16.645 7.074 16.696 ;
     RECT  3.708 16.696 3.942 16.835 ;
     RECT  4.752 16.696 7.074 16.843 ;
     RECT  7.815 15.521 8.097 16.843 ;
     RECT  4.752 16.843 8.097 16.951 ;
     RECT  3.924 16.835 3.942 17.069 ;
     RECT  31.932 16.529 35.946 17.069 ;
     RECT  10.515 16.367 10.797 17.311 ;
     RECT  4.752 16.951 8.406 17.339 ;
     RECT  2.268 16.681 2.862 17.347 ;
     RECT  2.268 17.347 2.898 17.375 ;
     RECT  30.924 17.311 30.942 17.383 ;
     RECT  10.515 17.311 10.926 17.447 ;
     RECT  30.852 17.383 30.942 17.483 ;
     RECT  9.684 17.041 9.702 17.491 ;
     RECT  10.515 17.447 10.797 17.491 ;
     RECT  32.04 17.069 34.758 17.549 ;
     RECT  9.684 17.491 10.797 17.609 ;
     RECT  2.304 17.375 2.898 17.707 ;
     RECT  4.752 17.339 8.097 17.761 ;
     RECT  35.928 17.069 35.946 17.803 ;
     RECT  4.68 17.761 8.097 17.95 ;
     RECT  30.96 17.923 30.978 17.959 ;
     RECT  32.04 17.549 34.218 17.959 ;
     RECT  2.304 17.707 3.618 18.031 ;
     RECT  4.644 17.95 8.097 18.031 ;
     RECT  9.468 17.725 9.486 18.149 ;
     RECT  30.96 17.959 34.218 18.149 ;
     RECT  35.352 17.803 35.946 18.185 ;
     RECT  10.515 17.609 10.797 18.301 ;
     RECT  10.515 18.301 10.818 18.427 ;
     RECT  30.924 18.427 30.942 18.463 ;
     RECT  10.515 18.427 10.89 18.499 ;
     RECT  31.896 18.149 34.218 18.499 ;
     RECT  30.852 18.463 30.942 18.563 ;
     RECT  10.515 18.499 10.962 18.599 ;
     RECT  2.304 18.031 8.097 18.661 ;
     RECT  2.304 18.661 8.658 18.796 ;
     RECT  31.896 18.499 34.254 18.955 ;
     RECT  2.304 18.796 8.694 19.031 ;
     RECT  35.928 18.185 35.946 19.099 ;
     RECT  31.896 18.955 34.794 19.201 ;
     RECT  2.304 19.031 8.586 19.229 ;
     RECT  31.32 19.201 34.794 19.291 ;
     RECT  35.928 19.099 35.982 19.291 ;
     RECT  31.32 19.291 35.982 19.301 ;
     RECT  35.316 19.301 35.982 19.469 ;
     RECT  2.304 19.229 8.514 19.535 ;
     RECT  31.32 19.301 34.218 19.651 ;
     RECT  2.304 19.535 6.822 19.679 ;
     RECT  7.815 19.535 8.514 19.679 ;
     RECT  2.304 19.679 6.606 19.949 ;
     RECT  2.304 19.949 5.397 20.039 ;
     RECT  3.42 20.039 5.397 20.309 ;
     RECT  7.815 19.679 8.097 20.317 ;
     RECT  35.352 19.469 35.982 20.395 ;
     RECT  30.78 19.651 34.218 20.453 ;
     RECT  3.672 20.309 5.397 20.489 ;
     RECT  6.156 19.949 6.606 20.551 ;
     RECT  7.56 20.317 8.097 20.551 ;
     RECT  35.352 20.395 36.054 20.621 ;
     RECT  6.156 20.551 8.334 20.624 ;
     RECT  4.032 20.489 5.397 20.731 ;
     RECT  6.156 20.624 6.858 20.731 ;
     RECT  4.032 20.731 6.858 20.759 ;
     RECT  2.304 20.039 2.697 20.875 ;
     RECT  31.392 20.453 34.218 20.957 ;
     RECT  31.392 20.957 34.074 21.119 ;
     RECT  7.815 20.624 8.334 21.191 ;
     RECT  35.928 20.621 36.054 21.191 ;
     RECT  2.304 20.875 2.754 21.211 ;
     RECT  7.815 21.191 8.226 21.263 ;
     RECT  2.304 21.211 2.862 21.271 ;
     RECT  4.032 20.759 6.822 21.389 ;
     RECT  30.636 21.271 30.654 21.397 ;
     RECT  31.392 21.119 33.894 21.397 ;
     RECT  2.304 21.271 3.006 21.469 ;
     RECT  4.032 21.389 5.598 21.469 ;
     RECT  30.636 21.397 33.894 21.497 ;
     RECT  35.928 21.191 36.018 21.497 ;
     RECT  35.928 21.497 35.946 21.505 ;
     RECT  7.815 21.263 8.118 21.569 ;
     RECT  35.892 21.505 35.946 21.569 ;
     RECT  35.892 21.569 35.91 21.581 ;
     RECT  2.304 21.469 5.598 21.659 ;
     RECT  31.5 21.497 33.894 21.659 ;
     RECT  34.812 21.403 34.83 21.691 ;
     RECT  6.948 21.541 6.966 21.739 ;
     RECT  7.815 21.569 8.097 21.739 ;
     RECT  6.948 21.739 8.097 21.929 ;
     RECT  30.636 21.497 30.654 21.929 ;
     RECT  31.932 21.659 33.894 22.009 ;
     RECT  34.776 21.691 34.83 22.009 ;
     RECT  2.304 21.659 3.33 22.171 ;
     RECT  31.932 22.009 34.83 22.171 ;
     RECT  2.268 22.171 3.33 22.199 ;
     RECT  4.428 21.659 5.598 22.207 ;
     RECT  7.128 21.929 8.097 22.351 ;
     RECT  31.932 22.171 34.902 22.477 ;
     RECT  2.268 22.199 3.258 22.505 ;
     RECT  10.515 18.599 10.797 22.585 ;
     RECT  4.428 22.207 5.922 22.621 ;
     RECT  10.515 22.585 10.818 22.739 ;
     RECT  31.5 22.477 34.902 22.783 ;
     RECT  35.928 22.351 35.946 22.783 ;
     RECT  31.5 22.783 35.946 22.877 ;
     RECT  4.428 22.621 6.03 22.891 ;
     RECT  4.428 22.891 6.246 23.009 ;
     RECT  31.5 22.877 34.902 23.053 ;
     RECT  2.304 22.505 3.258 23.089 ;
     RECT  35.928 22.877 35.946 23.125 ;
     RECT  4.428 23.009 6.138 23.161 ;
     RECT  7.128 22.351 8.334 23.161 ;
     RECT  30.852 23.053 34.902 23.161 ;
     RECT  30.78 23.161 34.902 23.189 ;
     RECT  7.128 23.161 8.658 23.275 ;
     RECT  4.356 23.161 6.138 23.279 ;
     RECT  6.984 23.275 8.658 23.279 ;
     RECT  30.78 23.189 34.794 23.279 ;
     RECT  4.356 23.279 5.958 23.315 ;
     RECT  35.928 23.125 36.018 23.501 ;
     RECT  2.304 23.089 3.438 23.585 ;
     RECT  4.356 23.315 5.85 23.701 ;
     RECT  9.108 23.431 9.126 23.729 ;
     RECT  31.14 23.279 34.794 23.819 ;
     RECT  3.888 23.701 5.85 23.999 ;
     RECT  4.284 23.999 5.85 24.205 ;
     RECT  31.716 23.819 34.794 24.205 ;
     RECT  35.928 23.501 35.946 24.205 ;
     RECT  6.984 23.279 8.097 24.241 ;
     RECT  4.284 24.205 5.922 24.359 ;
     RECT  31.716 24.205 35.946 24.359 ;
     RECT  4.572 24.359 5.922 24.413 ;
     RECT  4.572 24.413 5.742 24.431 ;
     RECT  9.504 24.241 9.522 24.539 ;
     RECT  6.84 24.241 8.406 24.637 ;
     RECT  6.48 24.637 8.694 24.737 ;
     RECT  32.115 24.359 35.946 24.763 ;
     RECT  6.48 24.737 8.097 24.773 ;
     RECT  30.852 24.637 30.87 24.809 ;
     RECT  32.115 24.763 35.982 25.007 ;
     RECT  32.115 25.007 35.946 25.277 ;
     RECT  3.78 24.763 3.798 25.321 ;
     RECT  4.644 24.431 5.742 25.321 ;
     RECT  6.48 24.773 6.534 25.321 ;
     RECT  3.744 25.321 6.534 25.439 ;
     RECT  3.744 25.439 6.354 25.511 ;
     RECT  32.115 25.277 34.362 25.555 ;
     RECT  35.352 25.277 35.946 25.619 ;
     RECT  2.304 23.585 2.697 25.723 ;
     RECT  7.452 24.773 8.097 25.861 ;
     RECT  9.684 25.321 9.702 25.861 ;
     RECT  10.515 22.739 10.797 25.861 ;
     RECT  9.684 25.861 10.797 25.979 ;
     RECT  7.092 25.861 8.19 26.051 ;
     RECT  2.304 25.723 2.79 26.059 ;
     RECT  31.716 25.555 34.362 26.059 ;
     RECT  35.352 25.619 35.406 26.059 ;
     RECT  4.356 25.511 6.354 26.221 ;
     RECT  7.092 26.051 8.097 26.221 ;
     RECT  4.356 26.221 8.097 26.249 ;
     RECT  6.228 26.249 8.097 26.357 ;
     RECT  6.372 26.357 8.097 26.429 ;
     RECT  2.304 26.059 3.114 26.527 ;
     RECT  31.716 26.059 35.406 26.539 ;
     RECT  30.78 26.401 30.87 26.599 ;
     RECT  30.78 26.599 30.942 26.663 ;
     RECT  31.716 26.539 35.946 26.663 ;
     RECT  2.304 26.527 3.51 26.699 ;
     RECT  6.552 26.429 6.93 26.699 ;
     RECT  3.492 26.699 3.51 26.731 ;
     RECT  4.356 26.249 5.397 26.731 ;
     RECT  3.492 26.731 5.397 26.765 ;
     RECT  9.72 25.979 10.797 26.789 ;
     RECT  30.924 26.663 30.942 26.789 ;
     RECT  7.668 26.429 8.097 26.941 ;
     RECT  31.716 26.663 35.37 26.941 ;
     RECT  2.304 26.699 2.697 27.019 ;
     RECT  31.572 26.941 35.37 27.059 ;
     RECT  7.668 26.941 8.37 27.329 ;
     RECT  0.216 27.337 0.234 27.389 ;
     RECT  6.84 26.699 6.93 27.403 ;
     RECT  7.668 27.329 8.334 27.403 ;
     RECT  31.932 27.059 35.37 27.409 ;
     RECT  2.268 27.019 2.697 27.437 ;
     RECT  2.304 27.437 2.697 27.481 ;
     RECT  3.996 26.765 5.397 27.481 ;
     RECT  6.84 27.403 8.334 27.481 ;
     RECT  31.932 27.409 35.406 27.533 ;
     RECT  31.932 27.533 34.83 27.599 ;
     RECT  3.996 27.481 8.334 27.635 ;
     RECT  31.932 27.599 34.794 27.671 ;
     RECT  2.304 27.481 3.222 27.691 ;
     RECT  3.996 27.635 6.138 27.691 ;
     RECT  9.36 27.301 9.378 27.715 ;
     RECT  9.36 27.715 9.594 27.869 ;
     RECT  9.36 27.869 9.558 27.985 ;
     RECT  30.852 27.571 30.87 27.985 ;
     RECT  2.304 27.691 6.138 28.013 ;
     RECT  9.072 27.985 9.558 28.139 ;
     RECT  7.02 27.635 8.334 28.147 ;
     RECT  30.78 27.985 30.87 28.183 ;
     RECT  30.78 28.183 30.906 28.319 ;
     RECT  4.428 28.013 6.138 28.363 ;
     RECT  7.02 28.147 8.694 28.363 ;
     RECT  4.428 28.363 8.694 28.409 ;
     RECT  2.304 28.013 3.366 28.411 ;
     RECT  30.78 28.319 30.87 28.481 ;
     RECT  2.232 28.411 3.366 28.553 ;
     RECT  4.428 28.409 6.138 28.553 ;
     RECT  31.968 27.671 34.794 28.651 ;
     RECT  2.268 28.553 3.366 28.787 ;
     RECT  31.932 28.651 34.794 28.795 ;
     RECT  35.928 27.985 35.982 28.795 ;
     RECT  6.876 28.409 8.334 28.859 ;
     RECT  9.54 28.139 9.558 28.921 ;
     RECT  9.54 28.921 9.738 28.949 ;
     RECT  10.515 26.789 10.797 28.957 ;
     RECT  9.72 28.949 9.738 29.057 ;
     RECT  10.515 28.957 10.818 29.057 ;
     RECT  30.852 28.481 30.87 29.057 ;
     RECT  31.932 28.795 35.982 29.165 ;
     RECT  4.428 28.553 5.397 29.191 ;
     RECT  6.12 28.553 6.138 29.191 ;
     RECT  6.876 28.859 8.097 29.191 ;
     RECT  31.932 29.165 35.946 29.227 ;
     RECT  2.304 28.787 3.366 29.335 ;
     RECT  4.284 29.191 5.397 29.363 ;
     RECT  4.428 29.363 5.397 29.371 ;
     RECT  6.12 29.191 8.097 29.371 ;
     RECT  0.252 29.467 0.27 29.597 ;
     RECT  30.78 29.263 30.798 29.902 ;
     RECT  30.78 29.902 30.834 29.903 ;
     RECT  4.428 29.371 8.097 29.911 ;
     RECT  4.428 29.911 8.19 29.939 ;
     RECT  10.515 29.057 10.797 30.001 ;
     RECT  31.68 29.227 35.946 30.001 ;
     RECT  31.572 30.001 35.946 30.091 ;
     RECT  30.816 29.903 30.834 30.109 ;
     RECT  31.572 30.091 35.982 30.109 ;
     RECT  30.816 30.109 35.982 30.11 ;
     RECT  2.304 29.335 3.474 30.145 ;
     RECT  10.515 30.001 10.854 30.173 ;
     RECT  4.644 29.939 8.19 30.209 ;
     RECT  30.852 30.11 35.982 30.209 ;
     RECT  2.304 30.145 3.654 30.283 ;
     RECT  31.572 30.209 35.982 30.299 ;
     RECT  31.932 30.299 35.982 30.479 ;
     RECT  2.268 30.283 3.654 30.605 ;
     RECT  4.644 30.209 5.397 30.685 ;
     RECT  6.12 30.209 8.19 30.713 ;
     RECT  7.632 30.713 8.19 30.749 ;
     RECT  35.928 30.479 35.982 30.763 ;
     RECT  4.572 30.685 5.397 30.847 ;
     RECT  7.704 30.749 8.19 30.847 ;
     RECT  9.432 30.721 9.45 30.847 ;
     RECT  2.304 30.605 3.654 30.875 ;
     RECT  35.928 30.763 36.45 30.893 ;
     RECT  30.78 30.847 30.798 30.947 ;
     RECT  7.704 30.847 9.45 30.955 ;
     RECT  4.464 30.847 5.397 30.991 ;
     RECT  6.12 30.713 6.858 30.991 ;
     RECT  3.78 30.991 6.858 31.109 ;
     RECT  7.704 30.955 9.63 31.109 ;
     RECT  10.515 30.173 10.797 31.117 ;
     RECT  29.415 2.413 29.697 31.117 ;
     RECT  6.804 31.109 6.858 31.181 ;
     RECT  3.78 31.109 5.958 31.217 ;
     RECT  6.84 31.181 6.858 31.217 ;
     RECT  7.704 31.109 8.802 31.217 ;
     RECT  10.515 31.117 10.854 31.253 ;
     RECT  29.415 31.117 30.222 31.487 ;
     RECT  3.78 31.217 5.922 31.649 ;
     RECT  2.304 30.875 3.006 31.675 ;
     RECT  0.252 30.763 0.27 31.709 ;
     RECT  31.932 30.479 34.902 31.729 ;
     RECT  35.928 30.893 35.982 31.729 ;
     RECT  31.932 31.729 35.982 31.793 ;
     RECT  2.304 31.675 3.33 31.867 ;
     RECT  31.932 31.793 35.946 31.891 ;
     RECT  2.268 31.867 3.33 31.955 ;
     RECT  7.704 31.217 8.658 31.999 ;
     RECT  6.912 31.999 8.658 32.071 ;
     RECT  4.068 31.649 5.922 32.269 ;
     RECT  6.876 32.071 9.234 32.269 ;
     RECT  4.068 32.269 9.234 32.333 ;
     RECT  2.304 31.955 3.294 32.459 ;
     RECT  4.068 32.333 8.478 32.459 ;
     RECT  31.788 31.891 35.946 32.459 ;
     RECT  31.824 32.459 35.946 32.575 ;
     RECT  31.824 32.575 35.982 32.639 ;
     RECT  29.415 31.487 29.697 32.737 ;
     RECT  35.928 32.639 35.982 32.773 ;
     RECT  6.732 32.459 8.19 32.873 ;
     RECT  4.068 32.459 5.814 32.909 ;
     RECT  4.968 32.909 5.814 32.999 ;
     RECT  4.068 32.909 4.086 33.007 ;
     RECT  9.432 32.611 9.45 33.007 ;
     RECT  29.415 32.737 30.222 33.007 ;
     RECT  3.888 33.007 4.086 33.071 ;
     RECT  6.84 32.873 8.19 33.071 ;
     RECT  29.415 33.007 30.87 33.107 ;
     RECT  9.432 33.007 9.63 33.179 ;
     RECT  35.928 32.773 36.018 33.197 ;
     RECT  31.824 32.639 34.83 33.269 ;
     RECT  30.78 33.107 30.87 33.341 ;
     RECT  5.004 32.999 5.814 33.413 ;
     RECT  30.78 33.341 30.798 33.413 ;
     RECT  3.888 33.071 3.978 33.449 ;
     RECT  2.304 32.459 3.114 33.511 ;
     RECT  3.888 33.449 3.906 33.511 ;
     RECT  0.252 33.499 0.27 33.629 ;
     RECT  9.18 33.583 9.198 33.691 ;
     RECT  2.304 33.511 3.906 33.809 ;
     RECT  7.056 33.071 8.154 33.853 ;
     RECT  5.115 33.413 5.814 33.925 ;
     RECT  35.928 33.197 35.946 33.961 ;
     RECT  2.304 33.809 3.438 33.979 ;
     RECT  2.268 33.979 3.438 34.079 ;
     RECT  5.115 33.925 6.174 34.079 ;
     RECT  7.02 33.853 8.154 34.115 ;
     RECT  9.144 33.691 9.198 34.151 ;
     RECT  31.932 33.269 34.83 34.151 ;
     RECT  5.115 34.079 5.994 34.159 ;
     RECT  4.716 34.159 5.994 34.205 ;
     RECT  35.928 33.961 36.018 34.205 ;
     RECT  2.268 34.079 2.79 34.223 ;
     RECT  7.236 34.115 8.154 34.231 ;
     RECT  32.004 34.151 34.83 34.315 ;
     RECT  7.236 34.231 8.37 34.349 ;
     RECT  2.304 34.223 2.79 34.385 ;
     RECT  21.315 10.859 21.597 34.429 ;
     RECT  30.852 34.393 30.87 34.501 ;
     RECT  9.18 34.151 9.198 34.529 ;
     RECT  5.115 34.205 5.994 34.619 ;
     RECT  30.78 34.501 30.87 34.727 ;
     RECT  32.004 34.315 34.902 34.771 ;
     RECT  35.928 34.205 35.982 34.771 ;
     RECT  7.236 34.349 8.334 34.861 ;
     RECT  21.096 34.429 21.597 34.889 ;
     RECT  32.004 34.771 35.982 34.961 ;
     RECT  6.804 34.861 8.334 35.041 ;
     RECT  2.304 34.385 2.697 35.131 ;
     RECT  9.144 35.041 9.162 35.159 ;
     RECT  3.672 34.771 3.69 35.167 ;
     RECT  2.268 35.131 2.697 35.195 ;
     RECT  3.672 35.167 3.978 35.195 ;
     RECT  2.304 35.195 2.697 35.311 ;
     RECT  3.96 35.195 3.978 35.323 ;
     RECT  5.115 34.619 5.778 35.323 ;
     RECT  30.78 34.727 30.798 35.339 ;
     RECT  32.04 34.961 35.982 35.339 ;
     RECT  3.96 35.323 5.778 35.357 ;
     RECT  6.768 35.041 8.334 35.357 ;
     RECT  2.304 35.311 3.078 35.429 ;
     RECT  4.644 35.357 5.778 35.545 ;
     RECT  4.644 35.545 6.03 35.563 ;
     RECT  7.056 35.357 8.334 35.699 ;
     RECT  9.18 35.581 9.234 35.879 ;
     RECT  31.248 35.581 31.266 36.085 ;
     RECT  32.04 35.339 34.254 36.085 ;
     RECT  35.352 35.339 35.982 36.085 ;
     RECT  4.644 35.563 6.246 36.121 ;
     RECT  4.644 36.121 7.038 36.211 ;
     RECT  2.304 35.429 2.97 36.235 ;
     RECT  4.572 36.211 7.038 36.269 ;
     RECT  31.248 36.085 35.982 36.283 ;
     RECT  9.432 36.121 9.45 36.311 ;
     RECT  30.852 36.283 35.982 36.509 ;
     RECT  31.788 36.509 35.982 36.545 ;
     RECT  4.572 36.269 6.21 36.581 ;
     RECT  2.304 36.235 3.294 36.625 ;
     RECT  4.572 36.581 5.397 36.625 ;
     RECT  6.948 36.269 7.038 36.661 ;
     RECT  7.815 35.699 8.334 36.661 ;
     RECT  2.304 36.625 5.397 36.715 ;
     RECT  13.215 2.413 13.497 36.751 ;
     RECT  21.315 34.889 21.597 36.751 ;
     RECT  13.104 36.751 13.497 36.797 ;
     RECT  21.204 36.751 21.597 36.797 ;
     RECT  2.268 36.715 5.397 36.815 ;
     RECT  31.968 36.545 35.982 36.887 ;
     RECT  14.832 36.763 14.85 36.893 ;
     RECT  22.824 36.763 22.842 36.893 ;
     RECT  6.948 36.661 8.334 36.931 ;
     RECT  6.12 36.581 6.21 37.049 ;
     RECT  6.948 36.931 8.514 37.049 ;
     RECT  6.948 37.049 8.19 37.093 ;
     RECT  2.304 36.815 5.397 37.319 ;
     RECT  6.804 37.093 8.19 37.319 ;
     RECT  9.36 37.201 9.522 37.319 ;
     RECT  35.352 36.887 35.982 37.387 ;
     RECT  9.504 37.319 9.522 37.391 ;
     RECT  4.644 37.319 5.397 37.471 ;
     RECT  35.352 37.387 36.018 37.499 ;
     RECT  2.304 37.319 3.762 37.589 ;
     RECT  30.78 36.553 30.798 37.633 ;
     RECT  35.352 37.499 35.982 37.697 ;
     RECT  31.968 36.887 34.326 37.723 ;
     RECT  35.352 37.697 35.946 37.723 ;
     RECT  31.968 37.723 35.946 37.741 ;
     RECT  31.68 37.741 35.946 37.769 ;
     RECT  6.804 37.319 6.858 37.831 ;
     RECT  6.768 37.831 6.858 37.859 ;
     RECT  4.644 37.471 5.958 37.939 ;
     RECT  6.768 37.859 6.822 37.939 ;
     RECT  30.78 37.633 30.87 38.039 ;
     RECT  31.68 37.769 35.37 38.048 ;
     RECT  7.668 37.319 8.19 38.281 ;
     RECT  2.304 37.589 3.69 38.347 ;
     RECT  2.268 38.347 3.69 38.371 ;
     RECT  4.644 37.939 6.822 38.371 ;
     RECT  30.852 38.039 30.87 38.371 ;
     RECT  31.68 38.048 34.326 38.371 ;
     RECT  2.268 38.371 6.822 38.669 ;
     RECT  30.852 38.371 34.326 38.669 ;
     RECT  2.268 38.669 4.122 38.717 ;
     RECT  30.852 38.669 30.87 38.741 ;
     RECT  4.896 38.669 6.822 38.821 ;
     RECT  7.668 38.281 8.478 38.821 ;
     RECT  2.268 38.717 4.05 38.861 ;
     RECT  4.896 38.821 6.858 38.923 ;
     RECT  7.668 38.821 8.514 38.923 ;
     RECT  31.932 38.669 34.326 39.011 ;
     RECT  4.896 38.923 8.514 39.119 ;
     RECT  4.896 39.119 8.442 39.209 ;
     RECT  35.316 38.048 35.37 39.209 ;
     RECT  35.352 39.209 35.37 39.499 ;
     RECT  2.304 38.861 4.05 39.515 ;
     RECT  30.78 39.091 30.798 39.523 ;
     RECT  31.932 39.011 34.218 39.631 ;
     RECT  4.896 39.209 8.262 39.721 ;
     RECT  4.752 39.721 8.262 39.749 ;
     RECT  31.896 39.631 34.218 39.785 ;
     RECT  35.352 39.499 35.406 39.787 ;
     RECT  4.752 39.749 6.03 39.869 ;
     RECT  32.076 39.785 34.218 39.979 ;
     RECT  35.352 39.787 35.946 39.979 ;
     RECT  32.076 39.979 35.946 40.019 ;
     RECT  32.115 40.019 35.946 40.127 ;
     RECT  10.515 31.253 10.797 40.171 ;
     RECT  30.78 39.523 30.87 40.171 ;
     RECT  9.108 40.171 9.126 40.261 ;
     RECT  6.804 39.749 8.262 40.289 ;
     RECT  9.108 40.261 9.306 40.289 ;
     RECT  30.78 40.171 30.942 40.289 ;
     RECT  9.288 40.289 9.306 40.361 ;
     RECT  0.216 40.267 0.234 40.397 ;
     RECT  2.304 39.515 3.69 40.405 ;
     RECT  35.928 40.127 35.946 40.459 ;
     RECT  10.515 40.171 10.854 40.469 ;
     RECT  35.928 40.459 35.982 40.603 ;
     RECT  5.04 39.869 6.03 40.711 ;
     RECT  6.804 40.289 8.097 40.711 ;
     RECT  30.78 40.289 30.906 41.071 ;
     RECT  35.928 40.603 36.018 41.083 ;
     RECT  5.04 40.711 8.097 41.107 ;
     RECT  4.86 41.107 8.097 41.251 ;
     RECT  30.78 41.071 31.266 41.251 ;
     RECT  32.115 40.127 34.794 41.251 ;
     RECT  4.716 41.251 8.298 41.369 ;
     RECT  4.86 41.369 8.298 41.791 ;
     RECT  35.928 41.083 36.054 41.864 ;
     RECT  30.78 41.251 34.794 41.899 ;
     RECT  30.78 41.899 34.83 41.909 ;
     RECT  2.304 40.405 3.798 42.025 ;
     RECT  13.215 36.797 13.497 42.025 ;
     RECT  4.86 41.791 8.802 42.061 ;
     RECT  13.104 42.025 13.497 42.077 ;
     RECT  14.832 41.947 14.85 42.077 ;
     RECT  22.824 41.947 22.842 42.077 ;
     RECT  2.304 42.025 4.014 42.091 ;
     RECT  4.86 42.061 8.982 42.179 ;
     RECT  4.86 42.179 8.586 42.215 ;
     RECT  2.268 42.091 4.014 42.287 ;
     RECT  5.115 42.215 8.586 42.449 ;
     RECT  9.468 42.331 9.486 42.449 ;
     RECT  10.515 40.469 10.797 42.457 ;
     RECT  10.515 42.457 10.926 42.557 ;
     RECT  35.928 41.864 35.982 42.605 ;
     RECT  10.515 42.557 10.818 42.629 ;
     RECT  35.928 42.605 35.946 42.715 ;
     RECT  31.68 41.909 34.83 42.719 ;
     RECT  2.304 42.287 4.014 42.727 ;
     RECT  31.68 42.719 34.254 42.989 ;
     RECT  5.115 42.449 8.334 43.033 ;
     RECT  2.304 42.727 4.266 43.105 ;
     RECT  5.076 43.033 8.334 43.105 ;
     RECT  30.78 41.909 30.87 43.141 ;
     RECT  31.68 42.989 34.218 43.141 ;
     RECT  2.304 43.105 8.334 43.169 ;
     RECT  30.78 43.141 34.218 43.169 ;
     RECT  31.32 43.169 34.218 43.331 ;
     RECT  2.304 43.169 8.097 43.529 ;
     RECT  35.892 42.715 35.946 43.531 ;
     RECT  4.248 43.529 8.097 43.709 ;
     RECT  32.115 43.331 34.218 43.843 ;
     RECT  35.352 43.531 35.946 43.867 ;
     RECT  10.515 42.629 10.797 44.041 ;
     RECT  31.32 43.331 31.338 44.077 ;
     RECT  32.115 43.843 34.254 44.077 ;
     RECT  9.828 44.041 10.797 44.141 ;
     RECT  31.32 44.077 34.254 44.149 ;
     RECT  35.352 43.867 36.018 44.149 ;
     RECT  30.852 44.149 36.018 44.249 ;
     RECT  2.304 43.529 3.33 44.311 ;
     RECT  4.86 43.709 8.097 44.761 ;
     RECT  9.288 44.617 9.306 44.789 ;
     RECT  2.304 44.311 3.69 44.827 ;
     RECT  2.268 44.827 3.69 44.879 ;
     RECT  31.716 44.249 34.218 44.951 ;
     RECT  3.636 44.879 3.69 44.971 ;
     RECT  4.608 44.761 8.154 44.971 ;
     RECT  3.636 44.971 8.154 45.005 ;
     RECT  32.112 44.951 34.218 45.163 ;
     RECT  35.352 44.249 36.018 45.163 ;
     RECT  3.996 45.005 8.154 45.193 ;
     RECT  2.268 44.879 2.754 45.257 ;
     RECT  3.996 45.193 8.226 45.419 ;
     RECT  32.112 45.163 36.018 45.599 ;
     RECT  3.996 45.419 6.138 45.761 ;
     RECT  32.112 45.599 34.794 45.769 ;
     RECT  6.912 45.419 8.226 45.805 ;
     RECT  30.852 44.249 30.87 45.869 ;
     RECT  3.996 45.761 5.958 45.931 ;
     RECT  3.708 45.931 5.958 45.959 ;
     RECT  2.304 45.257 2.754 45.995 ;
     RECT  30.78 46.003 30.798 46.103 ;
     RECT  6.912 45.805 8.334 46.111 ;
     RECT  35.892 45.599 36.018 46.123 ;
     RECT  3.708 45.959 5.85 46.139 ;
     RECT  6.912 46.111 9.054 46.229 ;
     RECT  2.376 45.995 2.754 46.267 ;
     RECT  32.04 45.769 34.794 46.273 ;
     RECT  10.515 44.141 10.797 46.381 ;
     RECT  10.515 46.381 10.854 46.499 ;
     RECT  2.376 46.267 2.79 46.507 ;
     RECT  6.912 46.229 8.586 46.535 ;
     RECT  0.216 46.411 0.234 46.541 ;
     RECT  35.892 46.123 36.09 46.679 ;
     RECT  2.376 46.507 3.078 46.747 ;
     RECT  6.984 46.535 8.586 46.781 ;
     RECT  4.248 46.139 5.85 46.849 ;
     RECT  2.304 46.747 3.078 46.885 ;
     RECT  4.248 46.849 6.174 46.885 ;
     RECT  32.004 46.273 34.794 46.939 ;
     RECT  6.984 46.781 8.118 47.111 ;
     RECT  30.78 47.047 30.798 47.147 ;
     RECT  29.415 33.107 29.697 47.155 ;
     RECT  2.304 46.885 6.174 47.191 ;
     RECT  35.892 46.679 36.018 47.219 ;
     RECT  0.252 47.131 0.27 47.261 ;
     RECT  32.004 46.939 34.83 47.419 ;
     RECT  35.892 47.219 35.946 47.419 ;
     RECT  32.004 47.419 35.946 47.425 ;
     RECT  2.304 47.191 6.246 47.461 ;
     RECT  6.984 47.111 8.097 47.461 ;
     RECT  29.415 47.155 30.222 47.579 ;
     RECT  31.716 47.425 35.946 47.579 ;
     RECT  2.304 47.461 8.097 47.651 ;
     RECT  2.304 47.651 3.654 47.849 ;
     RECT  4.392 47.651 8.097 47.849 ;
     RECT  8.856 47.929 8.874 48.029 ;
     RECT  2.304 47.849 3.258 48.043 ;
     RECT  2.268 48.043 3.258 48.263 ;
     RECT  4.824 47.849 8.097 48.271 ;
     RECT  4.824 48.271 8.262 48.461 ;
     RECT  32.115 47.579 35.946 48.505 ;
     RECT  6.696 48.461 8.262 48.557 ;
     RECT  4.824 48.461 5.706 48.631 ;
     RECT  6.696 48.557 8.154 48.659 ;
     RECT  30.78 47.965 30.87 48.766 ;
     RECT  30.78 48.766 30.906 48.839 ;
     RECT  30.888 48.839 30.906 48.929 ;
     RECT  31.932 48.505 35.946 48.929 ;
     RECT  35.928 48.929 35.946 49.037 ;
     RECT  4.68 48.631 5.706 49.045 ;
     RECT  2.304 48.263 3.258 49.081 ;
     RECT  9.18 48.361 9.198 49.081 ;
     RECT  10.515 46.499 10.797 49.081 ;
     RECT  2.304 49.081 3.366 49.199 ;
     RECT  9.18 49.081 10.797 49.199 ;
     RECT  4.536 49.045 5.706 49.207 ;
     RECT  6.696 48.659 8.097 49.207 ;
     RECT  10.515 49.199 10.797 49.207 ;
     RECT  31.932 48.929 35.046 49.207 ;
     RECT  10.515 49.207 10.854 49.307 ;
     RECT  31.86 49.207 35.046 49.351 ;
     RECT  4.212 49.207 8.097 49.549 ;
     RECT  4.212 49.549 8.37 49.577 ;
     RECT  31.788 49.351 35.046 49.621 ;
     RECT  31.716 49.621 35.046 49.675 ;
     RECT  7.308 49.577 8.37 49.711 ;
     RECT  4.212 49.577 6.426 49.819 ;
     RECT  31.716 49.675 35.37 49.819 ;
     RECT  36.468 49.339 36.486 49.819 ;
     RECT  7.308 49.711 9.126 49.847 ;
     RECT  30.852 49.747 30.87 49.981 ;
     RECT  2.304 49.199 2.754 50.125 ;
     RECT  3.636 49.819 6.426 50.125 ;
     RECT  2.304 50.125 6.426 50.189 ;
     RECT  9.108 49.847 9.126 50.251 ;
     RECT  7.308 49.847 8.298 50.279 ;
     RECT  9.108 50.251 9.306 50.279 ;
     RECT  5.115 50.189 6.426 50.315 ;
     RECT  9.288 50.279 9.306 50.351 ;
     RECT  7.308 50.279 8.262 50.431 ;
     RECT  30.78 49.981 30.87 50.431 ;
     RECT  2.304 50.189 4.338 50.549 ;
     RECT  30.78 50.431 30.906 50.585 ;
     RECT  0.252 50.491 0.27 50.621 ;
     RECT  30.78 50.585 30.87 50.657 ;
     RECT  2.304 50.549 3.114 50.779 ;
     RECT  2.268 50.779 3.114 50.927 ;
     RECT  4.068 50.549 4.338 50.971 ;
     RECT  5.115 50.315 6.282 50.971 ;
     RECT  4.068 50.971 6.282 51.163 ;
     RECT  7.092 50.431 8.262 51.163 ;
     RECT  2.304 50.927 3.114 51.269 ;
     RECT  4.068 51.163 8.262 51.331 ;
     RECT  9.036 51.241 9.054 51.331 ;
     RECT  4.068 51.331 9.054 51.359 ;
     RECT  4.068 51.359 8.478 51.511 ;
     RECT  3.996 51.511 8.478 51.539 ;
     RECT  3.996 51.539 5.922 51.629 ;
     RECT  2.304 51.269 2.697 51.773 ;
     RECT  3.996 51.629 5.85 51.781 ;
     RECT  3.6 51.781 5.85 51.899 ;
     RECT  2.34 51.773 2.697 51.935 ;
     RECT  2.376 51.935 2.697 52.007 ;
     RECT  31.716 49.819 36.486 52.051 ;
     RECT  3.96 51.899 5.85 52.079 ;
     RECT  3.96 52.079 3.978 52.169 ;
     RECT  31.464 52.051 36.486 52.169 ;
     RECT  6.84 51.539 8.478 52.241 ;
     RECT  7.632 52.241 8.478 52.285 ;
     RECT  6.84 52.241 6.858 52.313 ;
     RECT  7.632 52.285 8.622 52.313 ;
     RECT  32.115 52.169 36.486 52.349 ;
     RECT  7.815 52.313 8.622 52.439 ;
     RECT  32.115 52.349 35.982 52.439 ;
     RECT  33.156 52.439 35.982 52.619 ;
     RECT  33.264 52.619 35.982 52.745 ;
     RECT  33.444 52.745 35.982 52.979 ;
     RECT  35.928 52.979 35.982 53.159 ;
     RECT  33.588 52.979 35.082 53.249 ;
     RECT  33.588 53.249 34.506 53.285 ;
     RECT  34.488 53.285 34.506 53.429 ;
     RECT  35.928 53.159 35.946 53.519 ;
     RECT  33.588 53.285 33.606 53.555 ;
     RECT  2.415 52.007 2.697 53.747 ;
     RECT  5.115 52.079 5.397 53.747 ;
     RECT  7.815 52.439 8.097 53.747 ;
     RECT  10.515 49.307 10.797 53.747 ;
     RECT  13.215 42.077 13.497 53.747 ;
     RECT  15.915 2.413 16.197 53.747 ;
     RECT  18.615 2.413 18.897 53.747 ;
     RECT  21.315 36.797 21.597 53.747 ;
     RECT  24.015 2.413 24.297 53.747 ;
     RECT  26.715 2.413 26.997 53.747 ;
     RECT  29.415 47.579 29.697 53.747 ;
     RECT  32.115 52.439 32.397 53.747 ;
     RECT  2.415 53.747 2.505 54.017 ;
     RECT  5.115 53.747 5.205 54.017 ;
     RECT  7.815 53.747 7.905 54.017 ;
     RECT  10.515 53.747 10.605 54.017 ;
     RECT  13.215 53.747 13.305 54.017 ;
     RECT  15.915 53.747 16.005 54.017 ;
     RECT  18.615 53.747 18.705 54.017 ;
     RECT  21.315 53.747 21.405 54.017 ;
     RECT  24.015 53.747 24.105 54.017 ;
     RECT  26.715 53.747 26.805 54.017 ;
     RECT  29.415 53.747 29.505 54.017 ;
     RECT  32.115 53.747 32.205 54.017 ;
    LAYER M4 ;
     RECT  0.156 4.416 0.275 51.816 ;
     RECT  0.275 4.416 2.408 51.624 ;
     RECT  2.408 2.148 2.512 54.012 ;
     RECT  2.512 2.418 2.704 53.742 ;
     RECT  2.704 19.584 2.765 21.432 ;
     RECT  2.704 25.728 2.765 31.704 ;
     RECT  2.704 33.6 2.765 33.672 ;
     RECT  2.704 36.24 2.765 37.464 ;
     RECT  2.704 40.128 2.765 40.392 ;
     RECT  2.704 44.976 2.765 47.16 ;
     RECT  2.704 49.2 2.765 50.616 ;
     RECT  2.765 19.584 2.801 19.992 ;
     RECT  2.765 25.728 2.801 29.592 ;
     RECT  2.765 30.576 2.801 31.704 ;
     RECT  2.704 43.776 2.801 43.896 ;
     RECT  2.765 46.272 2.801 47.16 ;
     RECT  2.704 6.816 2.837 8.472 ;
     RECT  2.704 10.896 2.837 13.08 ;
     RECT  2.704 5.04 2.873 5.064 ;
     RECT  2.765 21.216 2.873 21.24 ;
     RECT  2.704 38.496 2.873 39.048 ;
     RECT  2.837 6.816 2.981 7.656 ;
     RECT  2.765 50.592 2.981 50.616 ;
     RECT  2.704 9.504 3.017 9.528 ;
     RECT  2.704 17.712 3.017 18.168 ;
     RECT  2.765 33.6 3.017 33.624 ;
     RECT  2.801 46.512 3.089 47.16 ;
     RECT  2.801 26.064 3.125 28.488 ;
     RECT  2.837 11.136 3.197 11.976 ;
     RECT  2.704 23.328 3.197 23.352 ;
     RECT  2.801 30.576 3.197 30.6 ;
     RECT  2.873 38.496 3.197 38.712 ;
     RECT  2.837 13.056 3.269 13.08 ;
     RECT  2.801 29.568 3.269 29.592 ;
     RECT  3.125 26.736 3.305 28.488 ;
     RECT  2.765 36.24 3.305 36.936 ;
     RECT  2.801 31.68 3.341 31.704 ;
     RECT  2.801 43.776 3.341 43.8 ;
     RECT  2.765 40.368 3.413 40.392 ;
     RECT  3.089 47.136 3.413 47.16 ;
     RECT  2.704 41.616 3.809 41.64 ;
     RECT  2.801 19.968 4.061 19.992 ;
     RECT  2.765 44.976 4.133 45 ;
     RECT  2.981 7.632 4.273 7.656 ;
     RECT  3.769 9.072 4.273 9.096 ;
     RECT  3.877 15.024 4.309 15.048 ;
     RECT  4.021 21.12 4.417 21.144 ;
     RECT  3.949 35.328 4.561 35.352 ;
     RECT  4.237 46.848 4.625 46.872 ;
     RECT  3.769 24.768 4.633 24.792 ;
     RECT  4.625 46.704 4.652 46.872 ;
     RECT  4.652 46.32 4.693 46.872 ;
     RECT  3.913 16.656 4.741 16.68 ;
     RECT  3.017 17.712 4.741 17.736 ;
     RECT  3.197 38.688 4.777 38.712 ;
     RECT  4.633 24.384 4.789 24.792 ;
     RECT  4.741 16.656 4.885 17.736 ;
     RECT  4.345 18.768 4.885 18.792 ;
     RECT  4.813 30.576 4.957 30.6 ;
     RECT  4.309 14.256 4.993 15.048 ;
     RECT  4.885 16.656 4.993 18.792 ;
     RECT  4.345 5.472 5.108 5.496 ;
     RECT  4.273 7.632 5.108 9.096 ;
     RECT  4.885 10.896 5.108 10.92 ;
     RECT  4.844 12.768 5.108 12.792 ;
     RECT  4.993 14.256 5.108 18.792 ;
     RECT  4.417 21.12 5.108 22.056 ;
     RECT  4.345 23.232 5.108 23.256 ;
     RECT  4.789 24.384 5.108 25.224 ;
     RECT  3.305 26.736 5.108 26.76 ;
     RECT  3.305 28.464 5.108 28.488 ;
     RECT  4.957 30.336 5.108 30.6 ;
     RECT  4.693 34.176 5.108 34.2 ;
     RECT  4.561 35.328 5.108 36.264 ;
     RECT  4.777 38.4 5.108 38.712 ;
     RECT  4.741 39.84 5.108 39.864 ;
     RECT  4.693 45.696 5.108 46.872 ;
     RECT  4.525 51.744 5.108 51.768 ;
     RECT  5.108 2.148 5.212 54.012 ;
     RECT  5.212 2.418 5.404 53.742 ;
     RECT  5.404 20.592 5.465 22.056 ;
     RECT  5.404 17.088 5.645 19.368 ;
     RECT  5.404 7.584 5.753 7.944 ;
     RECT  5.404 10.896 5.753 11.352 ;
     RECT  5.645 17.664 5.789 19.368 ;
     RECT  5.404 33.072 5.825 33.096 ;
     RECT  5.789 18.768 5.833 19.368 ;
     RECT  5.404 5.472 5.897 5.496 ;
     RECT  5.465 20.592 5.933 21.144 ;
     RECT  5.404 38.4 5.969 39.384 ;
     RECT  5.404 28.368 6.005 28.488 ;
     RECT  5.404 15.84 6.041 15.864 ;
     RECT  5.404 45.696 6.149 45.72 ;
     RECT  5.404 35.568 6.293 36.936 ;
     RECT  5.404 29.616 6.323 30.6 ;
     RECT  5.969 38.4 6.371 39.144 ;
     RECT  5.404 40.464 6.371 40.776 ;
     RECT  5.404 44.112 6.371 44.472 ;
     RECT  5.933 20.592 6.401 21.096 ;
     RECT  6.005 28.368 6.473 28.392 ;
     RECT  5.404 24.384 6.505 24.408 ;
     RECT  5.404 47.856 6.649 47.88 ;
     RECT  6.397 50.256 6.649 50.28 ;
     RECT  5.404 42.096 6.793 42.12 ;
     RECT  6.541 26.544 6.829 26.568 ;
     RECT  6.293 35.568 6.829 35.592 ;
     RECT  6.793 42.048 6.865 42.12 ;
     RECT  6.649 49.44 6.937 50.28 ;
     RECT  5.404 51.312 6.937 51.864 ;
     RECT  5.789 17.664 6.973 17.688 ;
     RECT  5.404 23.28 7.117 23.304 ;
     RECT  5.404 46.752 7.117 46.776 ;
     RECT  6.649 47.856 7.117 48.168 ;
     RECT  5.753 10.896 7.141 10.92 ;
     RECT  6.323 29.616 7.225 29.64 ;
     RECT  6.865 41.952 7.261 42.12 ;
     RECT  7.141 10.272 7.333 10.92 ;
     RECT  6.829 35.328 7.333 35.592 ;
     RECT  6.829 33.024 7.369 33.048 ;
     RECT  6.293 36.864 7.429 36.936 ;
     RECT  6.793 38.208 7.429 38.232 ;
     RECT  7.153 39.312 7.429 39.336 ;
     RECT  7.117 22.656 7.585 23.304 ;
     RECT  7.585 22.08 7.628 23.304 ;
     RECT  6.505 24.384 7.628 25.128 ;
     RECT  7.628 22.08 7.669 25.128 ;
     RECT  6.829 26.544 7.669 27.432 ;
     RECT  7.369 32.496 7.669 33.048 ;
     RECT  5.753 7.92 7.808 7.944 ;
     RECT  7.1 9.072 7.808 9.096 ;
     RECT  7.333 10.272 7.808 10.968 ;
     RECT  6.721 13.056 7.808 13.08 ;
     RECT  7.693 14.736 7.808 14.76 ;
     RECT  6.973 17.616 7.808 17.688 ;
     RECT  5.833 18.768 7.808 18.792 ;
     RECT  6.401 20.592 7.808 20.616 ;
     RECT  7.669 22.08 7.808 27.432 ;
     RECT  7.225 29.472 7.808 29.64 ;
     RECT  7.669 31.776 7.808 33.048 ;
     RECT  7.333 34.656 7.808 35.592 ;
     RECT  7.429 36.864 7.808 37.176 ;
     RECT  7.429 38.208 7.808 39.336 ;
     RECT  6.371 40.464 7.808 40.584 ;
     RECT  7.261 41.952 7.808 42.744 ;
     RECT  6.371 44.448 7.808 44.472 ;
     RECT  7.117 46.752 7.808 48.168 ;
     RECT  6.937 49.44 7.808 51.864 ;
     RECT  7.808 2.148 7.912 54.012 ;
     RECT  7.912 2.418 8.104 53.742 ;
     RECT  8.104 27.408 8.165 27.432 ;
     RECT  8.104 14.736 8.201 14.76 ;
     RECT  8.104 10.944 8.243 11.4 ;
     RECT  8.104 34.656 8.243 34.824 ;
     RECT  8.104 46.752 8.243 48.552 ;
     RECT  8.104 51.12 8.243 51.144 ;
     RECT  8.243 48.528 8.284 48.552 ;
     RECT  8.243 34.8 8.345 34.824 ;
     RECT  8.243 46.752 8.597 46.776 ;
     RECT  8.243 11.376 9.452 11.4 ;
     RECT  9.452 10.992 9.539 11.4 ;
     RECT  8.104 36.864 10.508 36.936 ;
     RECT  8.104 41.952 10.508 41.976 ;
     RECT  9.493 51.648 10.508 51.672 ;
     RECT  10.508 2.148 10.612 54.012 ;
     RECT  10.612 2.418 10.804 53.742 ;
     RECT  10.804 36.768 13.208 36.936 ;
     RECT  10.804 42.048 13.208 42.072 ;
     RECT  10.804 51.648 13.208 51.672 ;
     RECT  13.208 2.148 13.312 54.012 ;
     RECT  13.312 2.418 13.504 53.742 ;
     RECT  13.504 42.048 14.821 42.072 ;
     RECT  13.504 36.768 14.861 36.936 ;
     RECT  14.821 41.952 14.861 42.072 ;
     RECT  14.861 36.864 15.908 36.936 ;
     RECT  14.861 41.952 15.908 41.976 ;
     RECT  13.504 51.648 15.908 51.672 ;
     RECT  15.908 2.148 16.012 54.012 ;
     RECT  16.012 2.418 16.204 53.742 ;
     RECT  16.204 36.864 18.608 36.936 ;
     RECT  16.204 41.952 18.608 41.976 ;
     RECT  16.204 51.648 18.608 51.672 ;
     RECT  18.608 2.148 18.712 54.012 ;
     RECT  18.712 2.418 18.904 53.742 ;
     RECT  18.904 36.768 21.308 36.936 ;
     RECT  18.904 42.048 21.308 42.072 ;
     RECT  18.904 51.648 21.308 51.672 ;
     RECT  21.308 2.148 21.412 54.012 ;
     RECT  21.412 2.418 21.604 53.742 ;
     RECT  21.604 42.048 22.813 42.072 ;
     RECT  21.604 36.768 22.853 36.936 ;
     RECT  22.813 41.952 22.853 42.072 ;
     RECT  22.853 36.864 24.008 36.936 ;
     RECT  22.853 41.952 24.008 41.976 ;
     RECT  21.604 51.648 24.008 51.672 ;
     RECT  24.008 2.148 24.112 54.012 ;
     RECT  24.112 2.418 24.304 53.742 ;
     RECT  24.304 36.864 26.708 36.936 ;
     RECT  24.304 41.952 26.708 41.976 ;
     RECT  24.304 51.648 26.708 51.672 ;
     RECT  26.708 2.148 26.812 54.012 ;
     RECT  26.812 2.418 27.004 53.742 ;
     RECT  27.004 36.864 29.408 36.936 ;
     RECT  27.004 41.952 29.408 41.976 ;
     RECT  27.004 51.648 29.408 51.672 ;
     RECT  29.408 2.148 29.512 54.012 ;
     RECT  29.512 2.418 29.704 53.742 ;
     RECT  29.704 42.048 30.769 42.072 ;
     RECT  29.704 36.768 30.809 36.936 ;
     RECT  30.769 41.952 30.809 42.072 ;
     RECT  30.809 41.952 31.957 41.976 ;
     RECT  32.065 27.888 32.108 27.912 ;
     RECT  30.809 36.864 32.108 36.936 ;
     RECT  31.957 41.952 32.108 42.744 ;
     RECT  29.704 51.648 32.108 51.672 ;
     RECT  32.108 2.148 32.212 54.012 ;
     RECT  32.212 2.418 32.404 53.742 ;
     RECT  32.404 28.944 32.609 28.968 ;
     RECT  32.404 40.32 32.825 42.744 ;
     RECT  32.404 26.64 32.969 26.664 ;
     RECT  32.404 50.832 33.005 51.672 ;
     RECT  32.825 41.28 33.149 42.744 ;
     RECT  32.404 27.888 33.221 27.912 ;
     RECT  32.404 47.808 33.401 48.264 ;
     RECT  32.404 45.12 33.437 45.144 ;
     RECT  32.404 36.816 33.761 37.656 ;
     RECT  33.433 39.168 33.865 39.192 ;
     RECT  32.404 31.728 33.973 33.048 ;
     RECT  33.505 7.632 34.189 7.656 ;
     RECT  32.404 16.512 34.189 16.536 ;
     RECT  32.404 19.632 34.189 19.656 ;
     RECT  32.404 21.216 34.189 21.912 ;
     RECT  32.404 23.328 34.189 23.352 ;
     RECT  33.973 31.584 34.189 33.048 ;
     RECT  33.761 37.536 34.189 37.656 ;
     RECT  33.865 38.688 34.189 39.192 ;
     RECT  33.149 41.904 34.189 42.744 ;
     RECT  33.401 47.904 34.189 48.264 ;
     RECT  33.005 51.648 34.189 51.672 ;
     RECT  34.189 16.512 34.225 18.504 ;
     RECT  34.189 19.584 34.225 23.976 ;
     RECT  34.189 25.104 34.225 25.608 ;
     RECT  34.189 26.88 34.225 27.72 ;
     RECT  34.189 30.912 34.225 33.672 ;
     RECT  34.189 45.792 34.225 45.816 ;
     RECT  34.117 4.416 34.333 4.44 ;
     RECT  34.081 6.048 34.405 6.072 ;
     RECT  34.189 51.12 34.477 51.672 ;
     RECT  34.405 6.048 34.513 6.36 ;
     RECT  34.189 7.344 34.513 8.952 ;
     RECT  34.225 16.512 34.657 23.976 ;
     RECT  34.225 25.104 34.693 27.72 ;
     RECT  34.333 4.416 34.729 4.584 ;
     RECT  34.513 6.048 34.729 8.952 ;
     RECT  34.189 10.416 34.729 11.88 ;
     RECT  32.404 12.96 34.729 12.984 ;
     RECT  34.189 13.968 34.729 13.992 ;
     RECT  34.657 16.032 34.729 23.976 ;
     RECT  34.189 35.616 34.729 35.64 ;
     RECT  34.189 47.904 34.729 49.032 ;
     RECT  34.729 4.416 34.765 8.952 ;
     RECT  34.729 10.416 34.765 23.976 ;
     RECT  34.693 25.104 34.765 28.056 ;
     RECT  34.189 29.328 34.765 29.352 ;
     RECT  34.225 30.432 34.765 33.672 ;
     RECT  34.225 45.792 34.765 45.96 ;
     RECT  34.729 47.232 34.765 49.032 ;
     RECT  34.765 4.416 34.801 9.144 ;
     RECT  34.729 35.616 34.837 36.12 ;
     RECT  34.765 45.168 34.837 49.032 ;
     RECT  34.477 50.64 34.837 51.672 ;
     RECT  34.765 10.416 34.873 33.672 ;
     RECT  34.837 45.168 34.873 49.512 ;
     RECT  34.837 50.64 34.873 51.816 ;
     RECT  34.873 10.416 35.341 34.344 ;
     RECT  34.837 35.616 35.341 36.264 ;
     RECT  34.801 4.416 35.377 9.432 ;
     RECT  35.341 10.416 35.377 36.264 ;
     RECT  34.189 37.536 35.377 40.152 ;
     RECT  34.189 41.28 35.377 44.04 ;
     RECT  34.873 45.168 35.377 51.816 ;
     RECT  35.377 4.416 35.917 40.152 ;
     RECT  35.377 41.28 35.917 51.816 ;
     RECT  35.917 4.416 36.54 51.816 ;
     RECT  36.54 4.656 36.569 4.68 ;
    LAYER M5 ;
     RECT  2.4 2.137 2.52 2.151 ;
     RECT  5.1 2.137 5.22 2.151 ;
     RECT  7.8 2.137 7.92 2.151 ;
     RECT  10.5 2.137 10.62 2.151 ;
     RECT  13.2 2.137 13.32 2.151 ;
     RECT  15.9 2.137 16.02 2.151 ;
     RECT  18.6 2.137 18.72 2.151 ;
     RECT  21.3 2.137 21.42 2.151 ;
     RECT  24 2.137 24.12 2.151 ;
     RECT  26.7 2.137 26.82 2.151 ;
     RECT  29.4 2.137 29.52 2.151 ;
     RECT  32.1 2.137 32.22 2.151 ;
     RECT  5.1 2.151 5.412 8.293 ;
     RECT  7.8 2.151 8.112 9.061 ;
     RECT  7.152 9.061 8.112 10.307 ;
     RECT  7.8 10.307 8.112 10.933 ;
     RECT  7.8 10.933 8.232 11.411 ;
     RECT  4.896 8.293 5.412 18.757 ;
     RECT  4.8 18.757 5.412 19.333 ;
     RECT  7.8 11.411 8.112 22.069 ;
     RECT  7.68 22.069 8.112 23.269 ;
     RECT  6.816 23.269 8.112 25.139 ;
     RECT  4.8 19.333 5.784 25.235 ;
     RECT  7.68 25.139 8.112 27.443 ;
     RECT  5.1 25.235 5.784 28.357 ;
     RECT  5.1 28.357 5.928 29.605 ;
     RECT  7.8 27.443 8.112 31.765 ;
     RECT  7.68 31.765 8.112 32.531 ;
     RECT  5.1 29.605 6.312 34.165 ;
     RECT  7.8 32.531 8.112 34.645 ;
     RECT  7.8 34.645 8.232 34.835 ;
     RECT  7.8 34.835 8.112 35.317 ;
     RECT  4.704 34.165 6.312 35.363 ;
     RECT  7.68 35.317 8.112 37.141 ;
     RECT  7.44 37.141 8.112 38.963 ;
     RECT  5.1 35.363 6.312 39.109 ;
     RECT  5.1 39.109 6.36 45.685 ;
     RECT  4.704 45.685 6.36 46.693 ;
     RECT  4.656 46.693 6.36 46.741 ;
     RECT  7.8 38.963 8.112 46.741 ;
     RECT  4.656 46.741 6.552 46.787 ;
     RECT  4.656 46.787 5.412 46.883 ;
     RECT  6.528 46.787 6.552 47.845 ;
     RECT  7.8 46.741 8.232 47.845 ;
     RECT  6.528 47.845 8.232 51.155 ;
     RECT  6.528 51.155 8.112 51.203 ;
     RECT  6.528 51.203 6.552 51.347 ;
     RECT  9.504 10.981 9.528 51.683 ;
     RECT  0.24 28.405 0.264 51.827 ;
     RECT  2.4 2.151 2.712 54.009 ;
     RECT  5.1 46.883 5.412 54.009 ;
     RECT  7.8 51.203 8.112 54.009 ;
     RECT  10.5 2.151 10.812 54.009 ;
     RECT  13.2 2.151 13.512 54.009 ;
     RECT  15.9 2.151 16.212 54.009 ;
     RECT  18.6 2.151 18.912 54.009 ;
     RECT  21.3 2.151 21.612 54.009 ;
     RECT  24 2.151 24.312 54.009 ;
     RECT  26.7 2.151 27.012 54.009 ;
     RECT  29.4 2.151 29.712 54.009 ;
     RECT  32.1 2.151 32.412 54.009 ;
     RECT  2.4 54.009 2.52 54.023 ;
     RECT  5.1 54.009 5.22 54.023 ;
     RECT  7.8 54.009 7.92 54.023 ;
     RECT  10.5 54.009 10.62 54.023 ;
     RECT  13.2 54.009 13.32 54.023 ;
     RECT  15.9 54.009 16.02 54.023 ;
     RECT  18.6 54.009 18.72 54.023 ;
     RECT  21.3 54.009 21.42 54.023 ;
     RECT  24 54.009 24.12 54.023 ;
     RECT  26.7 54.009 26.82 54.023 ;
     RECT  29.4 54.009 29.52 54.023 ;
     RECT  32.1 54.009 32.22 54.023 ;
     RECT  8.232 10.981 9.504 11.411 ;
     RECT  9.528 10.981 10.5 51.683 ;
     RECT  8.112 11.411 9.504 34.645 ;
     RECT  5.784 23.269 6.816 25.139 ;
     RECT  6.312 29.605 7.8 31.765 ;
     RECT  6.312 31.765 7.68 32.531 ;
     RECT  6.312 32.531 7.8 35.317 ;
     RECT  8.232 34.645 9.504 34.835 ;
     RECT  8.112 34.835 9.504 46.741 ;
     RECT  6.312 35.317 7.68 37.141 ;
     RECT  6.312 37.141 7.44 38.963 ;
     RECT  6.312 38.963 7.8 39.109 ;
     RECT  6.36 39.109 7.8 46.741 ;
     RECT  6.552 46.741 7.8 47.845 ;
     RECT  8.232 46.741 9.504 51.155 ;
     RECT  5.412 46.787 6.528 51.347 ;
     RECT  8.112 51.155 9.504 51.683 ;
     RECT  6.552 51.203 7.8 51.347 ;
  END
END dsfd_stnh_293x1
END LIBRARY
